
VERSION 5.7 ;
BUSBITCHARS "[]" ;
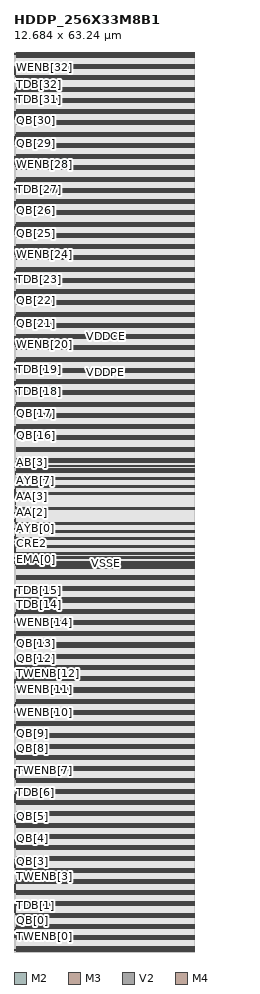
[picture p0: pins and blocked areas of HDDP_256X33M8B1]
MACRO HDDP_256X33M8B1
	FOREIGN HDDP_256X33M8B1 0 0 ;
	SYMMETRY X Y ;
	SIZE 12.684 BY 63.24 ;
	CLASS BLOCK ;
	PIN AA[0]
		USE SIGNAL ;
		DIRECTION INPUT ;
		SHAPE ABUTMENT ;
		PORT
			 LAYER M2 ;
			RECT 0.0098 30.3184 0.0481 30.3561 ;
		END

		ANTENNAGATEAREA 0.00027817 ;
		ANTENNADIFFAREA 0.00194719 ;
		ANTENNAPARTIALMETALAREA 0.00195671 ;
	END AA[0]

	PIN AA[1]
		USE SIGNAL ;
		DIRECTION INPUT ;
		SHAPE ABUTMENT ;
		PORT
			 LAYER M2 ;
			RECT 0.0098 30.3812 0.0481 30.4188 ;
		END

		ANTENNAGATEAREA 0.00027817 ;
		ANTENNADIFFAREA 0.00194719 ;
		ANTENNAPARTIALMETALAREA 0.00195671 ;
	END AA[1]

	PIN AA[2]
		USE SIGNAL ;
		DIRECTION INPUT ;
		SHAPE ABUTMENT ;
		PORT
			 LAYER M2 ;
			RECT 0.0098 30.8455 0.0481 30.8831 ;
		END

		ANTENNAGATEAREA 0.00027817 ;
		ANTENNADIFFAREA 0.00194719 ;
		ANTENNAPARTIALMETALAREA 0.00195671 ;
	END AA[2]

	PIN AA[3]
		USE SIGNAL ;
		DIRECTION INPUT ;
		SHAPE ABUTMENT ;
		PORT
			 LAYER M2 ;
			RECT 0.0098 31.4353 0.0481 31.4729 ;
		END

		ANTENNAGATEAREA 0.00027817 ;
		ANTENNADIFFAREA 0.00194719 ;
		ANTENNAPARTIALMETALAREA 0.00195671 ;
	END AA[3]

	PIN AA[4]
		USE SIGNAL ;
		DIRECTION INPUT ;
		SHAPE ABUTMENT ;
		PORT
			 LAYER M2 ;
			RECT 0.0098 31.8996 0.0481 31.9373 ;
		END

		ANTENNAGATEAREA 0.00027817 ;
		ANTENNADIFFAREA 0.00194719 ;
		ANTENNAPARTIALMETALAREA 0.00195671 ;
	END AA[4]

	PIN AA[5]
		USE SIGNAL ;
		DIRECTION INPUT ;
		SHAPE ABUTMENT ;
		PORT
			 LAYER M2 ;
			RECT 0.0098 31.9624 0.0481 32 ;
		END

		ANTENNAGATEAREA 0.00027817 ;
		ANTENNADIFFAREA 0.00194719 ;
		ANTENNAPARTIALMETALAREA 0.00195671 ;
	END AA[5]

	PIN AA[6]
		USE SIGNAL ;
		DIRECTION INPUT ;
		SHAPE ABUTMENT ;
		PORT
			 LAYER M2 ;
			RECT 0.0098 32.4267 0.0481 32.4643 ;
		END

		ANTENNAGATEAREA 0.00027817 ;
		ANTENNADIFFAREA 0.00194719 ;
		ANTENNAPARTIALMETALAREA 0.00195671 ;
	END AA[6]

	PIN AA[7]
		USE SIGNAL ;
		DIRECTION INPUT ;
		SHAPE ABUTMENT ;
		PORT
			 LAYER M2 ;
			RECT 0.0098 32.4894 0.0481 32.5271 ;
		END

		ANTENNAGATEAREA 0.00027817 ;
		ANTENNADIFFAREA 0.00194719 ;
		ANTENNAPARTIALMETALAREA 0.00195671 ;
	END AA[7]

	PIN AB[0]
		USE SIGNAL ;
		DIRECTION INPUT ;
		SHAPE ABUTMENT ;
		PORT
			 LAYER M3 ;
			RECT 0.0714 30.1051 0.1097 30.2055 ;
		END

		ANTENNAGATEAREA 0.00027817 ;
		ANTENNADIFFAREA 0.00194719 ;
		ANTENNAPARTIALMETALAREA 0.00195671 ;
	END AB[0]

	PIN AB[1]
		USE SIGNAL ;
		DIRECTION INPUT ;
		SHAPE ABUTMENT ;
		PORT
			 LAYER M3 ;
			RECT 0.0714 30.5067 0.1097 30.6071 ;
		END

		ANTENNAGATEAREA 0.00027817 ;
		ANTENNADIFFAREA 0.00194719 ;
		ANTENNAPARTIALMETALAREA 0.00195671 ;
	END AB[1]

	PIN AB[2]
		USE SIGNAL ;
		DIRECTION INPUT ;
		SHAPE ABUTMENT ;
		PORT
			 LAYER M3 ;
			RECT 0.0714 30.6573 0.1097 30.7576 ;
		END

		ANTENNAGATEAREA 0.00027817 ;
		ANTENNADIFFAREA 0.00194719 ;
		ANTENNAPARTIALMETALAREA 0.00195671 ;
	END AB[2]

	PIN AB[3]
		USE SIGNAL ;
		DIRECTION INPUT ;
		SHAPE ABUTMENT ;
		PORT
			 LAYER M2 ;
			RECT 0.0098 34.3718 0.0481 34.4094 ;
		END

		ANTENNAGATEAREA 0.00027817 ;
		ANTENNADIFFAREA 0.00194719 ;
		ANTENNAPARTIALMETALAREA 0.00195671 ;
	END AB[3]

	PIN AB[4]
		USE SIGNAL ;
		DIRECTION INPUT ;
		SHAPE ABUTMENT ;
		PORT
			 LAYER M3 ;
			RECT 0.0714 31.7114 0.1097 31.8118 ;
		END

		ANTENNAGATEAREA 0.00027817 ;
		ANTENNADIFFAREA 0.00194719 ;
		ANTENNAPARTIALMETALAREA 0.00195671 ;
	END AB[4]

	PIN AB[5]
		USE SIGNAL ;
		DIRECTION INPUT ;
		SHAPE ABUTMENT ;
		PORT
			 LAYER M3 ;
			RECT 0.0714 32.0878 0.1097 32.1882 ;
		END

		ANTENNAGATEAREA 0.00027817 ;
		ANTENNADIFFAREA 0.00194719 ;
		ANTENNAPARTIALMETALAREA 0.00195671 ;
	END AB[5]

	PIN AB[6]
		USE SIGNAL ;
		DIRECTION INPUT ;
		SHAPE ABUTMENT ;
		PORT
			 LAYER M3 ;
			RECT 0.0714 32.2384 0.1097 32.3388 ;
		END

		ANTENNAGATEAREA 0.00027817 ;
		ANTENNADIFFAREA 0.00194719 ;
		ANTENNAPARTIALMETALAREA 0.00195671 ;
	END AB[6]

	PIN AB[7]
		USE SIGNAL ;
		DIRECTION INPUT ;
		SHAPE ABUTMENT ;
		PORT
			 LAYER M3 ;
			RECT 0.0714 32.6149 0.1097 32.7153 ;
		END

		ANTENNAGATEAREA 0.00027817 ;
		ANTENNADIFFAREA 0.00194719 ;
		ANTENNAPARTIALMETALAREA 0.00195671 ;
	END AB[7]

	PIN AYA[0]
		USE SIGNAL ;
		DIRECTION OUTPUT ;
		SHAPE ABUTMENT ;
		PORT
			 LAYER M3 ;
			RECT 0.0714 30.2557 0.1097 30.3561 ;
		END

		ANTENNADIFFAREA 0.00194719 ;
		ANTENNAPARTIALMETALAREA 0.00195671 ;
	END AYA[0]

	PIN AYA[1]
		USE SIGNAL ;
		DIRECTION OUTPUT ;
		SHAPE ABUTMENT ;
		PORT
			 LAYER M3 ;
			RECT 0.0714 30.3812 0.1097 30.4816 ;
		END

		ANTENNADIFFAREA 0.00194719 ;
		ANTENNAPARTIALMETALAREA 0.00195671 ;
	END AYA[1]

	PIN AYA[2]
		USE SIGNAL ;
		DIRECTION OUTPUT ;
		SHAPE ABUTMENT ;
		PORT
			 LAYER M3 ;
			RECT 0.0714 30.7827 0.1097 30.8831 ;
		END

		ANTENNADIFFAREA 0.00194719 ;
		ANTENNAPARTIALMETALAREA 0.00195671 ;
	END AYA[2]

	PIN AYA[3]
		USE SIGNAL ;
		DIRECTION OUTPUT ;
		SHAPE ABUTMENT ;
		PORT
			 LAYER M3 ;
			RECT 0.0714 31.4353 0.1097 31.5357 ;
		END

		ANTENNADIFFAREA 0.00194719 ;
		ANTENNAPARTIALMETALAREA 0.00195671 ;
	END AYA[3]

	PIN AYA[4]
		USE SIGNAL ;
		DIRECTION OUTPUT ;
		SHAPE ABUTMENT ;
		PORT
			 LAYER M3 ;
			RECT 0.0714 31.8369 0.1097 31.9373 ;
		END

		ANTENNADIFFAREA 0.00194719 ;
		ANTENNAPARTIALMETALAREA 0.00195671 ;
	END AYA[4]

	PIN AYA[5]
		USE SIGNAL ;
		DIRECTION OUTPUT ;
		SHAPE ABUTMENT ;
		PORT
			 LAYER M3 ;
			RECT 0.0714 31.9624 0.1097 32.0627 ;
		END

		ANTENNADIFFAREA 0.00194719 ;
		ANTENNAPARTIALMETALAREA 0.00195671 ;
	END AYA[5]

	PIN AYA[6]
		USE SIGNAL ;
		DIRECTION OUTPUT ;
		SHAPE ABUTMENT ;
		PORT
			 LAYER M3 ;
			RECT 0.0714 32.3639 0.1097 32.4643 ;
		END

		ANTENNADIFFAREA 0.00194719 ;
		ANTENNAPARTIALMETALAREA 0.00195671 ;
	END AYA[6]

	PIN AYA[7]
		USE SIGNAL ;
		DIRECTION OUTPUT ;
		SHAPE ABUTMENT ;
		PORT
			 LAYER M3 ;
			RECT 0.0714 32.4894 0.1097 32.5898 ;
		END

		ANTENNADIFFAREA 0.00194719 ;
		ANTENNAPARTIALMETALAREA 0.00195671 ;
	END AYA[7]

	PIN AYB[0]
		USE SIGNAL ;
		DIRECTION OUTPUT ;
		SHAPE ABUTMENT ;
		PORT
			 LAYER M2 ;
			RECT 0.0098 30.2557 0.0481 30.2933 ;
		END

		ANTENNADIFFAREA 0.00194719 ;
		ANTENNAPARTIALMETALAREA 0.00195671 ;
	END AYB[0]

	PIN AYB[1]
		USE SIGNAL ;
		DIRECTION OUTPUT ;
		SHAPE ABUTMENT ;
		PORT
			 LAYER M2 ;
			RECT 0.0098 30.4439 0.0481 30.4816 ;
		END

		ANTENNADIFFAREA 0.00194719 ;
		ANTENNAPARTIALMETALAREA 0.00195671 ;
	END AYB[1]

	PIN AYB[2]
		USE SIGNAL ;
		DIRECTION OUTPUT ;
		SHAPE ABUTMENT ;
		PORT
			 LAYER M2 ;
			RECT 0.0098 30.7827 0.0481 30.8204 ;
		END

		ANTENNADIFFAREA 0.00194719 ;
		ANTENNAPARTIALMETALAREA 0.00195671 ;
	END AYB[2]

	PIN AYB[3]
		USE SIGNAL ;
		DIRECTION OUTPUT ;
		SHAPE ABUTMENT ;
		PORT
			 LAYER M2 ;
			RECT 0.0098 31.498 0.0481 31.5357 ;
		END

		ANTENNADIFFAREA 0.00194719 ;
		ANTENNAPARTIALMETALAREA 0.00195671 ;
	END AYB[3]

	PIN AYB[4]
		USE SIGNAL ;
		DIRECTION OUTPUT ;
		SHAPE ABUTMENT ;
		PORT
			 LAYER M2 ;
			RECT 0.0098 31.8369 0.0481 31.8745 ;
		END

		ANTENNADIFFAREA 0.00194719 ;
		ANTENNAPARTIALMETALAREA 0.00195671 ;
	END AYB[4]

	PIN AYB[5]
		USE SIGNAL ;
		DIRECTION OUTPUT ;
		SHAPE ABUTMENT ;
		PORT
			 LAYER M2 ;
			RECT 0.0098 32.0251 0.0481 32.0627 ;
		END

		ANTENNADIFFAREA 0.00194719 ;
		ANTENNAPARTIALMETALAREA 0.00195671 ;
	END AYB[5]

	PIN AYB[6]
		USE SIGNAL ;
		DIRECTION OUTPUT ;
		SHAPE ABUTMENT ;
		PORT
			 LAYER M2 ;
			RECT 0.0098 32.3639 0.0481 32.4016 ;
		END

		ANTENNADIFFAREA 0.00194719 ;
		ANTENNAPARTIALMETALAREA 0.00195671 ;
	END AYB[6]

	PIN AYB[7]
		USE SIGNAL ;
		DIRECTION OUTPUT ;
		SHAPE ABUTMENT ;
		PORT
			 LAYER M2 ;
			RECT 0.0098 32.5522 0.0481 32.5898 ;
		END

		ANTENNADIFFAREA 0.00194719 ;
		ANTENNAPARTIALMETALAREA 0.00195671 ;
	END AYB[7]

	PIN CENA
		USE SIGNAL ;
		DIRECTION INPUT ;
		SHAPE ABUTMENT ;
		PORT
			 LAYER M2 ;
			RECT 0.0098 33.5435 0.0481 33.5812 ;
		END

		ANTENNAGATEAREA 0.00027817 ;
		ANTENNADIFFAREA 0.00194719 ;
		ANTENNAPARTIALMETALAREA 0.00195671 ;
	END CENA

	PIN CENB
		USE SIGNAL ;
		DIRECTION INPUT ;
		SHAPE ABUTMENT ;
		PORT
			 LAYER M3 ;
			RECT 0.0714 33.669 0.1097 33.7694 ;
		END

		ANTENNAGATEAREA 0.00027817 ;
		ANTENNADIFFAREA 0.00194719 ;
		ANTENNAPARTIALMETALAREA 0.00195671 ;
	END CENB

	PIN CENYA
		USE SIGNAL ;
		DIRECTION OUTPUT ;
		SHAPE ABUTMENT ;
		PORT
			 LAYER M3 ;
			RECT 0.0714 33.5435 0.1097 33.6439 ;
		END

		ANTENNADIFFAREA 0.00194719 ;
		ANTENNAPARTIALMETALAREA 0.00195671 ;
	END CENYA

	PIN CENYB
		USE SIGNAL ;
		DIRECTION OUTPUT ;
		SHAPE ABUTMENT ;
		PORT
			 LAYER M2 ;
			RECT 0.0098 33.6063 0.0481 33.6439 ;
		END

		ANTENNADIFFAREA 0.00194719 ;
		ANTENNAPARTIALMETALAREA 0.00195671 ;
	END CENYB

	PIN CLK
		USE SIGNAL ;
		DIRECTION INPUT ;
		SHAPE ABUTMENT ;
		PORT
			 LAYER M3 ;
			RECT 0.0714 29.6533 0.1097 29.7537 ;
		END

		ANTENNAGATEAREA 0.00027817 ;
		ANTENNADIFFAREA 0.00194719 ;
		ANTENNAPARTIALMETALAREA 0.00195671 ;
	END CLK

	PIN CRE1
		USE SIGNAL ;
		DIRECTION INPUT ;
		SHAPE ABUTMENT ;
		PORT
			 LAYER M3 ;
			RECT 0.0714 28.0722 0.1097 28.1725 ;
		END

		ANTENNAGATEAREA 0.00027817 ;
		ANTENNADIFFAREA 0.00194719 ;
		ANTENNAPARTIALMETALAREA 0.00195671 ;
	END CRE1

	PIN CRE2
		USE SIGNAL ;
		DIRECTION INPUT ;
		SHAPE ABUTMENT ;
		PORT
			 LAYER M2 ;
			RECT 0.0098 28.6871 0.0481 28.7247 ;
		END

		ANTENNAGATEAREA 0.00027817 ;
		ANTENNADIFFAREA 0.00194719 ;
		ANTENNAPARTIALMETALAREA 0.00195671 ;
	END CRE2

	PIN DA[0]
		USE SIGNAL ;
		DIRECTION INPUT ;
		SHAPE ABUTMENT ;
		PORT
			 LAYER M2 ;
			RECT 0.0714 1.3929 0.1097 1.4306 ;
			 LAYER M3 ;
			RECT 0.0714 1.3302 0.1097 1.4306 ;
			 LAYER V2 ;
			RECT 0.0831 1.4059 0.098 1.4184 ;
		END

		ANTENNAGATEAREA 0.00027817 ;
		ANTENNADIFFAREA 0.00194719 ;
		ANTENNAPARTIALMETALAREA 0.00195671 ;
	END DA[0]

	PIN DA[10]
		USE SIGNAL ;
		DIRECTION INPUT ;
		SHAPE ABUTMENT ;
		PORT
			 LAYER M2 ;
			RECT 0.0714 17.2047 0.1097 17.2424 ;
			 LAYER M3 ;
			RECT 0.0714 17.142 0.1097 17.2424 ;
			 LAYER V2 ;
			RECT 0.0831 17.2176 0.098 17.2302 ;
		END

		ANTENNAGATEAREA 0.00027817 ;
		ANTENNADIFFAREA 0.00194719 ;
		ANTENNAPARTIALMETALAREA 0.00195671 ;
	END DA[10]

	PIN DA[11]
		USE SIGNAL ;
		DIRECTION INPUT ;
		SHAPE ABUTMENT ;
		PORT
			 LAYER M2 ;
			RECT 0.0714 18.7859 0.1097 18.8235 ;
			 LAYER M3 ;
			RECT 0.0714 18.7231 0.1097 18.8235 ;
			 LAYER V2 ;
			RECT 0.0831 18.7988 0.098 18.8114 ;
		END

		ANTENNAGATEAREA 0.00027817 ;
		ANTENNADIFFAREA 0.00194719 ;
		ANTENNAPARTIALMETALAREA 0.00195671 ;
	END DA[11]

	PIN DA[12]
		USE SIGNAL ;
		DIRECTION INPUT ;
		SHAPE ABUTMENT ;
		PORT
			 LAYER M2 ;
			RECT 0.0714 20.3671 0.1097 20.4047 ;
			 LAYER M3 ;
			RECT 0.0714 20.3043 0.1097 20.4047 ;
			 LAYER V2 ;
			RECT 0.0831 20.38 0.098 20.3925 ;
		END

		ANTENNAGATEAREA 0.00027817 ;
		ANTENNADIFFAREA 0.00194719 ;
		ANTENNAPARTIALMETALAREA 0.00195671 ;
	END DA[12]

	PIN DA[13]
		USE SIGNAL ;
		DIRECTION INPUT ;
		SHAPE ABUTMENT ;
		PORT
			 LAYER M2 ;
			RECT 0.0714 21.9482 0.1097 21.9859 ;
			 LAYER M3 ;
			RECT 0.0714 21.8855 0.1097 21.9859 ;
			 LAYER V2 ;
			RECT 0.0831 21.9612 0.098 21.9737 ;
		END

		ANTENNAGATEAREA 0.00027817 ;
		ANTENNADIFFAREA 0.00194719 ;
		ANTENNAPARTIALMETALAREA 0.00195671 ;
	END DA[13]

	PIN DA[14]
		USE SIGNAL ;
		DIRECTION INPUT ;
		SHAPE ABUTMENT ;
		PORT
			 LAYER M2 ;
			RECT 0.0714 23.5294 0.1097 23.5671 ;
			 LAYER M3 ;
			RECT 0.0714 23.4667 0.1097 23.5671 ;
			 LAYER V2 ;
			RECT 0.0831 23.5424 0.098 23.5549 ;
		END

		ANTENNAGATEAREA 0.00027817 ;
		ANTENNADIFFAREA 0.00194719 ;
		ANTENNAPARTIALMETALAREA 0.00195671 ;
	END DA[14]

	PIN DA[15]
		USE SIGNAL ;
		DIRECTION INPUT ;
		SHAPE ABUTMENT ;
		PORT
			 LAYER M2 ;
			RECT 0.0714 25.1106 0.1097 25.1482 ;
			 LAYER M3 ;
			RECT 0.0714 25.0478 0.1097 25.1482 ;
			 LAYER V2 ;
			RECT 0.0831 25.1235 0.098 25.1361 ;
		END

		ANTENNAGATEAREA 0.00027817 ;
		ANTENNADIFFAREA 0.00194719 ;
		ANTENNAPARTIALMETALAREA 0.00195671 ;
	END DA[15]

	PIN DA[16]
		USE SIGNAL ;
		DIRECTION INPUT ;
		SHAPE ABUTMENT ;
		PORT
			 LAYER M2 ;
			RECT 0.0714 36.4988 0.1097 36.5365 ;
			 LAYER M3 ;
			RECT 0.0714 36.4988 0.1097 36.5992 ;
			 LAYER V2 ;
			RECT 0.0831 36.511 0.098 36.5235 ;
		END

		ANTENNAGATEAREA 0.00027817 ;
		ANTENNADIFFAREA 0.00194719 ;
		ANTENNAPARTIALMETALAREA 0.00195671 ;
	END DA[16]

	PIN DA[17]
		USE SIGNAL ;
		DIRECTION INPUT ;
		SHAPE ABUTMENT ;
		PORT
			 LAYER M2 ;
			RECT 0.0714 38.08 0.1097 38.1176 ;
			 LAYER M3 ;
			RECT 0.0714 38.08 0.1097 38.1804 ;
			 LAYER V2 ;
			RECT 0.0831 38.0922 0.098 38.1047 ;
		END

		ANTENNAGATEAREA 0.00027817 ;
		ANTENNADIFFAREA 0.00194719 ;
		ANTENNAPARTIALMETALAREA 0.00195671 ;
	END DA[17]

	PIN DA[18]
		USE SIGNAL ;
		DIRECTION INPUT ;
		SHAPE ABUTMENT ;
		PORT
			 LAYER M2 ;
			RECT 0.0714 39.6612 0.1097 39.6988 ;
			 LAYER M3 ;
			RECT 0.0714 39.6612 0.1097 39.7616 ;
			 LAYER V2 ;
			RECT 0.0831 39.6733 0.098 39.6859 ;
		END

		ANTENNAGATEAREA 0.00027817 ;
		ANTENNADIFFAREA 0.00194719 ;
		ANTENNAPARTIALMETALAREA 0.00195671 ;
	END DA[18]

	PIN DA[19]
		USE SIGNAL ;
		DIRECTION INPUT ;
		SHAPE ABUTMENT ;
		PORT
			 LAYER M2 ;
			RECT 0.0714 41.2424 0.1097 41.28 ;
			 LAYER M3 ;
			RECT 0.0714 41.2424 0.1097 41.3427 ;
			 LAYER V2 ;
			RECT 0.0831 41.2545 0.098 41.2671 ;
		END

		ANTENNAGATEAREA 0.00027817 ;
		ANTENNADIFFAREA 0.00194719 ;
		ANTENNAPARTIALMETALAREA 0.00195671 ;
	END DA[19]

	PIN DA[1]
		USE SIGNAL ;
		DIRECTION INPUT ;
		SHAPE ABUTMENT ;
		PORT
			 LAYER M2 ;
			RECT 0.0714 2.9741 0.1097 3.0118 ;
			 LAYER M3 ;
			RECT 0.0714 2.9114 0.1097 3.0118 ;
			 LAYER V2 ;
			RECT 0.0831 2.9871 0.098 2.9996 ;
		END

		ANTENNAGATEAREA 0.00027817 ;
		ANTENNADIFFAREA 0.00194719 ;
		ANTENNAPARTIALMETALAREA 0.00195671 ;
	END DA[1]

	PIN DA[20]
		USE SIGNAL ;
		DIRECTION INPUT ;
		SHAPE ABUTMENT ;
		PORT
			 LAYER M2 ;
			RECT 0.0714 42.8235 0.1097 42.8612 ;
			 LAYER M3 ;
			RECT 0.0714 42.8235 0.1097 42.9239 ;
			 LAYER V2 ;
			RECT 0.0831 42.8357 0.098 42.8482 ;
		END

		ANTENNAGATEAREA 0.00027817 ;
		ANTENNADIFFAREA 0.00194719 ;
		ANTENNAPARTIALMETALAREA 0.00195671 ;
	END DA[20]

	PIN DA[21]
		USE SIGNAL ;
		DIRECTION INPUT ;
		SHAPE ABUTMENT ;
		PORT
			 LAYER M2 ;
			RECT 0.0714 44.4047 0.1097 44.4424 ;
			 LAYER M3 ;
			RECT 0.0714 44.4047 0.1097 44.5051 ;
			 LAYER V2 ;
			RECT 0.0831 44.4169 0.098 44.4294 ;
		END

		ANTENNAGATEAREA 0.00027817 ;
		ANTENNADIFFAREA 0.00194719 ;
		ANTENNAPARTIALMETALAREA 0.00195671 ;
	END DA[21]

	PIN DA[22]
		USE SIGNAL ;
		DIRECTION INPUT ;
		SHAPE ABUTMENT ;
		PORT
			 LAYER M2 ;
			RECT 0.0714 45.9859 0.1097 46.0235 ;
			 LAYER M3 ;
			RECT 0.0714 45.9859 0.1097 46.0863 ;
			 LAYER V2 ;
			RECT 0.0831 45.998 0.098 46.0106 ;
		END

		ANTENNAGATEAREA 0.00027817 ;
		ANTENNADIFFAREA 0.00194719 ;
		ANTENNAPARTIALMETALAREA 0.00195671 ;
	END DA[22]

	PIN DA[23]
		USE SIGNAL ;
		DIRECTION INPUT ;
		SHAPE ABUTMENT ;
		PORT
			 LAYER M2 ;
			RECT 0.0714 47.5671 0.1097 47.6047 ;
			 LAYER M3 ;
			RECT 0.0714 47.5671 0.1097 47.6675 ;
			 LAYER V2 ;
			RECT 0.0831 47.5792 0.098 47.5918 ;
		END

		ANTENNAGATEAREA 0.00027817 ;
		ANTENNADIFFAREA 0.00194719 ;
		ANTENNAPARTIALMETALAREA 0.00195671 ;
	END DA[23]

	PIN DA[24]
		USE SIGNAL ;
		DIRECTION INPUT ;
		SHAPE ABUTMENT ;
		PORT
			 LAYER M2 ;
			RECT 0.0714 49.1482 0.1097 49.1859 ;
			 LAYER M3 ;
			RECT 0.0714 49.1482 0.1097 49.2486 ;
			 LAYER V2 ;
			RECT 0.0831 49.1604 0.098 49.1729 ;
		END

		ANTENNAGATEAREA 0.00027817 ;
		ANTENNADIFFAREA 0.00194719 ;
		ANTENNAPARTIALMETALAREA 0.00195671 ;
	END DA[24]

	PIN DA[25]
		USE SIGNAL ;
		DIRECTION INPUT ;
		SHAPE ABUTMENT ;
		PORT
			 LAYER M2 ;
			RECT 0.0714 50.7294 0.1097 50.7671 ;
			 LAYER M3 ;
			RECT 0.0714 50.7294 0.1097 50.8298 ;
			 LAYER V2 ;
			RECT 0.0831 50.7416 0.098 50.7541 ;
		END

		ANTENNAGATEAREA 0.00027817 ;
		ANTENNADIFFAREA 0.00194719 ;
		ANTENNAPARTIALMETALAREA 0.00195671 ;
	END DA[25]

	PIN DA[26]
		USE SIGNAL ;
		DIRECTION INPUT ;
		SHAPE ABUTMENT ;
		PORT
			 LAYER M2 ;
			RECT 0.0714 52.3106 0.1097 52.3482 ;
			 LAYER M3 ;
			RECT 0.0714 52.3106 0.1097 52.411 ;
			 LAYER V2 ;
			RECT 0.0831 52.3227 0.098 52.3353 ;
		END

		ANTENNAGATEAREA 0.00027817 ;
		ANTENNADIFFAREA 0.00194719 ;
		ANTENNAPARTIALMETALAREA 0.00195671 ;
	END DA[26]

	PIN DA[27]
		USE SIGNAL ;
		DIRECTION INPUT ;
		SHAPE ABUTMENT ;
		PORT
			 LAYER M2 ;
			RECT 0.0714 53.8918 0.1097 53.9294 ;
			 LAYER M3 ;
			RECT 0.0714 53.8918 0.1097 53.9922 ;
			 LAYER V2 ;
			RECT 0.0831 53.9039 0.098 53.9165 ;
		END

		ANTENNAGATEAREA 0.00027817 ;
		ANTENNADIFFAREA 0.00194719 ;
		ANTENNAPARTIALMETALAREA 0.00195671 ;
	END DA[27]

	PIN DA[28]
		USE SIGNAL ;
		DIRECTION INPUT ;
		SHAPE ABUTMENT ;
		PORT
			 LAYER M2 ;
			RECT 0.0714 55.4729 0.1097 55.5106 ;
			 LAYER M3 ;
			RECT 0.0714 55.4729 0.1097 55.5733 ;
			 LAYER V2 ;
			RECT 0.0831 55.4851 0.098 55.4976 ;
		END

		ANTENNAGATEAREA 0.00027817 ;
		ANTENNADIFFAREA 0.00194719 ;
		ANTENNAPARTIALMETALAREA 0.00195671 ;
	END DA[28]

	PIN DA[29]
		USE SIGNAL ;
		DIRECTION INPUT ;
		SHAPE ABUTMENT ;
		PORT
			 LAYER M2 ;
			RECT 0.0714 57.0541 0.1097 57.0918 ;
			 LAYER M3 ;
			RECT 0.0714 57.0541 0.1097 57.1545 ;
			 LAYER V2 ;
			RECT 0.0831 57.0663 0.098 57.0788 ;
		END

		ANTENNAGATEAREA 0.00027817 ;
		ANTENNADIFFAREA 0.00194719 ;
		ANTENNAPARTIALMETALAREA 0.00195671 ;
	END DA[29]

	PIN DA[2]
		USE SIGNAL ;
		DIRECTION INPUT ;
		SHAPE ABUTMENT ;
		PORT
			 LAYER M2 ;
			RECT 0.0714 4.5553 0.1097 4.5929 ;
			 LAYER M3 ;
			RECT 0.0714 4.4925 0.1097 4.5929 ;
			 LAYER V2 ;
			RECT 0.0831 4.5682 0.098 4.5808 ;
		END

		ANTENNAGATEAREA 0.00027817 ;
		ANTENNADIFFAREA 0.00194719 ;
		ANTENNAPARTIALMETALAREA 0.00195671 ;
	END DA[2]

	PIN DA[30]
		USE SIGNAL ;
		DIRECTION INPUT ;
		SHAPE ABUTMENT ;
		PORT
			 LAYER M2 ;
			RECT 0.0714 58.6353 0.1097 58.6729 ;
			 LAYER M3 ;
			RECT 0.0714 58.6353 0.1097 58.7357 ;
			 LAYER V2 ;
			RECT 0.0831 58.6475 0.098 58.66 ;
		END

		ANTENNAGATEAREA 0.00027817 ;
		ANTENNADIFFAREA 0.00194719 ;
		ANTENNAPARTIALMETALAREA 0.00195671 ;
	END DA[30]

	PIN DA[31]
		USE SIGNAL ;
		DIRECTION INPUT ;
		SHAPE ABUTMENT ;
		PORT
			 LAYER M2 ;
			RECT 0.0714 60.2165 0.1097 60.2541 ;
			 LAYER M3 ;
			RECT 0.0714 60.2165 0.1097 60.3169 ;
			 LAYER V2 ;
			RECT 0.0831 60.2286 0.098 60.2412 ;
		END

		ANTENNAGATEAREA 0.00027817 ;
		ANTENNADIFFAREA 0.00194719 ;
		ANTENNAPARTIALMETALAREA 0.00195671 ;
	END DA[31]

	PIN DA[32]
		USE SIGNAL ;
		DIRECTION INPUT ;
		SHAPE ABUTMENT ;
		PORT
			 LAYER M2 ;
			RECT 0.0714 61.7976 0.1097 61.8353 ;
			 LAYER M3 ;
			RECT 0.0714 61.7976 0.1097 61.898 ;
			 LAYER V2 ;
			RECT 0.0831 61.8098 0.098 61.8224 ;
		END

		ANTENNAGATEAREA 0.00027817 ;
		ANTENNADIFFAREA 0.00194719 ;
		ANTENNAPARTIALMETALAREA 0.00195671 ;
	END DA[32]

	PIN DA[3]
		USE SIGNAL ;
		DIRECTION INPUT ;
		SHAPE ABUTMENT ;
		PORT
			 LAYER M2 ;
			RECT 0.0714 6.1365 0.1097 6.1741 ;
			 LAYER M3 ;
			RECT 0.0714 6.0737 0.1097 6.1741 ;
			 LAYER V2 ;
			RECT 0.0831 6.1494 0.098 6.162 ;
		END

		ANTENNAGATEAREA 0.00027817 ;
		ANTENNADIFFAREA 0.00194719 ;
		ANTENNAPARTIALMETALAREA 0.00195671 ;
	END DA[3]

	PIN DA[4]
		USE SIGNAL ;
		DIRECTION INPUT ;
		SHAPE ABUTMENT ;
		PORT
			 LAYER M2 ;
			RECT 0.0714 7.7176 0.1097 7.7553 ;
			 LAYER M3 ;
			RECT 0.0714 7.6549 0.1097 7.7553 ;
			 LAYER V2 ;
			RECT 0.0831 7.7306 0.098 7.7431 ;
		END

		ANTENNAGATEAREA 0.00027817 ;
		ANTENNADIFFAREA 0.00194719 ;
		ANTENNAPARTIALMETALAREA 0.00195671 ;
	END DA[4]

	PIN DA[5]
		USE SIGNAL ;
		DIRECTION INPUT ;
		SHAPE ABUTMENT ;
		PORT
			 LAYER M2 ;
			RECT 0.0714 9.2988 0.1097 9.3365 ;
			 LAYER M3 ;
			RECT 0.0714 9.2361 0.1097 9.3365 ;
			 LAYER V2 ;
			RECT 0.0831 9.3118 0.098 9.3243 ;
		END

		ANTENNAGATEAREA 0.00027817 ;
		ANTENNADIFFAREA 0.00194719 ;
		ANTENNAPARTIALMETALAREA 0.00195671 ;
	END DA[5]

	PIN DA[6]
		USE SIGNAL ;
		DIRECTION INPUT ;
		SHAPE ABUTMENT ;
		PORT
			 LAYER M2 ;
			RECT 0.0714 10.88 0.1097 10.9176 ;
			 LAYER M3 ;
			RECT 0.0714 10.8173 0.1097 10.9176 ;
			 LAYER V2 ;
			RECT 0.0831 10.8929 0.098 10.9055 ;
		END

		ANTENNAGATEAREA 0.00027817 ;
		ANTENNADIFFAREA 0.00194719 ;
		ANTENNAPARTIALMETALAREA 0.00195671 ;
	END DA[6]

	PIN DA[7]
		USE SIGNAL ;
		DIRECTION INPUT ;
		SHAPE ABUTMENT ;
		PORT
			 LAYER M2 ;
			RECT 0.0714 12.4612 0.1097 12.4988 ;
			 LAYER M3 ;
			RECT 0.0714 12.3984 0.1097 12.4988 ;
			 LAYER V2 ;
			RECT 0.0831 12.4741 0.098 12.4867 ;
		END

		ANTENNAGATEAREA 0.00027817 ;
		ANTENNADIFFAREA 0.00194719 ;
		ANTENNAPARTIALMETALAREA 0.00195671 ;
	END DA[7]

	PIN DA[8]
		USE SIGNAL ;
		DIRECTION INPUT ;
		SHAPE ABUTMENT ;
		PORT
			 LAYER M2 ;
			RECT 0.0714 14.0424 0.1097 14.08 ;
			 LAYER M3 ;
			RECT 0.0714 13.9796 0.1097 14.08 ;
			 LAYER V2 ;
			RECT 0.0831 14.0553 0.098 14.0678 ;
		END

		ANTENNAGATEAREA 0.00027817 ;
		ANTENNADIFFAREA 0.00194719 ;
		ANTENNAPARTIALMETALAREA 0.00195671 ;
	END DA[8]

	PIN DA[9]
		USE SIGNAL ;
		DIRECTION INPUT ;
		SHAPE ABUTMENT ;
		PORT
			 LAYER M2 ;
			RECT 0.0714 15.6235 0.1097 15.6612 ;
			 LAYER M3 ;
			RECT 0.0714 15.5608 0.1097 15.6612 ;
			 LAYER V2 ;
			RECT 0.0831 15.6365 0.098 15.649 ;
		END

		ANTENNAGATEAREA 0.00027817 ;
		ANTENNADIFFAREA 0.00194719 ;
		ANTENNAPARTIALMETALAREA 0.00195671 ;
	END DA[9]

	PIN DB[0]
		USE SIGNAL ;
		DIRECTION INPUT ;
		SHAPE ABUTMENT ;
		PORT
			 LAYER M3 ;
			RECT 0.0714 1.6314 0.1097 1.7318 ;
		END

		ANTENNAGATEAREA 0.00027817 ;
		ANTENNADIFFAREA 0.00194719 ;
		ANTENNAPARTIALMETALAREA 0.00195671 ;
	END DB[0]

	PIN DB[10]
		USE SIGNAL ;
		DIRECTION INPUT ;
		SHAPE ABUTMENT ;
		PORT
			 LAYER M3 ;
			RECT 0.0714 17.4431 0.1097 17.5435 ;
		END

		ANTENNAGATEAREA 0.00027817 ;
		ANTENNADIFFAREA 0.00194719 ;
		ANTENNAPARTIALMETALAREA 0.00195671 ;
	END DB[10]

	PIN DB[11]
		USE SIGNAL ;
		DIRECTION INPUT ;
		SHAPE ABUTMENT ;
		PORT
			 LAYER M3 ;
			RECT 0.0714 19.0243 0.1097 19.1247 ;
		END

		ANTENNAGATEAREA 0.00027817 ;
		ANTENNADIFFAREA 0.00194719 ;
		ANTENNAPARTIALMETALAREA 0.00195671 ;
	END DB[11]

	PIN DB[12]
		USE SIGNAL ;
		DIRECTION INPUT ;
		SHAPE ABUTMENT ;
		PORT
			 LAYER M3 ;
			RECT 0.0714 20.6055 0.1097 20.7059 ;
		END

		ANTENNAGATEAREA 0.00027817 ;
		ANTENNADIFFAREA 0.00194719 ;
		ANTENNAPARTIALMETALAREA 0.00195671 ;
	END DB[12]

	PIN DB[13]
		USE SIGNAL ;
		DIRECTION INPUT ;
		SHAPE ABUTMENT ;
		PORT
			 LAYER M3 ;
			RECT 0.0714 22.1867 0.1097 22.2871 ;
		END

		ANTENNAGATEAREA 0.00027817 ;
		ANTENNADIFFAREA 0.00194719 ;
		ANTENNAPARTIALMETALAREA 0.00195671 ;
	END DB[13]

	PIN DB[14]
		USE SIGNAL ;
		DIRECTION INPUT ;
		SHAPE ABUTMENT ;
		PORT
			 LAYER M3 ;
			RECT 0.0714 23.7678 0.1097 23.8682 ;
		END

		ANTENNAGATEAREA 0.00027817 ;
		ANTENNADIFFAREA 0.00194719 ;
		ANTENNAPARTIALMETALAREA 0.00195671 ;
	END DB[14]

	PIN DB[15]
		USE SIGNAL ;
		DIRECTION INPUT ;
		SHAPE ABUTMENT ;
		PORT
			 LAYER M3 ;
			RECT 0.0714 25.349 0.1097 25.4494 ;
		END

		ANTENNAGATEAREA 0.00027817 ;
		ANTENNADIFFAREA 0.00194719 ;
		ANTENNAPARTIALMETALAREA 0.00195671 ;
	END DB[15]

	PIN DB[16]
		USE SIGNAL ;
		DIRECTION INPUT ;
		SHAPE ABUTMENT ;
		PORT
			 LAYER M3 ;
			RECT 0.0714 36.1976 0.1097 36.298 ;
		END

		ANTENNAGATEAREA 0.00027817 ;
		ANTENNADIFFAREA 0.00194719 ;
		ANTENNAPARTIALMETALAREA 0.00195671 ;
	END DB[16]

	PIN DB[17]
		USE SIGNAL ;
		DIRECTION INPUT ;
		SHAPE ABUTMENT ;
		PORT
			 LAYER M3 ;
			RECT 0.0714 37.7788 0.1097 37.8792 ;
		END

		ANTENNAGATEAREA 0.00027817 ;
		ANTENNADIFFAREA 0.00194719 ;
		ANTENNAPARTIALMETALAREA 0.00195671 ;
	END DB[17]

	PIN DB[18]
		USE SIGNAL ;
		DIRECTION INPUT ;
		SHAPE ABUTMENT ;
		PORT
			 LAYER M3 ;
			RECT 0.0714 39.36 0.1097 39.4604 ;
		END

		ANTENNAGATEAREA 0.00027817 ;
		ANTENNADIFFAREA 0.00194719 ;
		ANTENNAPARTIALMETALAREA 0.00195671 ;
	END DB[18]

	PIN DB[19]
		USE SIGNAL ;
		DIRECTION INPUT ;
		SHAPE ABUTMENT ;
		PORT
			 LAYER M3 ;
			RECT 0.0714 40.9412 0.1097 41.0416 ;
		END

		ANTENNAGATEAREA 0.00027817 ;
		ANTENNADIFFAREA 0.00194719 ;
		ANTENNAPARTIALMETALAREA 0.00195671 ;
	END DB[19]

	PIN DB[1]
		USE SIGNAL ;
		DIRECTION INPUT ;
		SHAPE ABUTMENT ;
		PORT
			 LAYER M3 ;
			RECT 0.0714 3.2125 0.1097 3.3129 ;
		END

		ANTENNAGATEAREA 0.00027817 ;
		ANTENNADIFFAREA 0.00194719 ;
		ANTENNAPARTIALMETALAREA 0.00195671 ;
	END DB[1]

	PIN DB[20]
		USE SIGNAL ;
		DIRECTION INPUT ;
		SHAPE ABUTMENT ;
		PORT
			 LAYER M3 ;
			RECT 0.0714 42.5224 0.1097 42.6227 ;
		END

		ANTENNAGATEAREA 0.00027817 ;
		ANTENNADIFFAREA 0.00194719 ;
		ANTENNAPARTIALMETALAREA 0.00195671 ;
	END DB[20]

	PIN DB[21]
		USE SIGNAL ;
		DIRECTION INPUT ;
		SHAPE ABUTMENT ;
		PORT
			 LAYER M3 ;
			RECT 0.0714 44.1035 0.1097 44.2039 ;
		END

		ANTENNAGATEAREA 0.00027817 ;
		ANTENNADIFFAREA 0.00194719 ;
		ANTENNAPARTIALMETALAREA 0.00195671 ;
	END DB[21]

	PIN DB[22]
		USE SIGNAL ;
		DIRECTION INPUT ;
		SHAPE ABUTMENT ;
		PORT
			 LAYER M3 ;
			RECT 0.0714 45.6847 0.1097 45.7851 ;
		END

		ANTENNAGATEAREA 0.00027817 ;
		ANTENNADIFFAREA 0.00194719 ;
		ANTENNAPARTIALMETALAREA 0.00195671 ;
	END DB[22]

	PIN DB[23]
		USE SIGNAL ;
		DIRECTION INPUT ;
		SHAPE ABUTMENT ;
		PORT
			 LAYER M3 ;
			RECT 0.0714 47.2659 0.1097 47.3663 ;
		END

		ANTENNAGATEAREA 0.00027817 ;
		ANTENNADIFFAREA 0.00194719 ;
		ANTENNAPARTIALMETALAREA 0.00195671 ;
	END DB[23]

	PIN DB[24]
		USE SIGNAL ;
		DIRECTION INPUT ;
		SHAPE ABUTMENT ;
		PORT
			 LAYER M3 ;
			RECT 0.0714 48.8471 0.1097 48.9475 ;
		END

		ANTENNAGATEAREA 0.00027817 ;
		ANTENNADIFFAREA 0.00194719 ;
		ANTENNAPARTIALMETALAREA 0.00195671 ;
	END DB[24]

	PIN DB[25]
		USE SIGNAL ;
		DIRECTION INPUT ;
		SHAPE ABUTMENT ;
		PORT
			 LAYER M3 ;
			RECT 0.0714 50.4282 0.1097 50.5286 ;
		END

		ANTENNAGATEAREA 0.00027817 ;
		ANTENNADIFFAREA 0.00194719 ;
		ANTENNAPARTIALMETALAREA 0.00195671 ;
	END DB[25]

	PIN DB[26]
		USE SIGNAL ;
		DIRECTION INPUT ;
		SHAPE ABUTMENT ;
		PORT
			 LAYER M3 ;
			RECT 0.0714 52.0094 0.1097 52.1098 ;
		END

		ANTENNAGATEAREA 0.00027817 ;
		ANTENNADIFFAREA 0.00194719 ;
		ANTENNAPARTIALMETALAREA 0.00195671 ;
	END DB[26]

	PIN DB[27]
		USE SIGNAL ;
		DIRECTION INPUT ;
		SHAPE ABUTMENT ;
		PORT
			 LAYER M3 ;
			RECT 0.0714 53.5906 0.1097 53.691 ;
		END

		ANTENNAGATEAREA 0.00027817 ;
		ANTENNADIFFAREA 0.00194719 ;
		ANTENNAPARTIALMETALAREA 0.00195671 ;
	END DB[27]

	PIN DB[28]
		USE SIGNAL ;
		DIRECTION INPUT ;
		SHAPE ABUTMENT ;
		PORT
			 LAYER M3 ;
			RECT 0.0714 55.1718 0.1097 55.2722 ;
		END

		ANTENNAGATEAREA 0.00027817 ;
		ANTENNADIFFAREA 0.00194719 ;
		ANTENNAPARTIALMETALAREA 0.00195671 ;
	END DB[28]

	PIN DB[29]
		USE SIGNAL ;
		DIRECTION INPUT ;
		SHAPE ABUTMENT ;
		PORT
			 LAYER M3 ;
			RECT 0.0714 56.7529 0.1097 56.8533 ;
		END

		ANTENNAGATEAREA 0.00027817 ;
		ANTENNADIFFAREA 0.00194719 ;
		ANTENNAPARTIALMETALAREA 0.00195671 ;
	END DB[29]

	PIN DB[2]
		USE SIGNAL ;
		DIRECTION INPUT ;
		SHAPE ABUTMENT ;
		PORT
			 LAYER M3 ;
			RECT 0.0714 4.7937 0.1097 4.8941 ;
		END

		ANTENNAGATEAREA 0.00027817 ;
		ANTENNADIFFAREA 0.00194719 ;
		ANTENNAPARTIALMETALAREA 0.00195671 ;
	END DB[2]

	PIN DB[30]
		USE SIGNAL ;
		DIRECTION INPUT ;
		SHAPE ABUTMENT ;
		PORT
			 LAYER M3 ;
			RECT 0.0714 58.3341 0.1097 58.4345 ;
		END

		ANTENNAGATEAREA 0.00027817 ;
		ANTENNADIFFAREA 0.00194719 ;
		ANTENNAPARTIALMETALAREA 0.00195671 ;
	END DB[30]

	PIN DB[31]
		USE SIGNAL ;
		DIRECTION INPUT ;
		SHAPE ABUTMENT ;
		PORT
			 LAYER M3 ;
			RECT 0.0714 59.9153 0.1097 60.0157 ;
		END

		ANTENNAGATEAREA 0.00027817 ;
		ANTENNADIFFAREA 0.00194719 ;
		ANTENNAPARTIALMETALAREA 0.00195671 ;
	END DB[31]

	PIN DB[32]
		USE SIGNAL ;
		DIRECTION INPUT ;
		SHAPE ABUTMENT ;
		PORT
			 LAYER M3 ;
			RECT 0.0714 61.4965 0.1097 61.5969 ;
		END

		ANTENNAGATEAREA 0.00027817 ;
		ANTENNADIFFAREA 0.00194719 ;
		ANTENNAPARTIALMETALAREA 0.00195671 ;
	END DB[32]

	PIN DB[3]
		USE SIGNAL ;
		DIRECTION INPUT ;
		SHAPE ABUTMENT ;
		PORT
			 LAYER M3 ;
			RECT 0.0714 6.3749 0.1097 6.4753 ;
		END

		ANTENNAGATEAREA 0.00027817 ;
		ANTENNADIFFAREA 0.00194719 ;
		ANTENNAPARTIALMETALAREA 0.00195671 ;
	END DB[3]

	PIN DB[4]
		USE SIGNAL ;
		DIRECTION INPUT ;
		SHAPE ABUTMENT ;
		PORT
			 LAYER M3 ;
			RECT 0.0714 7.9561 0.1097 8.0565 ;
		END

		ANTENNAGATEAREA 0.00027817 ;
		ANTENNADIFFAREA 0.00194719 ;
		ANTENNAPARTIALMETALAREA 0.00195671 ;
	END DB[4]

	PIN DB[5]
		USE SIGNAL ;
		DIRECTION INPUT ;
		SHAPE ABUTMENT ;
		PORT
			 LAYER M3 ;
			RECT 0.0714 9.5373 0.1097 9.6376 ;
		END

		ANTENNAGATEAREA 0.00027817 ;
		ANTENNADIFFAREA 0.00194719 ;
		ANTENNAPARTIALMETALAREA 0.00195671 ;
	END DB[5]

	PIN DB[6]
		USE SIGNAL ;
		DIRECTION INPUT ;
		SHAPE ABUTMENT ;
		PORT
			 LAYER M3 ;
			RECT 0.0714 11.1184 0.1097 11.2188 ;
		END

		ANTENNAGATEAREA 0.00027817 ;
		ANTENNADIFFAREA 0.00194719 ;
		ANTENNAPARTIALMETALAREA 0.00195671 ;
	END DB[6]

	PIN DB[7]
		USE SIGNAL ;
		DIRECTION INPUT ;
		SHAPE ABUTMENT ;
		PORT
			 LAYER M3 ;
			RECT 0.0714 12.6996 0.1097 12.8 ;
		END

		ANTENNAGATEAREA 0.00027817 ;
		ANTENNADIFFAREA 0.00194719 ;
		ANTENNAPARTIALMETALAREA 0.00195671 ;
	END DB[7]

	PIN DB[8]
		USE SIGNAL ;
		DIRECTION INPUT ;
		SHAPE ABUTMENT ;
		PORT
			 LAYER M3 ;
			RECT 0.0714 14.2808 0.1097 14.3812 ;
		END

		ANTENNAGATEAREA 0.00027817 ;
		ANTENNADIFFAREA 0.00194719 ;
		ANTENNAPARTIALMETALAREA 0.00195671 ;
	END DB[8]

	PIN DB[9]
		USE SIGNAL ;
		DIRECTION INPUT ;
		SHAPE ABUTMENT ;
		PORT
			 LAYER M3 ;
			RECT 0.0714 15.862 0.1097 15.9624 ;
		END

		ANTENNAGATEAREA 0.00027817 ;
		ANTENNADIFFAREA 0.00194719 ;
		ANTENNAPARTIALMETALAREA 0.00195671 ;
	END DB[9]

	PIN DFTRAMBYP
		USE SIGNAL ;
		DIRECTION INPUT ;
		SHAPE ABUTMENT ;
		PORT
			 LAYER M2 ;
			RECT 0.0098 28.6243 0.0481 28.662 ;
		END

		ANTENNAGATEAREA 0.00027817 ;
		ANTENNADIFFAREA 0.00194719 ;
		ANTENNAPARTIALMETALAREA 0.00195671 ;
	END DFTRAMBYP

	PIN EMAP
		USE SIGNAL ;
		DIRECTION INPUT ;
		SHAPE ABUTMENT ;
		PORT
			 LAYER M2 ;
			RECT 0.0098 29.5027 0.0481 29.5404 ;
		END

		ANTENNAGATEAREA 0.00027817 ;
		ANTENNADIFFAREA 0.00194719 ;
		ANTENNAPARTIALMETALAREA 0.00195671 ;
	END EMAP

	PIN EMAS
		USE SIGNAL ;
		DIRECTION INPUT ;
		SHAPE ABUTMENT ;
		PORT
			 LAYER M3 ;
			RECT 0.0714 28.2227 0.1097 28.3231 ;
		END

		ANTENNAGATEAREA 0.00027817 ;
		ANTENNADIFFAREA 0.00194719 ;
		ANTENNAPARTIALMETALAREA 0.00195671 ;
	END EMAS

	PIN EMAW[0]
		USE SIGNAL ;
		DIRECTION INPUT ;
		SHAPE ABUTMENT ;
		PORT
			 LAYER M2 ;
			RECT 0.0098 28.2855 0.0481 28.3231 ;
		END

		ANTENNAGATEAREA 0.00027817 ;
		ANTENNADIFFAREA 0.00194719 ;
		ANTENNAPARTIALMETALAREA 0.00195671 ;
	END EMAW[0]

	PIN EMAW[1]
		USE SIGNAL ;
		DIRECTION INPUT ;
		SHAPE ABUTMENT ;
		PORT
			 LAYER M2 ;
			RECT 0.0098 28.2227 0.0481 28.2604 ;
		END

		ANTENNAGATEAREA 0.00027817 ;
		ANTENNADIFFAREA 0.00194719 ;
		ANTENNAPARTIALMETALAREA 0.00195671 ;
	END EMAW[1]

	PIN EMA[0]
		USE SIGNAL ;
		DIRECTION INPUT ;
		SHAPE ABUTMENT ;
		PORT
			 LAYER M2 ;
			RECT 0.0098 28.0722 0.0481 28.1098 ;
		END

		ANTENNAGATEAREA 0.00027817 ;
		ANTENNADIFFAREA 0.00194719 ;
		ANTENNAPARTIALMETALAREA 0.00195671 ;
	END EMA[0]

	PIN EMA[1]
		USE SIGNAL ;
		DIRECTION INPUT ;
		SHAPE ABUTMENT ;
		PORT
			 LAYER M2 ;
			RECT 0.0098 28.1349 0.0481 28.1725 ;
		END

		ANTENNAGATEAREA 0.00027817 ;
		ANTENNADIFFAREA 0.00194719 ;
		ANTENNAPARTIALMETALAREA 0.00195671 ;
	END EMA[1]

	PIN EMA[2]
		USE SIGNAL ;
		DIRECTION INPUT ;
		SHAPE ABUTMENT ;
		PORT
			 LAYER M3 ;
			RECT 0.0714 29.0761 0.1097 29.1765 ;
		END

		ANTENNAGATEAREA 0.00027817 ;
		ANTENNADIFFAREA 0.00194719 ;
		ANTENNAPARTIALMETALAREA 0.00195671 ;
	END EMA[2]

	PIN FCA1[0]
		USE SIGNAL ;
		DIRECTION INPUT ;
		SHAPE ABUTMENT ;
		PORT
			 LAYER M2 ;
			RECT 0.0098 31.6235 0.0481 31.6612 ;
		END

		ANTENNAGATEAREA 0.00027817 ;
		ANTENNADIFFAREA 0.00194719 ;
		ANTENNAPARTIALMETALAREA 0.00195671 ;
	END FCA1[0]

	PIN FCA1[1]
		USE SIGNAL ;
		DIRECTION INPUT ;
		SHAPE ABUTMENT ;
		PORT
			 LAYER M2 ;
			RECT 0.0098 27.3192 0.0481 27.4196 ;
			 LAYER M3 ;
			RECT 0.0098 27.3192 0.0481 27.4196 ;
			 LAYER V2 ;
			RECT 0.021 27.3941 0.0359 27.4067 ;
		END

		ANTENNAGATEAREA 0.00027817 ;
		ANTENNADIFFAREA 0.00194719 ;
		ANTENNAPARTIALMETALAREA 0.00195671 ;
	END FCA1[1]

	PIN FCA1[2]
		USE SIGNAL ;
		DIRECTION INPUT ;
		SHAPE ABUTMENT ;
		PORT
			 LAYER M2 ;
			RECT 0.0098 27.6831 0.0481 27.7208 ;
		END

		ANTENNAGATEAREA 0.00027817 ;
		ANTENNADIFFAREA 0.00194719 ;
		ANTENNAPARTIALMETALAREA 0.00195671 ;
	END FCA1[2]

	PIN FCA1[3]
		USE SIGNAL ;
		DIRECTION INPUT ;
		SHAPE ABUTMENT ;
		PORT
			 LAYER M3 ;
			RECT 0.0714 29.2267 0.1097 29.3271 ;
		END

		ANTENNAGATEAREA 0.00027817 ;
		ANTENNADIFFAREA 0.00194719 ;
		ANTENNAPARTIALMETALAREA 0.00195671 ;
	END FCA1[3]

	PIN FCA2[0]
		USE SIGNAL ;
		DIRECTION INPUT ;
		SHAPE ABUTMENT ;
		PORT
			 LAYER M3 ;
			RECT 0.0714 29.5027 0.1097 29.6031 ;
		END

		ANTENNAGATEAREA 0.00027817 ;
		ANTENNADIFFAREA 0.00194719 ;
		ANTENNAPARTIALMETALAREA 0.00195671 ;
	END FCA2[0]

	PIN FCA2[1]
		USE SIGNAL ;
		DIRECTION INPUT ;
		SHAPE ABUTMENT ;
		PORT
			 LAYER M2 ;
			RECT 0.0098 34.4345 0.0481 34.4722 ;
		END

		ANTENNAGATEAREA 0.00027817 ;
		ANTENNADIFFAREA 0.00194719 ;
		ANTENNAPARTIALMETALAREA 0.00195671 ;
	END FCA2[1]

	PIN FCA2[2]
		USE SIGNAL ;
		DIRECTION INPUT ;
		SHAPE ABUTMENT ;
		PORT
			 LAYER M2 ;
			RECT 0.0098 27.6204 0.0481 27.658 ;
		END

		ANTENNAGATEAREA 0.00027817 ;
		ANTENNADIFFAREA 0.00194719 ;
		ANTENNAPARTIALMETALAREA 0.00195671 ;
	END FCA2[2]

	PIN FCA2[3]
		USE SIGNAL ;
		DIRECTION INPUT ;
		SHAPE ABUTMENT ;
		PORT
			 LAYER M3 ;
			RECT 0.0714 34.0706 0.1097 34.171 ;
		END

		ANTENNAGATEAREA 0.00027817 ;
		ANTENNADIFFAREA 0.00194719 ;
		ANTENNAPARTIALMETALAREA 0.00195671 ;
	END FCA2[3]

	PIN FCA2[4]
		USE SIGNAL ;
		DIRECTION INPUT ;
		SHAPE ABUTMENT ;
		PORT
			 LAYER M2 ;
			RECT 0.0098 34.0706 0.0481 34.1082 ;
		END

		ANTENNAGATEAREA 0.00027817 ;
		ANTENNADIFFAREA 0.00194719 ;
		ANTENNAPARTIALMETALAREA 0.00195671 ;
	END FCA2[4]

	PIN GWENA
		USE SIGNAL ;
		DIRECTION INPUT ;
		SHAPE ABUTMENT ;
		PORT
			 LAYER M2 ;
			RECT 0.0098 28.4361 0.0481 28.4737 ;
			 LAYER M3 ;
			RECT 0.0098 28.3733 0.0481 28.4737 ;
			 LAYER V2 ;
			RECT 0.0215 28.4482 0.0364 28.4608 ;
		END

		ANTENNAGATEAREA 0.00027817 ;
		ANTENNADIFFAREA 0.00194719 ;
		ANTENNAPARTIALMETALAREA 0.00195671 ;
	END GWENA

	PIN GWENB
		USE SIGNAL ;
		DIRECTION INPUT ;
		SHAPE ABUTMENT ;
		PORT
			 LAYER M2 ;
			RECT 0.0098 28.7498 0.0481 28.7875 ;
			 LAYER M3 ;
			RECT 0.0098 28.7498 0.0481 28.8502 ;
			 LAYER V2 ;
			RECT 0.0215 28.7627 0.0364 28.7753 ;
		END

		ANTENNAGATEAREA 0.00027817 ;
		ANTENNADIFFAREA 0.00194719 ;
		ANTENNAPARTIALMETALAREA 0.00195671 ;
	END GWENB

	PIN GWENYA
		USE SIGNAL ;
		DIRECTION OUTPUT ;
		SHAPE ABUTMENT ;
		PORT
			 LAYER M2 ;
			RECT 0.0098 28.5616 0.0481 28.5992 ;
			 LAYER M3 ;
			RECT 0.0098 28.4988 0.0481 28.5992 ;
			 LAYER V2 ;
			RECT 0.0215 28.5737 0.0364 28.5863 ;
		END

		ANTENNADIFFAREA 0.00194719 ;
		ANTENNAPARTIALMETALAREA 0.00195671 ;
	END GWENYA

	PIN GWENYB
		USE SIGNAL ;
		DIRECTION OUTPUT ;
		SHAPE ABUTMENT ;
		PORT
			 LAYER M2 ;
			RECT 0.0714 28.8125 0.1097 28.8502 ;
			 LAYER M3 ;
			RECT 0.0714 28.7498 0.1097 28.8502 ;
			 LAYER V2 ;
			RECT 0.0831 28.8255 0.098 28.838 ;
		END

		ANTENNADIFFAREA 0.00194719 ;
		ANTENNAPARTIALMETALAREA 0.00195671 ;
	END GWENYB

	PIN QA[0]
		USE SIGNAL ;
		DIRECTION OUTPUT ;
		SHAPE ABUTMENT ;
		PORT
			 LAYER M2 ;
			RECT 0.0098 1.5435 0.0481 1.5812 ;
			 LAYER M3 ;
			RECT 0.0098 1.4808 0.0481 1.5812 ;
			 LAYER V2 ;
			RECT 0.0215 1.5557 0.0364 1.5682 ;
		END

		ANTENNADIFFAREA 0.00194719 ;
		ANTENNAPARTIALMETALAREA 0.00195671 ;
	END QA[0]

	PIN QA[10]
		USE SIGNAL ;
		DIRECTION OUTPUT ;
		SHAPE ABUTMENT ;
		PORT
			 LAYER M2 ;
			RECT 0.0098 17.3553 0.0481 17.3929 ;
			 LAYER M3 ;
			RECT 0.0098 17.2925 0.0481 17.3929 ;
			 LAYER V2 ;
			RECT 0.0215 17.3675 0.0364 17.38 ;
		END

		ANTENNADIFFAREA 0.00194719 ;
		ANTENNAPARTIALMETALAREA 0.00195671 ;
	END QA[10]

	PIN QA[11]
		USE SIGNAL ;
		DIRECTION OUTPUT ;
		SHAPE ABUTMENT ;
		PORT
			 LAYER M2 ;
			RECT 0.0098 18.9365 0.0481 18.9741 ;
			 LAYER M3 ;
			RECT 0.0098 18.8737 0.0481 18.9741 ;
			 LAYER V2 ;
			RECT 0.0215 18.9486 0.0364 18.9612 ;
		END

		ANTENNADIFFAREA 0.00194719 ;
		ANTENNAPARTIALMETALAREA 0.00195671 ;
	END QA[11]

	PIN QA[12]
		USE SIGNAL ;
		DIRECTION OUTPUT ;
		SHAPE ABUTMENT ;
		PORT
			 LAYER M2 ;
			RECT 0.0098 20.5176 0.0481 20.5553 ;
			 LAYER M3 ;
			RECT 0.0098 20.4549 0.0481 20.5553 ;
			 LAYER V2 ;
			RECT 0.0215 20.5298 0.0364 20.5424 ;
		END

		ANTENNADIFFAREA 0.00194719 ;
		ANTENNAPARTIALMETALAREA 0.00195671 ;
	END QA[12]

	PIN QA[13]
		USE SIGNAL ;
		DIRECTION OUTPUT ;
		SHAPE ABUTMENT ;
		PORT
			 LAYER M2 ;
			RECT 0.0098 22.0988 0.0481 22.1365 ;
			 LAYER M3 ;
			RECT 0.0098 22.0361 0.0481 22.1365 ;
			 LAYER V2 ;
			RECT 0.0215 22.111 0.0364 22.1235 ;
		END

		ANTENNADIFFAREA 0.00194719 ;
		ANTENNAPARTIALMETALAREA 0.00195671 ;
	END QA[13]

	PIN QA[14]
		USE SIGNAL ;
		DIRECTION OUTPUT ;
		SHAPE ABUTMENT ;
		PORT
			 LAYER M2 ;
			RECT 0.0098 23.68 0.0481 23.7176 ;
			 LAYER M3 ;
			RECT 0.0098 23.6173 0.0481 23.7176 ;
			 LAYER V2 ;
			RECT 0.0215 23.6922 0.0364 23.7047 ;
		END

		ANTENNADIFFAREA 0.00194719 ;
		ANTENNAPARTIALMETALAREA 0.00195671 ;
	END QA[14]

	PIN QA[15]
		USE SIGNAL ;
		DIRECTION OUTPUT ;
		SHAPE ABUTMENT ;
		PORT
			 LAYER M2 ;
			RECT 0.0098 25.2612 0.0481 25.2988 ;
			 LAYER M3 ;
			RECT 0.0098 25.1984 0.0481 25.2988 ;
			 LAYER V2 ;
			RECT 0.0215 25.2733 0.0364 25.2859 ;
		END

		ANTENNADIFFAREA 0.00194719 ;
		ANTENNAPARTIALMETALAREA 0.00195671 ;
	END QA[15]

	PIN QA[16]
		USE SIGNAL ;
		DIRECTION OUTPUT ;
		SHAPE ABUTMENT ;
		PORT
			 LAYER M2 ;
			RECT 0.0098 36.3482 0.0481 36.3859 ;
			 LAYER M3 ;
			RECT 0.0098 36.3482 0.0481 36.4486 ;
			 LAYER V2 ;
			RECT 0.0215 36.3612 0.0364 36.3737 ;
		END

		ANTENNADIFFAREA 0.00194719 ;
		ANTENNAPARTIALMETALAREA 0.00195671 ;
	END QA[16]

	PIN QA[17]
		USE SIGNAL ;
		DIRECTION OUTPUT ;
		SHAPE ABUTMENT ;
		PORT
			 LAYER M2 ;
			RECT 0.0098 37.9294 0.0481 37.9671 ;
			 LAYER M3 ;
			RECT 0.0098 37.9294 0.0481 38.0298 ;
			 LAYER V2 ;
			RECT 0.0215 37.9424 0.0364 37.9549 ;
		END

		ANTENNADIFFAREA 0.00194719 ;
		ANTENNAPARTIALMETALAREA 0.00195671 ;
	END QA[17]

	PIN QA[18]
		USE SIGNAL ;
		DIRECTION OUTPUT ;
		SHAPE ABUTMENT ;
		PORT
			 LAYER M2 ;
			RECT 0.0098 39.5106 0.0481 39.5482 ;
			 LAYER M3 ;
			RECT 0.0098 39.5106 0.0481 39.611 ;
			 LAYER V2 ;
			RECT 0.0215 39.5235 0.0364 39.5361 ;
		END

		ANTENNADIFFAREA 0.00194719 ;
		ANTENNAPARTIALMETALAREA 0.00195671 ;
	END QA[18]

	PIN QA[19]
		USE SIGNAL ;
		DIRECTION OUTPUT ;
		SHAPE ABUTMENT ;
		PORT
			 LAYER M2 ;
			RECT 0.0098 41.0918 0.0481 41.1294 ;
			 LAYER M3 ;
			RECT 0.0098 41.0918 0.0481 41.1922 ;
			 LAYER V2 ;
			RECT 0.0215 41.1047 0.0364 41.1173 ;
		END

		ANTENNADIFFAREA 0.00194719 ;
		ANTENNAPARTIALMETALAREA 0.00195671 ;
	END QA[19]

	PIN QA[1]
		USE SIGNAL ;
		DIRECTION OUTPUT ;
		SHAPE ABUTMENT ;
		PORT
			 LAYER M2 ;
			RECT 0.0098 3.1247 0.0481 3.1624 ;
			 LAYER M3 ;
			RECT 0.0098 3.062 0.0481 3.1624 ;
			 LAYER V2 ;
			RECT 0.0215 3.1369 0.0364 3.1494 ;
		END

		ANTENNADIFFAREA 0.00194719 ;
		ANTENNAPARTIALMETALAREA 0.00195671 ;
	END QA[1]

	PIN QA[20]
		USE SIGNAL ;
		DIRECTION OUTPUT ;
		SHAPE ABUTMENT ;
		PORT
			 LAYER M2 ;
			RECT 0.0098 42.6729 0.0481 42.7106 ;
			 LAYER M3 ;
			RECT 0.0098 42.6729 0.0481 42.7733 ;
			 LAYER V2 ;
			RECT 0.0215 42.6859 0.0364 42.6984 ;
		END

		ANTENNADIFFAREA 0.00194719 ;
		ANTENNAPARTIALMETALAREA 0.00195671 ;
	END QA[20]

	PIN QA[21]
		USE SIGNAL ;
		DIRECTION OUTPUT ;
		SHAPE ABUTMENT ;
		PORT
			 LAYER M2 ;
			RECT 0.0098 44.2541 0.0481 44.2918 ;
			 LAYER M3 ;
			RECT 0.0098 44.2541 0.0481 44.3545 ;
			 LAYER V2 ;
			RECT 0.0215 44.2671 0.0364 44.2796 ;
		END

		ANTENNADIFFAREA 0.00194719 ;
		ANTENNAPARTIALMETALAREA 0.00195671 ;
	END QA[21]

	PIN QA[22]
		USE SIGNAL ;
		DIRECTION OUTPUT ;
		SHAPE ABUTMENT ;
		PORT
			 LAYER M2 ;
			RECT 0.0098 45.8353 0.0481 45.8729 ;
			 LAYER M3 ;
			RECT 0.0098 45.8353 0.0481 45.9357 ;
			 LAYER V2 ;
			RECT 0.0215 45.8482 0.0364 45.8608 ;
		END

		ANTENNADIFFAREA 0.00194719 ;
		ANTENNAPARTIALMETALAREA 0.00195671 ;
	END QA[22]

	PIN QA[23]
		USE SIGNAL ;
		DIRECTION OUTPUT ;
		SHAPE ABUTMENT ;
		PORT
			 LAYER M2 ;
			RECT 0.0098 47.4165 0.0481 47.4541 ;
			 LAYER M3 ;
			RECT 0.0098 47.4165 0.0481 47.5169 ;
			 LAYER V2 ;
			RECT 0.0215 47.4294 0.0364 47.442 ;
		END

		ANTENNADIFFAREA 0.00194719 ;
		ANTENNAPARTIALMETALAREA 0.00195671 ;
	END QA[23]

	PIN QA[24]
		USE SIGNAL ;
		DIRECTION OUTPUT ;
		SHAPE ABUTMENT ;
		PORT
			 LAYER M2 ;
			RECT 0.0098 48.9976 0.0481 49.0353 ;
			 LAYER M3 ;
			RECT 0.0098 48.9976 0.0481 49.098 ;
			 LAYER V2 ;
			RECT 0.0215 49.0106 0.0364 49.0231 ;
		END

		ANTENNADIFFAREA 0.00194719 ;
		ANTENNAPARTIALMETALAREA 0.00195671 ;
	END QA[24]

	PIN QA[25]
		USE SIGNAL ;
		DIRECTION OUTPUT ;
		SHAPE ABUTMENT ;
		PORT
			 LAYER M2 ;
			RECT 0.0098 50.5788 0.0481 50.6165 ;
			 LAYER M3 ;
			RECT 0.0098 50.5788 0.0481 50.6792 ;
			 LAYER V2 ;
			RECT 0.0215 50.5918 0.0364 50.6043 ;
		END

		ANTENNADIFFAREA 0.00194719 ;
		ANTENNAPARTIALMETALAREA 0.00195671 ;
	END QA[25]

	PIN QA[26]
		USE SIGNAL ;
		DIRECTION OUTPUT ;
		SHAPE ABUTMENT ;
		PORT
			 LAYER M2 ;
			RECT 0.0098 52.16 0.0481 52.1976 ;
			 LAYER M3 ;
			RECT 0.0098 52.16 0.0481 52.2604 ;
			 LAYER V2 ;
			RECT 0.0215 52.1729 0.0364 52.1855 ;
		END

		ANTENNADIFFAREA 0.00194719 ;
		ANTENNAPARTIALMETALAREA 0.00195671 ;
	END QA[26]

	PIN QA[27]
		USE SIGNAL ;
		DIRECTION OUTPUT ;
		SHAPE ABUTMENT ;
		PORT
			 LAYER M2 ;
			RECT 0.0098 53.7412 0.0481 53.7788 ;
			 LAYER M3 ;
			RECT 0.0098 53.7412 0.0481 53.8416 ;
			 LAYER V2 ;
			RECT 0.0215 53.7541 0.0364 53.7667 ;
		END

		ANTENNADIFFAREA 0.00194719 ;
		ANTENNAPARTIALMETALAREA 0.00195671 ;
	END QA[27]

	PIN QA[28]
		USE SIGNAL ;
		DIRECTION OUTPUT ;
		SHAPE ABUTMENT ;
		PORT
			 LAYER M2 ;
			RECT 0.0098 55.3224 0.0481 55.36 ;
			 LAYER M3 ;
			RECT 0.0098 55.3224 0.0481 55.4227 ;
			 LAYER V2 ;
			RECT 0.0215 55.3353 0.0364 55.3478 ;
		END

		ANTENNADIFFAREA 0.00194719 ;
		ANTENNAPARTIALMETALAREA 0.00195671 ;
	END QA[28]

	PIN QA[29]
		USE SIGNAL ;
		DIRECTION OUTPUT ;
		SHAPE ABUTMENT ;
		PORT
			 LAYER M2 ;
			RECT 0.0098 56.9035 0.0481 56.9412 ;
			 LAYER M3 ;
			RECT 0.0098 56.9035 0.0481 57.0039 ;
			 LAYER V2 ;
			RECT 0.0215 56.9165 0.0364 56.929 ;
		END

		ANTENNADIFFAREA 0.00194719 ;
		ANTENNAPARTIALMETALAREA 0.00195671 ;
	END QA[29]

	PIN QA[2]
		USE SIGNAL ;
		DIRECTION OUTPUT ;
		SHAPE ABUTMENT ;
		PORT
			 LAYER M2 ;
			RECT 0.0098 4.7059 0.0481 4.7435 ;
			 LAYER M3 ;
			RECT 0.0098 4.6431 0.0481 4.7435 ;
			 LAYER V2 ;
			RECT 0.0215 4.718 0.0364 4.7306 ;
		END

		ANTENNADIFFAREA 0.00194719 ;
		ANTENNAPARTIALMETALAREA 0.00195671 ;
	END QA[2]

	PIN QA[30]
		USE SIGNAL ;
		DIRECTION OUTPUT ;
		SHAPE ABUTMENT ;
		PORT
			 LAYER M2 ;
			RECT 0.0098 58.4847 0.0481 58.5224 ;
			 LAYER M3 ;
			RECT 0.0098 58.4847 0.0481 58.5851 ;
			 LAYER V2 ;
			RECT 0.0215 58.4976 0.0364 58.5102 ;
		END

		ANTENNADIFFAREA 0.00194719 ;
		ANTENNAPARTIALMETALAREA 0.00195671 ;
	END QA[30]

	PIN QA[31]
		USE SIGNAL ;
		DIRECTION OUTPUT ;
		SHAPE ABUTMENT ;
		PORT
			 LAYER M2 ;
			RECT 0.0098 60.0659 0.0481 60.1035 ;
			 LAYER M3 ;
			RECT 0.0098 60.0659 0.0481 60.1663 ;
			 LAYER V2 ;
			RECT 0.0215 60.0788 0.0364 60.0914 ;
		END

		ANTENNADIFFAREA 0.00194719 ;
		ANTENNAPARTIALMETALAREA 0.00195671 ;
	END QA[31]

	PIN QA[32]
		USE SIGNAL ;
		DIRECTION OUTPUT ;
		SHAPE ABUTMENT ;
		PORT
			 LAYER M2 ;
			RECT 0.0098 61.6471 0.0481 61.6847 ;
			 LAYER M3 ;
			RECT 0.0098 61.6471 0.0481 61.7475 ;
			 LAYER V2 ;
			RECT 0.0215 61.66 0.0364 61.6725 ;
		END

		ANTENNADIFFAREA 0.00194719 ;
		ANTENNAPARTIALMETALAREA 0.00195671 ;
	END QA[32]

	PIN QA[3]
		USE SIGNAL ;
		DIRECTION OUTPUT ;
		SHAPE ABUTMENT ;
		PORT
			 LAYER M2 ;
			RECT 0.0098 6.2871 0.0481 6.3247 ;
			 LAYER M3 ;
			RECT 0.0098 6.2243 0.0481 6.3247 ;
			 LAYER V2 ;
			RECT 0.0215 6.2992 0.0364 6.3118 ;
		END

		ANTENNADIFFAREA 0.00194719 ;
		ANTENNAPARTIALMETALAREA 0.00195671 ;
	END QA[3]

	PIN QA[4]
		USE SIGNAL ;
		DIRECTION OUTPUT ;
		SHAPE ABUTMENT ;
		PORT
			 LAYER M2 ;
			RECT 0.0098 7.8682 0.0481 7.9059 ;
			 LAYER M3 ;
			RECT 0.0098 7.8055 0.0481 7.9059 ;
			 LAYER V2 ;
			RECT 0.0215 7.8804 0.0364 7.8929 ;
		END

		ANTENNADIFFAREA 0.00194719 ;
		ANTENNAPARTIALMETALAREA 0.00195671 ;
	END QA[4]

	PIN QA[5]
		USE SIGNAL ;
		DIRECTION OUTPUT ;
		SHAPE ABUTMENT ;
		PORT
			 LAYER M2 ;
			RECT 0.0098 9.4494 0.0481 9.4871 ;
			 LAYER M3 ;
			RECT 0.0098 9.3867 0.0481 9.4871 ;
			 LAYER V2 ;
			RECT 0.0215 9.4616 0.0364 9.4741 ;
		END

		ANTENNADIFFAREA 0.00194719 ;
		ANTENNAPARTIALMETALAREA 0.00195671 ;
	END QA[5]

	PIN QA[6]
		USE SIGNAL ;
		DIRECTION OUTPUT ;
		SHAPE ABUTMENT ;
		PORT
			 LAYER M2 ;
			RECT 0.0098 11.0306 0.0481 11.0682 ;
			 LAYER M3 ;
			RECT 0.0098 10.9678 0.0481 11.0682 ;
			 LAYER V2 ;
			RECT 0.0215 11.0427 0.0364 11.0553 ;
		END

		ANTENNADIFFAREA 0.00194719 ;
		ANTENNAPARTIALMETALAREA 0.00195671 ;
	END QA[6]

	PIN QA[7]
		USE SIGNAL ;
		DIRECTION OUTPUT ;
		SHAPE ABUTMENT ;
		PORT
			 LAYER M2 ;
			RECT 0.0098 12.6118 0.0481 12.6494 ;
			 LAYER M3 ;
			RECT 0.0098 12.549 0.0481 12.6494 ;
			 LAYER V2 ;
			RECT 0.0215 12.6239 0.0364 12.6365 ;
		END

		ANTENNADIFFAREA 0.00194719 ;
		ANTENNAPARTIALMETALAREA 0.00195671 ;
	END QA[7]

	PIN QA[8]
		USE SIGNAL ;
		DIRECTION OUTPUT ;
		SHAPE ABUTMENT ;
		PORT
			 LAYER M2 ;
			RECT 0.0098 14.1929 0.0481 14.2306 ;
			 LAYER M3 ;
			RECT 0.0098 14.1302 0.0481 14.2306 ;
			 LAYER V2 ;
			RECT 0.0215 14.2051 0.0364 14.2176 ;
		END

		ANTENNADIFFAREA 0.00194719 ;
		ANTENNAPARTIALMETALAREA 0.00195671 ;
	END QA[8]

	PIN QA[9]
		USE SIGNAL ;
		DIRECTION OUTPUT ;
		SHAPE ABUTMENT ;
		PORT
			 LAYER M2 ;
			RECT 0.0098 15.7741 0.0481 15.8118 ;
			 LAYER M3 ;
			RECT 0.0098 15.7114 0.0481 15.8118 ;
			 LAYER V2 ;
			RECT 0.0215 15.7863 0.0364 15.7988 ;
		END

		ANTENNADIFFAREA 0.00194719 ;
		ANTENNAPARTIALMETALAREA 0.00195671 ;
	END QA[9]

	PIN QB[0]
		USE SIGNAL ;
		DIRECTION OUTPUT ;
		SHAPE ABUTMENT ;
		PORT
			 LAYER M2 ;
			RECT 0.0098 1.6314 0.0481 1.669 ;
		END

		ANTENNADIFFAREA 0.00194719 ;
		ANTENNAPARTIALMETALAREA 0.00195671 ;
	END QB[0]

	PIN QB[10]
		USE SIGNAL ;
		DIRECTION OUTPUT ;
		SHAPE ABUTMENT ;
		PORT
			 LAYER M2 ;
			RECT 0.0098 17.4431 0.0481 17.4808 ;
		END

		ANTENNADIFFAREA 0.00194719 ;
		ANTENNAPARTIALMETALAREA 0.00195671 ;
	END QB[10]

	PIN QB[11]
		USE SIGNAL ;
		DIRECTION OUTPUT ;
		SHAPE ABUTMENT ;
		PORT
			 LAYER M2 ;
			RECT 0.0098 19.0243 0.0481 19.062 ;
		END

		ANTENNADIFFAREA 0.00194719 ;
		ANTENNAPARTIALMETALAREA 0.00195671 ;
	END QB[11]

	PIN QB[12]
		USE SIGNAL ;
		DIRECTION OUTPUT ;
		SHAPE ABUTMENT ;
		PORT
			 LAYER M2 ;
			RECT 0.0098 20.6055 0.0481 20.6431 ;
		END

		ANTENNADIFFAREA 0.00194719 ;
		ANTENNAPARTIALMETALAREA 0.00195671 ;
	END QB[12]

	PIN QB[13]
		USE SIGNAL ;
		DIRECTION OUTPUT ;
		SHAPE ABUTMENT ;
		PORT
			 LAYER M2 ;
			RECT 0.0098 22.1867 0.0481 22.2243 ;
		END

		ANTENNADIFFAREA 0.00194719 ;
		ANTENNAPARTIALMETALAREA 0.00195671 ;
	END QB[13]

	PIN QB[14]
		USE SIGNAL ;
		DIRECTION OUTPUT ;
		SHAPE ABUTMENT ;
		PORT
			 LAYER M2 ;
			RECT 0.0098 23.7678 0.0481 23.8055 ;
		END

		ANTENNADIFFAREA 0.00194719 ;
		ANTENNAPARTIALMETALAREA 0.00195671 ;
	END QB[14]

	PIN QB[15]
		USE SIGNAL ;
		DIRECTION OUTPUT ;
		SHAPE ABUTMENT ;
		PORT
			 LAYER M2 ;
			RECT 0.0098 25.349 0.0481 25.3867 ;
		END

		ANTENNADIFFAREA 0.00194719 ;
		ANTENNAPARTIALMETALAREA 0.00195671 ;
	END QB[15]

	PIN QB[16]
		USE SIGNAL ;
		DIRECTION OUTPUT ;
		SHAPE ABUTMENT ;
		PORT
			 LAYER M2 ;
			RECT 0.0098 36.2604 0.0481 36.298 ;
		END

		ANTENNADIFFAREA 0.00194719 ;
		ANTENNAPARTIALMETALAREA 0.00195671 ;
	END QB[16]

	PIN QB[17]
		USE SIGNAL ;
		DIRECTION OUTPUT ;
		SHAPE ABUTMENT ;
		PORT
			 LAYER M2 ;
			RECT 0.0098 37.8416 0.0481 37.8792 ;
		END

		ANTENNADIFFAREA 0.00194719 ;
		ANTENNAPARTIALMETALAREA 0.00195671 ;
	END QB[17]

	PIN QB[18]
		USE SIGNAL ;
		DIRECTION OUTPUT ;
		SHAPE ABUTMENT ;
		PORT
			 LAYER M2 ;
			RECT 0.0098 39.4227 0.0481 39.4604 ;
		END

		ANTENNADIFFAREA 0.00194719 ;
		ANTENNAPARTIALMETALAREA 0.00195671 ;
	END QB[18]

	PIN QB[19]
		USE SIGNAL ;
		DIRECTION OUTPUT ;
		SHAPE ABUTMENT ;
		PORT
			 LAYER M2 ;
			RECT 0.0098 41.0039 0.0481 41.0416 ;
		END

		ANTENNADIFFAREA 0.00194719 ;
		ANTENNAPARTIALMETALAREA 0.00195671 ;
	END QB[19]

	PIN QB[1]
		USE SIGNAL ;
		DIRECTION OUTPUT ;
		SHAPE ABUTMENT ;
		PORT
			 LAYER M2 ;
			RECT 0.0098 3.2125 0.0481 3.2502 ;
		END

		ANTENNADIFFAREA 0.00194719 ;
		ANTENNAPARTIALMETALAREA 0.00195671 ;
	END QB[1]

	PIN QB[20]
		USE SIGNAL ;
		DIRECTION OUTPUT ;
		SHAPE ABUTMENT ;
		PORT
			 LAYER M2 ;
			RECT 0.0098 42.5851 0.0481 42.6227 ;
		END

		ANTENNADIFFAREA 0.00194719 ;
		ANTENNAPARTIALMETALAREA 0.00195671 ;
	END QB[20]

	PIN QB[21]
		USE SIGNAL ;
		DIRECTION OUTPUT ;
		SHAPE ABUTMENT ;
		PORT
			 LAYER M2 ;
			RECT 0.0098 44.1663 0.0481 44.2039 ;
		END

		ANTENNADIFFAREA 0.00194719 ;
		ANTENNAPARTIALMETALAREA 0.00195671 ;
	END QB[21]

	PIN QB[22]
		USE SIGNAL ;
		DIRECTION OUTPUT ;
		SHAPE ABUTMENT ;
		PORT
			 LAYER M2 ;
			RECT 0.0098 45.7475 0.0481 45.7851 ;
		END

		ANTENNADIFFAREA 0.00194719 ;
		ANTENNAPARTIALMETALAREA 0.00195671 ;
	END QB[22]

	PIN QB[23]
		USE SIGNAL ;
		DIRECTION OUTPUT ;
		SHAPE ABUTMENT ;
		PORT
			 LAYER M2 ;
			RECT 0.0098 47.3286 0.0481 47.3663 ;
		END

		ANTENNADIFFAREA 0.00194719 ;
		ANTENNAPARTIALMETALAREA 0.00195671 ;
	END QB[23]

	PIN QB[24]
		USE SIGNAL ;
		DIRECTION OUTPUT ;
		SHAPE ABUTMENT ;
		PORT
			 LAYER M2 ;
			RECT 0.0098 48.9098 0.0481 48.9475 ;
		END

		ANTENNADIFFAREA 0.00194719 ;
		ANTENNAPARTIALMETALAREA 0.00195671 ;
	END QB[24]

	PIN QB[25]
		USE SIGNAL ;
		DIRECTION OUTPUT ;
		SHAPE ABUTMENT ;
		PORT
			 LAYER M2 ;
			RECT 0.0098 50.491 0.0481 50.5286 ;
		END

		ANTENNADIFFAREA 0.00194719 ;
		ANTENNAPARTIALMETALAREA 0.00195671 ;
	END QB[25]

	PIN QB[26]
		USE SIGNAL ;
		DIRECTION OUTPUT ;
		SHAPE ABUTMENT ;
		PORT
			 LAYER M2 ;
			RECT 0.0098 52.0722 0.0481 52.1098 ;
		END

		ANTENNADIFFAREA 0.00194719 ;
		ANTENNAPARTIALMETALAREA 0.00195671 ;
	END QB[26]

	PIN QB[27]
		USE SIGNAL ;
		DIRECTION OUTPUT ;
		SHAPE ABUTMENT ;
		PORT
			 LAYER M2 ;
			RECT 0.0098 53.6533 0.0481 53.691 ;
		END

		ANTENNADIFFAREA 0.00194719 ;
		ANTENNAPARTIALMETALAREA 0.00195671 ;
	END QB[27]

	PIN QB[28]
		USE SIGNAL ;
		DIRECTION OUTPUT ;
		SHAPE ABUTMENT ;
		PORT
			 LAYER M2 ;
			RECT 0.0098 55.2345 0.0481 55.2722 ;
		END

		ANTENNADIFFAREA 0.00194719 ;
		ANTENNAPARTIALMETALAREA 0.00195671 ;
	END QB[28]

	PIN QB[29]
		USE SIGNAL ;
		DIRECTION OUTPUT ;
		SHAPE ABUTMENT ;
		PORT
			 LAYER M2 ;
			RECT 0.0098 56.8157 0.0481 56.8533 ;
		END

		ANTENNADIFFAREA 0.00194719 ;
		ANTENNAPARTIALMETALAREA 0.00195671 ;
	END QB[29]

	PIN QB[2]
		USE SIGNAL ;
		DIRECTION OUTPUT ;
		SHAPE ABUTMENT ;
		PORT
			 LAYER M2 ;
			RECT 0.0098 4.7937 0.0481 4.8314 ;
		END

		ANTENNADIFFAREA 0.00194719 ;
		ANTENNAPARTIALMETALAREA 0.00195671 ;
	END QB[2]

	PIN QB[30]
		USE SIGNAL ;
		DIRECTION OUTPUT ;
		SHAPE ABUTMENT ;
		PORT
			 LAYER M2 ;
			RECT 0.0098 58.3969 0.0481 58.4345 ;
		END

		ANTENNADIFFAREA 0.00194719 ;
		ANTENNAPARTIALMETALAREA 0.00195671 ;
	END QB[30]

	PIN QB[31]
		USE SIGNAL ;
		DIRECTION OUTPUT ;
		SHAPE ABUTMENT ;
		PORT
			 LAYER M2 ;
			RECT 0.0098 59.978 0.0481 60.0157 ;
		END

		ANTENNADIFFAREA 0.00194719 ;
		ANTENNAPARTIALMETALAREA 0.00195671 ;
	END QB[31]

	PIN QB[32]
		USE SIGNAL ;
		DIRECTION OUTPUT ;
		SHAPE ABUTMENT ;
		PORT
			 LAYER M2 ;
			RECT 0.0098 61.5592 0.0481 61.5969 ;
		END

		ANTENNADIFFAREA 0.00194719 ;
		ANTENNAPARTIALMETALAREA 0.00195671 ;
	END QB[32]

	PIN QB[3]
		USE SIGNAL ;
		DIRECTION OUTPUT ;
		SHAPE ABUTMENT ;
		PORT
			 LAYER M2 ;
			RECT 0.0098 6.3749 0.0481 6.4125 ;
		END

		ANTENNADIFFAREA 0.00194719 ;
		ANTENNAPARTIALMETALAREA 0.00195671 ;
	END QB[3]

	PIN QB[4]
		USE SIGNAL ;
		DIRECTION OUTPUT ;
		SHAPE ABUTMENT ;
		PORT
			 LAYER M2 ;
			RECT 0.0098 7.9561 0.0481 7.9937 ;
		END

		ANTENNADIFFAREA 0.00194719 ;
		ANTENNAPARTIALMETALAREA 0.00195671 ;
	END QB[4]

	PIN QB[5]
		USE SIGNAL ;
		DIRECTION OUTPUT ;
		SHAPE ABUTMENT ;
		PORT
			 LAYER M2 ;
			RECT 0.0098 9.5373 0.0481 9.5749 ;
		END

		ANTENNADIFFAREA 0.00194719 ;
		ANTENNAPARTIALMETALAREA 0.00195671 ;
	END QB[5]

	PIN QB[6]
		USE SIGNAL ;
		DIRECTION OUTPUT ;
		SHAPE ABUTMENT ;
		PORT
			 LAYER M2 ;
			RECT 0.0098 11.1184 0.0481 11.1561 ;
		END

		ANTENNADIFFAREA 0.00194719 ;
		ANTENNAPARTIALMETALAREA 0.00195671 ;
	END QB[6]

	PIN QB[7]
		USE SIGNAL ;
		DIRECTION OUTPUT ;
		SHAPE ABUTMENT ;
		PORT
			 LAYER M2 ;
			RECT 0.0098 12.6996 0.0481 12.7373 ;
		END

		ANTENNADIFFAREA 0.00194719 ;
		ANTENNAPARTIALMETALAREA 0.00195671 ;
	END QB[7]

	PIN QB[8]
		USE SIGNAL ;
		DIRECTION OUTPUT ;
		SHAPE ABUTMENT ;
		PORT
			 LAYER M2 ;
			RECT 0.0098 14.2808 0.0481 14.3184 ;
		END

		ANTENNADIFFAREA 0.00194719 ;
		ANTENNAPARTIALMETALAREA 0.00195671 ;
	END QB[8]

	PIN QB[9]
		USE SIGNAL ;
		DIRECTION OUTPUT ;
		SHAPE ABUTMENT ;
		PORT
			 LAYER M2 ;
			RECT 0.0098 15.862 0.0481 15.8996 ;
		END

		ANTENNADIFFAREA 0.00194719 ;
		ANTENNAPARTIALMETALAREA 0.00195671 ;
	END QB[9]

	PIN RET1N
		USE SIGNAL ;
		DIRECTION INPUT ;
		SHAPE ABUTMENT ;
		PORT
			 LAYER M2 ;
			RECT 0.0098 29.0761 0.0481 29.1137 ;
		END

		ANTENNAGATEAREA 0.00027817 ;
		ANTENNADIFFAREA 0.00194719 ;
		ANTENNAPARTIALMETALAREA 0.00195671 ;
	END RET1N

	PIN SE
		USE SIGNAL ;
		DIRECTION INPUT ;
		SHAPE ABUTMENT ;
		PORT
			 LAYER M2 ;
			RECT 0.0098 34.1333 0.0481 34.171 ;
		END

		ANTENNAGATEAREA 0.00027817 ;
		ANTENNADIFFAREA 0.00194719 ;
		ANTENNAPARTIALMETALAREA 0.00195671 ;
	END SE

	PIN SIA[0]
		USE SIGNAL ;
		DIRECTION INPUT ;
		SHAPE ABUTMENT ;
		PORT
			 LAYER M2 ;
			RECT 0.0714 0.1506 0.1097 0.1882 ;
			 LAYER M3 ;
			RECT 0.0714 0.0878 0.1097 0.1882 ;
			 LAYER V2 ;
			RECT 0.0831 0.1635 0.098 0.1761 ;
		END

		ANTENNAGATEAREA 0.00027817 ;
		ANTENNADIFFAREA 0.00194719 ;
		ANTENNAPARTIALMETALAREA 0.00195671 ;
	END SIA[0]

	PIN SIA[1]
		USE SIGNAL ;
		DIRECTION INPUT ;
		SHAPE ABUTMENT ;
		PORT
			 LAYER M2 ;
			RECT 0.0714 63.04 0.1097 63.0776 ;
			 LAYER M3 ;
			RECT 0.0714 63.04 0.1097 63.1404 ;
			 LAYER V2 ;
			RECT 0.0831 63.0522 0.098 63.0647 ;
		END

		ANTENNAGATEAREA 0.00027817 ;
		ANTENNADIFFAREA 0.00194719 ;
		ANTENNAPARTIALMETALAREA 0.00195671 ;
	END SIA[1]

	PIN SIB[0]
		USE SIGNAL ;
		DIRECTION INPUT ;
		SHAPE ABUTMENT ;
		PORT
			 LAYER M2 ;
			RECT 0.0098 0.0878 0.0481 0.1255 ;
			 LAYER M3 ;
			RECT 0.0098 0.0878 0.0481 0.1882 ;
			 LAYER V2 ;
			RECT 0.0215 0.1008 0.0364 0.1133 ;
		END

		ANTENNAGATEAREA 0.00027817 ;
		ANTENNADIFFAREA 0.00194719 ;
		ANTENNAPARTIALMETALAREA 0.00195671 ;
	END SIB[0]

	PIN SIB[1]
		USE SIGNAL ;
		DIRECTION INPUT ;
		SHAPE ABUTMENT ;
		PORT
			 LAYER M2 ;
			RECT 0.0098 63.1027 0.0481 63.1404 ;
			 LAYER M3 ;
			RECT 0.0098 63.04 0.0481 63.1404 ;
			 LAYER V2 ;
			RECT 0.0215 63.1149 0.0364 63.1275 ;
		END

		ANTENNAGATEAREA 0.00027817 ;
		ANTENNADIFFAREA 0.00194719 ;
		ANTENNAPARTIALMETALAREA 0.00195671 ;
	END SIB[1]

	PIN SOA[0]
		USE SIGNAL ;
		DIRECTION OUTPUT ;
		SHAPE ABUTMENT ;
		PORT
			 LAYER M3 ;
			RECT 0.0714 27.6204 0.1097 27.7208 ;
		END

		ANTENNADIFFAREA 0.00194719 ;
		ANTENNAPARTIALMETALAREA 0.00195671 ;
	END SOA[0]

	PIN SOA[1]
		USE SIGNAL ;
		DIRECTION OUTPUT ;
		SHAPE ABUTMENT ;
		PORT
			 LAYER M3 ;
			RECT 0.0714 34.2212 0.1097 34.3216 ;
		END

		ANTENNADIFFAREA 0.00194719 ;
		ANTENNAPARTIALMETALAREA 0.00195671 ;
	END SOA[1]

	PIN SOB[0]
		USE SIGNAL ;
		DIRECTION OUTPUT ;
		SHAPE ABUTMENT ;
		PORT
			 LAYER M2 ;
			RECT 0.0714 28.4988 0.1097 28.5365 ;
			 LAYER M3 ;
			RECT 0.0714 28.4988 0.1097 28.5992 ;
			 LAYER V2 ;
			RECT 0.0831 28.511 0.098 28.5235 ;
		END

		ANTENNADIFFAREA 0.00194719 ;
		ANTENNAPARTIALMETALAREA 0.00195671 ;
	END SOB[0]

	PIN SOB[1]
		USE SIGNAL ;
		DIRECTION OUTPUT ;
		SHAPE ABUTMENT ;
		PORT
			 LAYER M2 ;
			RECT 0.0714 29.44 0.1097 29.4776 ;
			 LAYER M3 ;
			RECT 0.0714 29.3773 0.1097 29.4776 ;
			 LAYER V2 ;
			RECT 0.0831 29.4529 0.098 29.4655 ;
		END

		ANTENNADIFFAREA 0.00194719 ;
		ANTENNAPARTIALMETALAREA 0.00195671 ;
	END SOB[1]

	PIN STOV
		USE SIGNAL ;
		DIRECTION INPUT ;
		SHAPE ABUTMENT ;
		PORT
			 LAYER M2 ;
			RECT 0.0098 29.7161 0.0481 29.7537 ;
		END

		ANTENNAGATEAREA 0.00027817 ;
		ANTENNADIFFAREA 0.00194719 ;
		ANTENNAPARTIALMETALAREA 0.00195671 ;
	END STOV

	PIN STOVAB
		USE SIGNAL ;
		DIRECTION INPUT ;
		SHAPE ABUTMENT ;
		PORT
			 LAYER M3 ;
			RECT 0.0714 31.1843 0.1097 31.2847 ;
		END

		ANTENNAGATEAREA 0.00027817 ;
		ANTENNADIFFAREA 0.00194719 ;
		ANTENNAPARTIALMETALAREA 0.00195671 ;
	END STOVAB

	PIN TAA[0]
		USE SIGNAL ;
		DIRECTION INPUT ;
		SHAPE ABUTMENT ;
		PORT
			 LAYER M2 ;
			RECT 0.0098 30.1678 0.0481 30.2055 ;
		END

		ANTENNAGATEAREA 0.00027817 ;
		ANTENNADIFFAREA 0.00194719 ;
		ANTENNAPARTIALMETALAREA 0.00195671 ;
	END TAA[0]

	PIN TAA[1]
		USE SIGNAL ;
		DIRECTION INPUT ;
		SHAPE ABUTMENT ;
		PORT
			 LAYER M2 ;
			RECT 0.0098 30.5067 0.0481 30.5443 ;
		END

		ANTENNAGATEAREA 0.00027817 ;
		ANTENNADIFFAREA 0.00194719 ;
		ANTENNAPARTIALMETALAREA 0.00195671 ;
	END TAA[1]

	PIN TAA[2]
		USE SIGNAL ;
		DIRECTION INPUT ;
		SHAPE ABUTMENT ;
		PORT
			 LAYER M2 ;
			RECT 0.0098 30.72 0.0481 30.7576 ;
		END

		ANTENNAGATEAREA 0.00027817 ;
		ANTENNADIFFAREA 0.00194719 ;
		ANTENNAPARTIALMETALAREA 0.00195671 ;
	END TAA[2]

	PIN TAA[3]
		USE SIGNAL ;
		DIRECTION INPUT ;
		SHAPE ABUTMENT ;
		PORT
			 LAYER M3 ;
			RECT 0.0714 34.3718 0.1097 34.4722 ;
		END

		ANTENNAGATEAREA 0.00027817 ;
		ANTENNADIFFAREA 0.00194719 ;
		ANTENNAPARTIALMETALAREA 0.00195671 ;
	END TAA[3]

	PIN TAA[4]
		USE SIGNAL ;
		DIRECTION INPUT ;
		SHAPE ABUTMENT ;
		PORT
			 LAYER M2 ;
			RECT 0.0098 31.7741 0.0481 31.8118 ;
		END

		ANTENNAGATEAREA 0.00027817 ;
		ANTENNADIFFAREA 0.00194719 ;
		ANTENNAPARTIALMETALAREA 0.00195671 ;
	END TAA[4]

	PIN TAA[5]
		USE SIGNAL ;
		DIRECTION INPUT ;
		SHAPE ABUTMENT ;
		PORT
			 LAYER M2 ;
			RECT 0.0098 32.0878 0.0481 32.1255 ;
		END

		ANTENNAGATEAREA 0.00027817 ;
		ANTENNADIFFAREA 0.00194719 ;
		ANTENNAPARTIALMETALAREA 0.00195671 ;
	END TAA[5]

	PIN TAA[6]
		USE SIGNAL ;
		DIRECTION INPUT ;
		SHAPE ABUTMENT ;
		PORT
			 LAYER M2 ;
			RECT 0.0098 32.3012 0.0481 32.3388 ;
		END

		ANTENNAGATEAREA 0.00027817 ;
		ANTENNADIFFAREA 0.00194719 ;
		ANTENNAPARTIALMETALAREA 0.00195671 ;
	END TAA[6]

	PIN TAA[7]
		USE SIGNAL ;
		DIRECTION INPUT ;
		SHAPE ABUTMENT ;
		PORT
			 LAYER M2 ;
			RECT 0.0098 32.6149 0.0481 32.6525 ;
		END

		ANTENNAGATEAREA 0.00027817 ;
		ANTENNADIFFAREA 0.00194719 ;
		ANTENNAPARTIALMETALAREA 0.00195671 ;
	END TAA[7]

	PIN TAB[0]
		USE SIGNAL ;
		DIRECTION INPUT ;
		SHAPE ABUTMENT ;
		PORT
			 LAYER M2 ;
			RECT 0.0098 30.1051 0.0481 30.1427 ;
		END

		ANTENNAGATEAREA 0.00027817 ;
		ANTENNADIFFAREA 0.00194719 ;
		ANTENNAPARTIALMETALAREA 0.00195671 ;
	END TAB[0]

	PIN TAB[1]
		USE SIGNAL ;
		DIRECTION INPUT ;
		SHAPE ABUTMENT ;
		PORT
			 LAYER M2 ;
			RECT 0.0098 30.5694 0.0481 30.6071 ;
		END

		ANTENNAGATEAREA 0.00027817 ;
		ANTENNADIFFAREA 0.00194719 ;
		ANTENNAPARTIALMETALAREA 0.00195671 ;
	END TAB[1]

	PIN TAB[2]
		USE SIGNAL ;
		DIRECTION INPUT ;
		SHAPE ABUTMENT ;
		PORT
			 LAYER M2 ;
			RECT 0.0098 30.6573 0.0481 30.6949 ;
		END

		ANTENNAGATEAREA 0.00027817 ;
		ANTENNADIFFAREA 0.00194719 ;
		ANTENNAPARTIALMETALAREA 0.00195671 ;
	END TAB[2]

	PIN TAB[3]
		USE SIGNAL ;
		DIRECTION INPUT ;
		SHAPE ABUTMENT ;
		PORT
			 LAYER M3 ;
			RECT 0.0714 31.5608 0.1097 31.6612 ;
		END

		ANTENNAGATEAREA 0.00027817 ;
		ANTENNADIFFAREA 0.00194719 ;
		ANTENNAPARTIALMETALAREA 0.00195671 ;
	END TAB[3]

	PIN TAB[4]
		USE SIGNAL ;
		DIRECTION INPUT ;
		SHAPE ABUTMENT ;
		PORT
			 LAYER M2 ;
			RECT 0.0098 31.7114 0.0481 31.749 ;
		END

		ANTENNAGATEAREA 0.00027817 ;
		ANTENNADIFFAREA 0.00194719 ;
		ANTENNAPARTIALMETALAREA 0.00195671 ;
	END TAB[4]

	PIN TAB[5]
		USE SIGNAL ;
		DIRECTION INPUT ;
		SHAPE ABUTMENT ;
		PORT
			 LAYER M2 ;
			RECT 0.0098 32.1506 0.0481 32.1882 ;
		END

		ANTENNAGATEAREA 0.00027817 ;
		ANTENNADIFFAREA 0.00194719 ;
		ANTENNAPARTIALMETALAREA 0.00195671 ;
	END TAB[5]

	PIN TAB[6]
		USE SIGNAL ;
		DIRECTION INPUT ;
		SHAPE ABUTMENT ;
		PORT
			 LAYER M2 ;
			RECT 0.0098 32.2384 0.0481 32.2761 ;
		END

		ANTENNAGATEAREA 0.00027817 ;
		ANTENNADIFFAREA 0.00194719 ;
		ANTENNAPARTIALMETALAREA 0.00195671 ;
	END TAB[6]

	PIN TAB[7]
		USE SIGNAL ;
		DIRECTION INPUT ;
		SHAPE ABUTMENT ;
		PORT
			 LAYER M2 ;
			RECT 0.0098 32.6776 0.0481 32.7153 ;
		END

		ANTENNAGATEAREA 0.00027817 ;
		ANTENNADIFFAREA 0.00194719 ;
		ANTENNAPARTIALMETALAREA 0.00195671 ;
	END TAB[7]

	PIN TCENA
		USE SIGNAL ;
		DIRECTION INPUT ;
		SHAPE ABUTMENT ;
		PORT
			 LAYER M2 ;
			RECT 0.0098 33.669 0.0481 33.7067 ;
		END

		ANTENNAGATEAREA 0.00027817 ;
		ANTENNADIFFAREA 0.00194719 ;
		ANTENNAPARTIALMETALAREA 0.00195671 ;
	END TCENA

	PIN TCENB
		USE SIGNAL ;
		DIRECTION INPUT ;
		SHAPE ABUTMENT ;
		PORT
			 LAYER M2 ;
			RECT 0.0098 33.7318 0.0481 33.7694 ;
		END

		ANTENNAGATEAREA 0.00027817 ;
		ANTENNADIFFAREA 0.00194719 ;
		ANTENNAPARTIALMETALAREA 0.00195671 ;
	END TCENB

	PIN TDA[0]
		USE SIGNAL ;
		DIRECTION INPUT ;
		SHAPE ABUTMENT ;
		PORT
			 LAYER M2 ;
			RECT 0.0714 1.4808 0.1097 1.5184 ;
			 LAYER M3 ;
			RECT 0.0714 1.4808 0.1097 1.5812 ;
			 LAYER V2 ;
			RECT 0.0831 1.4929 0.098 1.5055 ;
		END

		ANTENNAGATEAREA 0.00027817 ;
		ANTENNADIFFAREA 0.00194719 ;
		ANTENNAPARTIALMETALAREA 0.00195671 ;
	END TDA[0]

	PIN TDA[10]
		USE SIGNAL ;
		DIRECTION INPUT ;
		SHAPE ABUTMENT ;
		PORT
			 LAYER M2 ;
			RECT 0.0714 17.2925 0.1097 17.3302 ;
			 LAYER M3 ;
			RECT 0.0714 17.2925 0.1097 17.3929 ;
			 LAYER V2 ;
			RECT 0.0831 17.3047 0.098 17.3173 ;
		END

		ANTENNAGATEAREA 0.00027817 ;
		ANTENNADIFFAREA 0.00194719 ;
		ANTENNAPARTIALMETALAREA 0.00195671 ;
	END TDA[10]

	PIN TDA[11]
		USE SIGNAL ;
		DIRECTION INPUT ;
		SHAPE ABUTMENT ;
		PORT
			 LAYER M2 ;
			RECT 0.0714 18.8737 0.1097 18.9114 ;
			 LAYER M3 ;
			RECT 0.0714 18.8737 0.1097 18.9741 ;
			 LAYER V2 ;
			RECT 0.0831 18.8859 0.098 18.8984 ;
		END

		ANTENNAGATEAREA 0.00027817 ;
		ANTENNADIFFAREA 0.00194719 ;
		ANTENNAPARTIALMETALAREA 0.00195671 ;
	END TDA[11]

	PIN TDA[12]
		USE SIGNAL ;
		DIRECTION INPUT ;
		SHAPE ABUTMENT ;
		PORT
			 LAYER M2 ;
			RECT 0.0714 20.4549 0.1097 20.4925 ;
			 LAYER M3 ;
			RECT 0.0714 20.4549 0.1097 20.5553 ;
			 LAYER V2 ;
			RECT 0.0831 20.4671 0.098 20.4796 ;
		END

		ANTENNAGATEAREA 0.00027817 ;
		ANTENNADIFFAREA 0.00194719 ;
		ANTENNAPARTIALMETALAREA 0.00195671 ;
	END TDA[12]

	PIN TDA[13]
		USE SIGNAL ;
		DIRECTION INPUT ;
		SHAPE ABUTMENT ;
		PORT
			 LAYER M2 ;
			RECT 0.0714 22.0361 0.1097 22.0737 ;
			 LAYER M3 ;
			RECT 0.0714 22.0361 0.1097 22.1365 ;
			 LAYER V2 ;
			RECT 0.0831 22.0482 0.098 22.0608 ;
		END

		ANTENNAGATEAREA 0.00027817 ;
		ANTENNADIFFAREA 0.00194719 ;
		ANTENNAPARTIALMETALAREA 0.00195671 ;
	END TDA[13]

	PIN TDA[14]
		USE SIGNAL ;
		DIRECTION INPUT ;
		SHAPE ABUTMENT ;
		PORT
			 LAYER M2 ;
			RECT 0.0714 23.6173 0.1097 23.6549 ;
			 LAYER M3 ;
			RECT 0.0714 23.6173 0.1097 23.7176 ;
			 LAYER V2 ;
			RECT 0.0831 23.6294 0.098 23.642 ;
		END

		ANTENNAGATEAREA 0.00027817 ;
		ANTENNADIFFAREA 0.00194719 ;
		ANTENNAPARTIALMETALAREA 0.00195671 ;
	END TDA[14]

	PIN TDA[15]
		USE SIGNAL ;
		DIRECTION INPUT ;
		SHAPE ABUTMENT ;
		PORT
			 LAYER M2 ;
			RECT 0.0714 25.1984 0.1097 25.2361 ;
			 LAYER M3 ;
			RECT 0.0714 25.1984 0.1097 25.2988 ;
			 LAYER V2 ;
			RECT 0.0831 25.2106 0.098 25.2231 ;
		END

		ANTENNAGATEAREA 0.00027817 ;
		ANTENNADIFFAREA 0.00194719 ;
		ANTENNAPARTIALMETALAREA 0.00195671 ;
	END TDA[15]

	PIN TDA[16]
		USE SIGNAL ;
		DIRECTION INPUT ;
		SHAPE ABUTMENT ;
		PORT
			 LAYER M2 ;
			RECT 0.0714 36.411 0.1097 36.4486 ;
			 LAYER M3 ;
			RECT 0.0714 36.3482 0.1097 36.4486 ;
			 LAYER V2 ;
			RECT 0.0831 36.4239 0.098 36.4365 ;
		END

		ANTENNAGATEAREA 0.00027817 ;
		ANTENNADIFFAREA 0.00194719 ;
		ANTENNAPARTIALMETALAREA 0.00195671 ;
	END TDA[16]

	PIN TDA[17]
		USE SIGNAL ;
		DIRECTION INPUT ;
		SHAPE ABUTMENT ;
		PORT
			 LAYER M2 ;
			RECT 0.0714 37.9922 0.1097 38.0298 ;
			 LAYER M3 ;
			RECT 0.0714 37.9294 0.1097 38.0298 ;
			 LAYER V2 ;
			RECT 0.0831 38.0051 0.098 38.0176 ;
		END

		ANTENNAGATEAREA 0.00027817 ;
		ANTENNADIFFAREA 0.00194719 ;
		ANTENNAPARTIALMETALAREA 0.00195671 ;
	END TDA[17]

	PIN TDA[18]
		USE SIGNAL ;
		DIRECTION INPUT ;
		SHAPE ABUTMENT ;
		PORT
			 LAYER M2 ;
			RECT 0.0714 39.5733 0.1097 39.611 ;
			 LAYER M3 ;
			RECT 0.0714 39.5106 0.1097 39.611 ;
			 LAYER V2 ;
			RECT 0.0831 39.5863 0.098 39.5988 ;
		END

		ANTENNAGATEAREA 0.00027817 ;
		ANTENNADIFFAREA 0.00194719 ;
		ANTENNAPARTIALMETALAREA 0.00195671 ;
	END TDA[18]

	PIN TDA[19]
		USE SIGNAL ;
		DIRECTION INPUT ;
		SHAPE ABUTMENT ;
		PORT
			 LAYER M2 ;
			RECT 0.0714 41.1545 0.1097 41.1922 ;
			 LAYER M3 ;
			RECT 0.0714 41.0918 0.1097 41.1922 ;
			 LAYER V2 ;
			RECT 0.0831 41.1675 0.098 41.18 ;
		END

		ANTENNAGATEAREA 0.00027817 ;
		ANTENNADIFFAREA 0.00194719 ;
		ANTENNAPARTIALMETALAREA 0.00195671 ;
	END TDA[19]

	PIN TDA[1]
		USE SIGNAL ;
		DIRECTION INPUT ;
		SHAPE ABUTMENT ;
		PORT
			 LAYER M2 ;
			RECT 0.0714 3.062 0.1097 3.0996 ;
			 LAYER M3 ;
			RECT 0.0714 3.062 0.1097 3.1624 ;
			 LAYER V2 ;
			RECT 0.0831 3.0741 0.098 3.0867 ;
		END

		ANTENNAGATEAREA 0.00027817 ;
		ANTENNADIFFAREA 0.00194719 ;
		ANTENNAPARTIALMETALAREA 0.00195671 ;
	END TDA[1]

	PIN TDA[20]
		USE SIGNAL ;
		DIRECTION INPUT ;
		SHAPE ABUTMENT ;
		PORT
			 LAYER M2 ;
			RECT 0.0714 42.7357 0.1097 42.7733 ;
			 LAYER M3 ;
			RECT 0.0714 42.6729 0.1097 42.7733 ;
			 LAYER V2 ;
			RECT 0.0831 42.7486 0.098 42.7612 ;
		END

		ANTENNAGATEAREA 0.00027817 ;
		ANTENNADIFFAREA 0.00194719 ;
		ANTENNAPARTIALMETALAREA 0.00195671 ;
	END TDA[20]

	PIN TDA[21]
		USE SIGNAL ;
		DIRECTION INPUT ;
		SHAPE ABUTMENT ;
		PORT
			 LAYER M2 ;
			RECT 0.0714 44.3169 0.1097 44.3545 ;
			 LAYER M3 ;
			RECT 0.0714 44.2541 0.1097 44.3545 ;
			 LAYER V2 ;
			RECT 0.0831 44.3298 0.098 44.3424 ;
		END

		ANTENNAGATEAREA 0.00027817 ;
		ANTENNADIFFAREA 0.00194719 ;
		ANTENNAPARTIALMETALAREA 0.00195671 ;
	END TDA[21]

	PIN TDA[22]
		USE SIGNAL ;
		DIRECTION INPUT ;
		SHAPE ABUTMENT ;
		PORT
			 LAYER M2 ;
			RECT 0.0714 45.898 0.1097 45.9357 ;
			 LAYER M3 ;
			RECT 0.0714 45.8353 0.1097 45.9357 ;
			 LAYER V2 ;
			RECT 0.0831 45.911 0.098 45.9235 ;
		END

		ANTENNAGATEAREA 0.00027817 ;
		ANTENNADIFFAREA 0.00194719 ;
		ANTENNAPARTIALMETALAREA 0.00195671 ;
	END TDA[22]

	PIN TDA[23]
		USE SIGNAL ;
		DIRECTION INPUT ;
		SHAPE ABUTMENT ;
		PORT
			 LAYER M2 ;
			RECT 0.0714 47.4792 0.1097 47.5169 ;
			 LAYER M3 ;
			RECT 0.0714 47.4165 0.1097 47.5169 ;
			 LAYER V2 ;
			RECT 0.0831 47.4922 0.098 47.5047 ;
		END

		ANTENNAGATEAREA 0.00027817 ;
		ANTENNADIFFAREA 0.00194719 ;
		ANTENNAPARTIALMETALAREA 0.00195671 ;
	END TDA[23]

	PIN TDA[24]
		USE SIGNAL ;
		DIRECTION INPUT ;
		SHAPE ABUTMENT ;
		PORT
			 LAYER M2 ;
			RECT 0.0714 49.0604 0.1097 49.098 ;
			 LAYER M3 ;
			RECT 0.0714 48.9976 0.1097 49.098 ;
			 LAYER V2 ;
			RECT 0.0831 49.0733 0.098 49.0859 ;
		END

		ANTENNAGATEAREA 0.00027817 ;
		ANTENNADIFFAREA 0.00194719 ;
		ANTENNAPARTIALMETALAREA 0.00195671 ;
	END TDA[24]

	PIN TDA[25]
		USE SIGNAL ;
		DIRECTION INPUT ;
		SHAPE ABUTMENT ;
		PORT
			 LAYER M2 ;
			RECT 0.0714 50.6416 0.1097 50.6792 ;
			 LAYER M3 ;
			RECT 0.0714 50.5788 0.1097 50.6792 ;
			 LAYER V2 ;
			RECT 0.0831 50.6545 0.098 50.6671 ;
		END

		ANTENNAGATEAREA 0.00027817 ;
		ANTENNADIFFAREA 0.00194719 ;
		ANTENNAPARTIALMETALAREA 0.00195671 ;
	END TDA[25]

	PIN TDA[26]
		USE SIGNAL ;
		DIRECTION INPUT ;
		SHAPE ABUTMENT ;
		PORT
			 LAYER M2 ;
			RECT 0.0714 52.2227 0.1097 52.2604 ;
			 LAYER M3 ;
			RECT 0.0714 52.16 0.1097 52.2604 ;
			 LAYER V2 ;
			RECT 0.0831 52.2357 0.098 52.2482 ;
		END

		ANTENNAGATEAREA 0.00027817 ;
		ANTENNADIFFAREA 0.00194719 ;
		ANTENNAPARTIALMETALAREA 0.00195671 ;
	END TDA[26]

	PIN TDA[27]
		USE SIGNAL ;
		DIRECTION INPUT ;
		SHAPE ABUTMENT ;
		PORT
			 LAYER M2 ;
			RECT 0.0714 53.8039 0.1097 53.8416 ;
			 LAYER M3 ;
			RECT 0.0714 53.7412 0.1097 53.8416 ;
			 LAYER V2 ;
			RECT 0.0831 53.8169 0.098 53.8294 ;
		END

		ANTENNAGATEAREA 0.00027817 ;
		ANTENNADIFFAREA 0.00194719 ;
		ANTENNAPARTIALMETALAREA 0.00195671 ;
	END TDA[27]

	PIN TDA[28]
		USE SIGNAL ;
		DIRECTION INPUT ;
		SHAPE ABUTMENT ;
		PORT
			 LAYER M2 ;
			RECT 0.0714 55.3851 0.1097 55.4227 ;
			 LAYER M3 ;
			RECT 0.0714 55.3224 0.1097 55.4227 ;
			 LAYER V2 ;
			RECT 0.0831 55.398 0.098 55.4106 ;
		END

		ANTENNAGATEAREA 0.00027817 ;
		ANTENNADIFFAREA 0.00194719 ;
		ANTENNAPARTIALMETALAREA 0.00195671 ;
	END TDA[28]

	PIN TDA[29]
		USE SIGNAL ;
		DIRECTION INPUT ;
		SHAPE ABUTMENT ;
		PORT
			 LAYER M2 ;
			RECT 0.0714 56.9663 0.1097 57.0039 ;
			 LAYER M3 ;
			RECT 0.0714 56.9035 0.1097 57.0039 ;
			 LAYER V2 ;
			RECT 0.0831 56.9792 0.098 56.9918 ;
		END

		ANTENNAGATEAREA 0.00027817 ;
		ANTENNADIFFAREA 0.00194719 ;
		ANTENNAPARTIALMETALAREA 0.00195671 ;
	END TDA[29]

	PIN TDA[2]
		USE SIGNAL ;
		DIRECTION INPUT ;
		SHAPE ABUTMENT ;
		PORT
			 LAYER M2 ;
			RECT 0.0714 4.6431 0.1097 4.6808 ;
			 LAYER M3 ;
			RECT 0.0714 4.6431 0.1097 4.7435 ;
			 LAYER V2 ;
			RECT 0.0831 4.6553 0.098 4.6678 ;
		END

		ANTENNAGATEAREA 0.00027817 ;
		ANTENNADIFFAREA 0.00194719 ;
		ANTENNAPARTIALMETALAREA 0.00195671 ;
	END TDA[2]

	PIN TDA[30]
		USE SIGNAL ;
		DIRECTION INPUT ;
		SHAPE ABUTMENT ;
		PORT
			 LAYER M2 ;
			RECT 0.0714 58.5475 0.1097 58.5851 ;
			 LAYER M3 ;
			RECT 0.0714 58.4847 0.1097 58.5851 ;
			 LAYER V2 ;
			RECT 0.0831 58.5604 0.098 58.5729 ;
		END

		ANTENNAGATEAREA 0.00027817 ;
		ANTENNADIFFAREA 0.00194719 ;
		ANTENNAPARTIALMETALAREA 0.00195671 ;
	END TDA[30]

	PIN TDA[31]
		USE SIGNAL ;
		DIRECTION INPUT ;
		SHAPE ABUTMENT ;
		PORT
			 LAYER M2 ;
			RECT 0.0714 60.1286 0.1097 60.1663 ;
			 LAYER M3 ;
			RECT 0.0714 60.0659 0.1097 60.1663 ;
			 LAYER V2 ;
			RECT 0.0831 60.1416 0.098 60.1541 ;
		END

		ANTENNAGATEAREA 0.00027817 ;
		ANTENNADIFFAREA 0.00194719 ;
		ANTENNAPARTIALMETALAREA 0.00195671 ;
	END TDA[31]

	PIN TDA[32]
		USE SIGNAL ;
		DIRECTION INPUT ;
		SHAPE ABUTMENT ;
		PORT
			 LAYER M2 ;
			RECT 0.0714 61.7098 0.1097 61.7475 ;
			 LAYER M3 ;
			RECT 0.0714 61.6471 0.1097 61.7475 ;
			 LAYER V2 ;
			RECT 0.0831 61.7227 0.098 61.7353 ;
		END

		ANTENNAGATEAREA 0.00027817 ;
		ANTENNADIFFAREA 0.00194719 ;
		ANTENNAPARTIALMETALAREA 0.00195671 ;
	END TDA[32]

	PIN TDA[3]
		USE SIGNAL ;
		DIRECTION INPUT ;
		SHAPE ABUTMENT ;
		PORT
			 LAYER M2 ;
			RECT 0.0714 6.2243 0.1097 6.262 ;
			 LAYER M3 ;
			RECT 0.0714 6.2243 0.1097 6.3247 ;
			 LAYER V2 ;
			RECT 0.0831 6.2365 0.098 6.249 ;
		END

		ANTENNAGATEAREA 0.00027817 ;
		ANTENNADIFFAREA 0.00194719 ;
		ANTENNAPARTIALMETALAREA 0.00195671 ;
	END TDA[3]

	PIN TDA[4]
		USE SIGNAL ;
		DIRECTION INPUT ;
		SHAPE ABUTMENT ;
		PORT
			 LAYER M2 ;
			RECT 0.0714 7.8055 0.1097 7.8431 ;
			 LAYER M3 ;
			RECT 0.0714 7.8055 0.1097 7.9059 ;
			 LAYER V2 ;
			RECT 0.0831 7.8176 0.098 7.8302 ;
		END

		ANTENNAGATEAREA 0.00027817 ;
		ANTENNADIFFAREA 0.00194719 ;
		ANTENNAPARTIALMETALAREA 0.00195671 ;
	END TDA[4]

	PIN TDA[5]
		USE SIGNAL ;
		DIRECTION INPUT ;
		SHAPE ABUTMENT ;
		PORT
			 LAYER M2 ;
			RECT 0.0714 9.3867 0.1097 9.4243 ;
			 LAYER M3 ;
			RECT 0.0714 9.3867 0.1097 9.4871 ;
			 LAYER V2 ;
			RECT 0.0831 9.3988 0.098 9.4114 ;
		END

		ANTENNAGATEAREA 0.00027817 ;
		ANTENNADIFFAREA 0.00194719 ;
		ANTENNAPARTIALMETALAREA 0.00195671 ;
	END TDA[5]

	PIN TDA[6]
		USE SIGNAL ;
		DIRECTION INPUT ;
		SHAPE ABUTMENT ;
		PORT
			 LAYER M2 ;
			RECT 0.0714 10.9678 0.1097 11.0055 ;
			 LAYER M3 ;
			RECT 0.0714 10.9678 0.1097 11.0682 ;
			 LAYER V2 ;
			RECT 0.0831 10.98 0.098 10.9925 ;
		END

		ANTENNAGATEAREA 0.00027817 ;
		ANTENNADIFFAREA 0.00194719 ;
		ANTENNAPARTIALMETALAREA 0.00195671 ;
	END TDA[6]

	PIN TDA[7]
		USE SIGNAL ;
		DIRECTION INPUT ;
		SHAPE ABUTMENT ;
		PORT
			 LAYER M2 ;
			RECT 0.0714 12.549 0.1097 12.5867 ;
			 LAYER M3 ;
			RECT 0.0714 12.549 0.1097 12.6494 ;
			 LAYER V2 ;
			RECT 0.0831 12.5612 0.098 12.5737 ;
		END

		ANTENNAGATEAREA 0.00027817 ;
		ANTENNADIFFAREA 0.00194719 ;
		ANTENNAPARTIALMETALAREA 0.00195671 ;
	END TDA[7]

	PIN TDA[8]
		USE SIGNAL ;
		DIRECTION INPUT ;
		SHAPE ABUTMENT ;
		PORT
			 LAYER M2 ;
			RECT 0.0714 14.1302 0.1097 14.1678 ;
			 LAYER M3 ;
			RECT 0.0714 14.1302 0.1097 14.2306 ;
			 LAYER V2 ;
			RECT 0.0831 14.1424 0.098 14.1549 ;
		END

		ANTENNAGATEAREA 0.00027817 ;
		ANTENNADIFFAREA 0.00194719 ;
		ANTENNAPARTIALMETALAREA 0.00195671 ;
	END TDA[8]

	PIN TDA[9]
		USE SIGNAL ;
		DIRECTION INPUT ;
		SHAPE ABUTMENT ;
		PORT
			 LAYER M2 ;
			RECT 0.0714 15.7114 0.1097 15.749 ;
			 LAYER M3 ;
			RECT 0.0714 15.7114 0.1097 15.8118 ;
			 LAYER V2 ;
			RECT 0.0831 15.7235 0.098 15.7361 ;
		END

		ANTENNAGATEAREA 0.00027817 ;
		ANTENNADIFFAREA 0.00194719 ;
		ANTENNAPARTIALMETALAREA 0.00195671 ;
	END TDA[9]

	PIN TDB[0]
		USE SIGNAL ;
		DIRECTION INPUT ;
		SHAPE ABUTMENT ;
		PORT
			 LAYER M2 ;
			RECT 0.0098 1.6941 0.0481 1.7318 ;
		END

		ANTENNAGATEAREA 0.00027817 ;
		ANTENNADIFFAREA 0.00194719 ;
		ANTENNAPARTIALMETALAREA 0.00195671 ;
	END TDB[0]

	PIN TDB[10]
		USE SIGNAL ;
		DIRECTION INPUT ;
		SHAPE ABUTMENT ;
		PORT
			 LAYER M2 ;
			RECT 0.0098 17.5059 0.0481 17.5435 ;
		END

		ANTENNAGATEAREA 0.00027817 ;
		ANTENNADIFFAREA 0.00194719 ;
		ANTENNAPARTIALMETALAREA 0.00195671 ;
	END TDB[10]

	PIN TDB[11]
		USE SIGNAL ;
		DIRECTION INPUT ;
		SHAPE ABUTMENT ;
		PORT
			 LAYER M2 ;
			RECT 0.0098 19.0871 0.0481 19.1247 ;
		END

		ANTENNAGATEAREA 0.00027817 ;
		ANTENNADIFFAREA 0.00194719 ;
		ANTENNAPARTIALMETALAREA 0.00195671 ;
	END TDB[11]

	PIN TDB[12]
		USE SIGNAL ;
		DIRECTION INPUT ;
		SHAPE ABUTMENT ;
		PORT
			 LAYER M2 ;
			RECT 0.0098 20.6682 0.0481 20.7059 ;
		END

		ANTENNAGATEAREA 0.00027817 ;
		ANTENNADIFFAREA 0.00194719 ;
		ANTENNAPARTIALMETALAREA 0.00195671 ;
	END TDB[12]

	PIN TDB[13]
		USE SIGNAL ;
		DIRECTION INPUT ;
		SHAPE ABUTMENT ;
		PORT
			 LAYER M2 ;
			RECT 0.0098 22.2494 0.0481 22.2871 ;
		END

		ANTENNAGATEAREA 0.00027817 ;
		ANTENNADIFFAREA 0.00194719 ;
		ANTENNAPARTIALMETALAREA 0.00195671 ;
	END TDB[13]

	PIN TDB[14]
		USE SIGNAL ;
		DIRECTION INPUT ;
		SHAPE ABUTMENT ;
		PORT
			 LAYER M2 ;
			RECT 0.0098 23.8306 0.0481 23.8682 ;
		END

		ANTENNAGATEAREA 0.00027817 ;
		ANTENNADIFFAREA 0.00194719 ;
		ANTENNAPARTIALMETALAREA 0.00195671 ;
	END TDB[14]

	PIN TDB[15]
		USE SIGNAL ;
		DIRECTION INPUT ;
		SHAPE ABUTMENT ;
		PORT
			 LAYER M2 ;
			RECT 0.0098 25.4118 0.0481 25.4494 ;
		END

		ANTENNAGATEAREA 0.00027817 ;
		ANTENNADIFFAREA 0.00194719 ;
		ANTENNAPARTIALMETALAREA 0.00195671 ;
	END TDB[15]

	PIN TDB[16]
		USE SIGNAL ;
		DIRECTION INPUT ;
		SHAPE ABUTMENT ;
		PORT
			 LAYER M2 ;
			RECT 0.0098 36.1976 0.0481 36.2353 ;
		END

		ANTENNAGATEAREA 0.00027817 ;
		ANTENNADIFFAREA 0.00194719 ;
		ANTENNAPARTIALMETALAREA 0.00195671 ;
	END TDB[16]

	PIN TDB[17]
		USE SIGNAL ;
		DIRECTION INPUT ;
		SHAPE ABUTMENT ;
		PORT
			 LAYER M2 ;
			RECT 0.0098 37.7788 0.0481 37.8165 ;
		END

		ANTENNAGATEAREA 0.00027817 ;
		ANTENNADIFFAREA 0.00194719 ;
		ANTENNAPARTIALMETALAREA 0.00195671 ;
	END TDB[17]

	PIN TDB[18]
		USE SIGNAL ;
		DIRECTION INPUT ;
		SHAPE ABUTMENT ;
		PORT
			 LAYER M2 ;
			RECT 0.0098 39.36 0.0481 39.3976 ;
		END

		ANTENNAGATEAREA 0.00027817 ;
		ANTENNADIFFAREA 0.00194719 ;
		ANTENNAPARTIALMETALAREA 0.00195671 ;
	END TDB[18]

	PIN TDB[19]
		USE SIGNAL ;
		DIRECTION INPUT ;
		SHAPE ABUTMENT ;
		PORT
			 LAYER M2 ;
			RECT 0.0098 40.9412 0.0481 40.9788 ;
		END

		ANTENNAGATEAREA 0.00027817 ;
		ANTENNADIFFAREA 0.00194719 ;
		ANTENNAPARTIALMETALAREA 0.00195671 ;
	END TDB[19]

	PIN TDB[1]
		USE SIGNAL ;
		DIRECTION INPUT ;
		SHAPE ABUTMENT ;
		PORT
			 LAYER M2 ;
			RECT 0.0098 3.2753 0.0481 3.3129 ;
		END

		ANTENNAGATEAREA 0.00027817 ;
		ANTENNADIFFAREA 0.00194719 ;
		ANTENNAPARTIALMETALAREA 0.00195671 ;
	END TDB[1]

	PIN TDB[20]
		USE SIGNAL ;
		DIRECTION INPUT ;
		SHAPE ABUTMENT ;
		PORT
			 LAYER M2 ;
			RECT 0.0098 42.5224 0.0481 42.56 ;
		END

		ANTENNAGATEAREA 0.00027817 ;
		ANTENNADIFFAREA 0.00194719 ;
		ANTENNAPARTIALMETALAREA 0.00195671 ;
	END TDB[20]

	PIN TDB[21]
		USE SIGNAL ;
		DIRECTION INPUT ;
		SHAPE ABUTMENT ;
		PORT
			 LAYER M2 ;
			RECT 0.0098 44.1035 0.0481 44.1412 ;
		END

		ANTENNAGATEAREA 0.00027817 ;
		ANTENNADIFFAREA 0.00194719 ;
		ANTENNAPARTIALMETALAREA 0.00195671 ;
	END TDB[21]

	PIN TDB[22]
		USE SIGNAL ;
		DIRECTION INPUT ;
		SHAPE ABUTMENT ;
		PORT
			 LAYER M2 ;
			RECT 0.0098 45.6847 0.0481 45.7224 ;
		END

		ANTENNAGATEAREA 0.00027817 ;
		ANTENNADIFFAREA 0.00194719 ;
		ANTENNAPARTIALMETALAREA 0.00195671 ;
	END TDB[22]

	PIN TDB[23]
		USE SIGNAL ;
		DIRECTION INPUT ;
		SHAPE ABUTMENT ;
		PORT
			 LAYER M2 ;
			RECT 0.0098 47.2659 0.0481 47.3035 ;
		END

		ANTENNAGATEAREA 0.00027817 ;
		ANTENNADIFFAREA 0.00194719 ;
		ANTENNAPARTIALMETALAREA 0.00195671 ;
	END TDB[23]

	PIN TDB[24]
		USE SIGNAL ;
		DIRECTION INPUT ;
		SHAPE ABUTMENT ;
		PORT
			 LAYER M2 ;
			RECT 0.0098 48.8471 0.0481 48.8847 ;
		END

		ANTENNAGATEAREA 0.00027817 ;
		ANTENNADIFFAREA 0.00194719 ;
		ANTENNAPARTIALMETALAREA 0.00195671 ;
	END TDB[24]

	PIN TDB[25]
		USE SIGNAL ;
		DIRECTION INPUT ;
		SHAPE ABUTMENT ;
		PORT
			 LAYER M2 ;
			RECT 0.0098 50.4282 0.0481 50.4659 ;
		END

		ANTENNAGATEAREA 0.00027817 ;
		ANTENNADIFFAREA 0.00194719 ;
		ANTENNAPARTIALMETALAREA 0.00195671 ;
	END TDB[25]

	PIN TDB[26]
		USE SIGNAL ;
		DIRECTION INPUT ;
		SHAPE ABUTMENT ;
		PORT
			 LAYER M2 ;
			RECT 0.0098 52.0094 0.0481 52.0471 ;
		END

		ANTENNAGATEAREA 0.00027817 ;
		ANTENNADIFFAREA 0.00194719 ;
		ANTENNAPARTIALMETALAREA 0.00195671 ;
	END TDB[26]

	PIN TDB[27]
		USE SIGNAL ;
		DIRECTION INPUT ;
		SHAPE ABUTMENT ;
		PORT
			 LAYER M2 ;
			RECT 0.0098 53.5906 0.0481 53.6282 ;
		END

		ANTENNAGATEAREA 0.00027817 ;
		ANTENNADIFFAREA 0.00194719 ;
		ANTENNAPARTIALMETALAREA 0.00195671 ;
	END TDB[27]

	PIN TDB[28]
		USE SIGNAL ;
		DIRECTION INPUT ;
		SHAPE ABUTMENT ;
		PORT
			 LAYER M2 ;
			RECT 0.0098 55.1718 0.0481 55.2094 ;
		END

		ANTENNAGATEAREA 0.00027817 ;
		ANTENNADIFFAREA 0.00194719 ;
		ANTENNAPARTIALMETALAREA 0.00195671 ;
	END TDB[28]

	PIN TDB[29]
		USE SIGNAL ;
		DIRECTION INPUT ;
		SHAPE ABUTMENT ;
		PORT
			 LAYER M2 ;
			RECT 0.0098 56.7529 0.0481 56.7906 ;
		END

		ANTENNAGATEAREA 0.00027817 ;
		ANTENNADIFFAREA 0.00194719 ;
		ANTENNAPARTIALMETALAREA 0.00195671 ;
	END TDB[29]

	PIN TDB[2]
		USE SIGNAL ;
		DIRECTION INPUT ;
		SHAPE ABUTMENT ;
		PORT
			 LAYER M2 ;
			RECT 0.0098 4.8565 0.0481 4.8941 ;
		END

		ANTENNAGATEAREA 0.00027817 ;
		ANTENNADIFFAREA 0.00194719 ;
		ANTENNAPARTIALMETALAREA 0.00195671 ;
	END TDB[2]

	PIN TDB[30]
		USE SIGNAL ;
		DIRECTION INPUT ;
		SHAPE ABUTMENT ;
		PORT
			 LAYER M2 ;
			RECT 0.0098 58.3341 0.0481 58.3718 ;
		END

		ANTENNAGATEAREA 0.00027817 ;
		ANTENNADIFFAREA 0.00194719 ;
		ANTENNAPARTIALMETALAREA 0.00195671 ;
	END TDB[30]

	PIN TDB[31]
		USE SIGNAL ;
		DIRECTION INPUT ;
		SHAPE ABUTMENT ;
		PORT
			 LAYER M2 ;
			RECT 0.0098 59.9153 0.0481 59.9529 ;
		END

		ANTENNAGATEAREA 0.00027817 ;
		ANTENNADIFFAREA 0.00194719 ;
		ANTENNAPARTIALMETALAREA 0.00195671 ;
	END TDB[31]

	PIN TDB[32]
		USE SIGNAL ;
		DIRECTION INPUT ;
		SHAPE ABUTMENT ;
		PORT
			 LAYER M2 ;
			RECT 0.0098 61.4965 0.0481 61.5341 ;
		END

		ANTENNAGATEAREA 0.00027817 ;
		ANTENNADIFFAREA 0.00194719 ;
		ANTENNAPARTIALMETALAREA 0.00195671 ;
	END TDB[32]

	PIN TDB[3]
		USE SIGNAL ;
		DIRECTION INPUT ;
		SHAPE ABUTMENT ;
		PORT
			 LAYER M2 ;
			RECT 0.0098 6.4376 0.0481 6.4753 ;
		END

		ANTENNAGATEAREA 0.00027817 ;
		ANTENNADIFFAREA 0.00194719 ;
		ANTENNAPARTIALMETALAREA 0.00195671 ;
	END TDB[3]

	PIN TDB[4]
		USE SIGNAL ;
		DIRECTION INPUT ;
		SHAPE ABUTMENT ;
		PORT
			 LAYER M2 ;
			RECT 0.0098 8.0188 0.0481 8.0565 ;
		END

		ANTENNAGATEAREA 0.00027817 ;
		ANTENNADIFFAREA 0.00194719 ;
		ANTENNAPARTIALMETALAREA 0.00195671 ;
	END TDB[4]

	PIN TDB[5]
		USE SIGNAL ;
		DIRECTION INPUT ;
		SHAPE ABUTMENT ;
		PORT
			 LAYER M2 ;
			RECT 0.0098 9.6 0.0481 9.6376 ;
		END

		ANTENNAGATEAREA 0.00027817 ;
		ANTENNADIFFAREA 0.00194719 ;
		ANTENNAPARTIALMETALAREA 0.00195671 ;
	END TDB[5]

	PIN TDB[6]
		USE SIGNAL ;
		DIRECTION INPUT ;
		SHAPE ABUTMENT ;
		PORT
			 LAYER M2 ;
			RECT 0.0098 11.1812 0.0481 11.2188 ;
		END

		ANTENNAGATEAREA 0.00027817 ;
		ANTENNADIFFAREA 0.00194719 ;
		ANTENNAPARTIALMETALAREA 0.00195671 ;
	END TDB[6]

	PIN TDB[7]
		USE SIGNAL ;
		DIRECTION INPUT ;
		SHAPE ABUTMENT ;
		PORT
			 LAYER M2 ;
			RECT 0.0098 12.7624 0.0481 12.8 ;
		END

		ANTENNAGATEAREA 0.00027817 ;
		ANTENNADIFFAREA 0.00194719 ;
		ANTENNAPARTIALMETALAREA 0.00195671 ;
	END TDB[7]

	PIN TDB[8]
		USE SIGNAL ;
		DIRECTION INPUT ;
		SHAPE ABUTMENT ;
		PORT
			 LAYER M2 ;
			RECT 0.0098 14.3435 0.0481 14.3812 ;
		END

		ANTENNAGATEAREA 0.00027817 ;
		ANTENNADIFFAREA 0.00194719 ;
		ANTENNAPARTIALMETALAREA 0.00195671 ;
	END TDB[8]

	PIN TDB[9]
		USE SIGNAL ;
		DIRECTION INPUT ;
		SHAPE ABUTMENT ;
		PORT
			 LAYER M2 ;
			RECT 0.0098 15.9247 0.0481 15.9624 ;
		END

		ANTENNAGATEAREA 0.00027817 ;
		ANTENNADIFFAREA 0.00194719 ;
		ANTENNAPARTIALMETALAREA 0.00195671 ;
	END TDB[9]

	PIN TEN
		USE SIGNAL ;
		DIRECTION INPUT ;
		SHAPE ABUTMENT ;
		PORT
			 LAYER M2 ;
			RECT 0.0098 29.1388 0.0481 29.1765 ;
		END

		ANTENNAGATEAREA 0.00027817 ;
		ANTENNADIFFAREA 0.00194719 ;
		ANTENNAPARTIALMETALAREA 0.00195671 ;
	END TEN

	PIN TGWENA
		USE SIGNAL ;
		DIRECTION INPUT ;
		SHAPE ABUTMENT ;
		PORT
			 LAYER M2 ;
			RECT 0.0714 28.3733 0.1097 28.411 ;
			 LAYER M3 ;
			RECT 0.0714 28.3733 0.1097 28.4737 ;
			 LAYER V2 ;
			RECT 0.0831 28.3855 0.098 28.398 ;
		END

		ANTENNAGATEAREA 0.00027817 ;
		ANTENNADIFFAREA 0.00194719 ;
		ANTENNAPARTIALMETALAREA 0.00195671 ;
	END TGWENA

	PIN TGWENB
		USE SIGNAL ;
		DIRECTION INPUT ;
		SHAPE ABUTMENT ;
		PORT
			 LAYER M2 ;
			RECT 0.0714 27.1686 0.1097 27.2063 ;
			 LAYER M3 ;
			RECT 0.0714 27.1686 0.1097 27.269 ;
			 LAYER V2 ;
			RECT 0.0831 27.1808 0.098 27.1933 ;
		END

		ANTENNAGATEAREA 0.00027817 ;
		ANTENNADIFFAREA 0.00194719 ;
		ANTENNAPARTIALMETALAREA 0.00195671 ;
	END TGWENB

	PIN TWENA[0]
		USE SIGNAL ;
		DIRECTION INPUT ;
		SHAPE ABUTMENT ;
		PORT
			 LAYER M2 ;
			RECT 0.0714 1.2424 0.1097 1.28 ;
			 LAYER M3 ;
			RECT 0.0714 1.1796 0.1097 1.28 ;
			 LAYER V2 ;
			RECT 0.0831 1.2553 0.098 1.2678 ;
		END

		ANTENNAGATEAREA 0.00027817 ;
		ANTENNADIFFAREA 0.00194719 ;
		ANTENNAPARTIALMETALAREA 0.00195671 ;
	END TWENA[0]

	PIN TWENA[10]
		USE SIGNAL ;
		DIRECTION INPUT ;
		SHAPE ABUTMENT ;
		PORT
			 LAYER M2 ;
			RECT 0.0714 17.0541 0.1097 17.0918 ;
			 LAYER M3 ;
			RECT 0.0714 16.9914 0.1097 17.0918 ;
			 LAYER V2 ;
			RECT 0.0831 17.0671 0.098 17.0796 ;
		END

		ANTENNAGATEAREA 0.00027817 ;
		ANTENNADIFFAREA 0.00194719 ;
		ANTENNAPARTIALMETALAREA 0.00195671 ;
	END TWENA[10]

	PIN TWENA[11]
		USE SIGNAL ;
		DIRECTION INPUT ;
		SHAPE ABUTMENT ;
		PORT
			 LAYER M2 ;
			RECT 0.0714 18.6353 0.1097 18.6729 ;
			 LAYER M3 ;
			RECT 0.0714 18.5725 0.1097 18.6729 ;
			 LAYER V2 ;
			RECT 0.0831 18.6482 0.098 18.6608 ;
		END

		ANTENNAGATEAREA 0.00027817 ;
		ANTENNADIFFAREA 0.00194719 ;
		ANTENNAPARTIALMETALAREA 0.00195671 ;
	END TWENA[11]

	PIN TWENA[12]
		USE SIGNAL ;
		DIRECTION INPUT ;
		SHAPE ABUTMENT ;
		PORT
			 LAYER M2 ;
			RECT 0.0714 20.2165 0.1097 20.2541 ;
			 LAYER M3 ;
			RECT 0.0714 20.1537 0.1097 20.2541 ;
			 LAYER V2 ;
			RECT 0.0831 20.2294 0.098 20.242 ;
		END

		ANTENNAGATEAREA 0.00027817 ;
		ANTENNADIFFAREA 0.00194719 ;
		ANTENNAPARTIALMETALAREA 0.00195671 ;
	END TWENA[12]

	PIN TWENA[13]
		USE SIGNAL ;
		DIRECTION INPUT ;
		SHAPE ABUTMENT ;
		PORT
			 LAYER M2 ;
			RECT 0.0714 21.7976 0.1097 21.8353 ;
			 LAYER M3 ;
			RECT 0.0714 21.7349 0.1097 21.8353 ;
			 LAYER V2 ;
			RECT 0.0831 21.8106 0.098 21.8231 ;
		END

		ANTENNAGATEAREA 0.00027817 ;
		ANTENNADIFFAREA 0.00194719 ;
		ANTENNAPARTIALMETALAREA 0.00195671 ;
	END TWENA[13]

	PIN TWENA[14]
		USE SIGNAL ;
		DIRECTION INPUT ;
		SHAPE ABUTMENT ;
		PORT
			 LAYER M2 ;
			RECT 0.0714 23.3788 0.1097 23.4165 ;
			 LAYER M3 ;
			RECT 0.0714 23.3161 0.1097 23.4165 ;
			 LAYER V2 ;
			RECT 0.0831 23.3918 0.098 23.4043 ;
		END

		ANTENNAGATEAREA 0.00027817 ;
		ANTENNADIFFAREA 0.00194719 ;
		ANTENNAPARTIALMETALAREA 0.00195671 ;
	END TWENA[14]

	PIN TWENA[15]
		USE SIGNAL ;
		DIRECTION INPUT ;
		SHAPE ABUTMENT ;
		PORT
			 LAYER M2 ;
			RECT 0.0714 24.96 0.1097 24.9976 ;
			 LAYER M3 ;
			RECT 0.0714 24.8973 0.1097 24.9976 ;
			 LAYER V2 ;
			RECT 0.0831 24.9729 0.098 24.9855 ;
		END

		ANTENNAGATEAREA 0.00027817 ;
		ANTENNADIFFAREA 0.00194719 ;
		ANTENNAPARTIALMETALAREA 0.00195671 ;
	END TWENA[15]

	PIN TWENA[16]
		USE SIGNAL ;
		DIRECTION INPUT ;
		SHAPE ABUTMENT ;
		PORT
			 LAYER M2 ;
			RECT 0.0714 36.6494 0.1097 36.6871 ;
			 LAYER M3 ;
			RECT 0.0714 36.6494 0.1097 36.7498 ;
			 LAYER V2 ;
			RECT 0.0831 36.6616 0.098 36.6741 ;
		END

		ANTENNAGATEAREA 0.00027817 ;
		ANTENNADIFFAREA 0.00194719 ;
		ANTENNAPARTIALMETALAREA 0.00195671 ;
	END TWENA[16]

	PIN TWENA[17]
		USE SIGNAL ;
		DIRECTION INPUT ;
		SHAPE ABUTMENT ;
		PORT
			 LAYER M2 ;
			RECT 0.0714 38.2306 0.1097 38.2682 ;
			 LAYER M3 ;
			RECT 0.0714 38.2306 0.1097 38.331 ;
			 LAYER V2 ;
			RECT 0.0831 38.2427 0.098 38.2553 ;
		END

		ANTENNAGATEAREA 0.00027817 ;
		ANTENNADIFFAREA 0.00194719 ;
		ANTENNAPARTIALMETALAREA 0.00195671 ;
	END TWENA[17]

	PIN TWENA[18]
		USE SIGNAL ;
		DIRECTION INPUT ;
		SHAPE ABUTMENT ;
		PORT
			 LAYER M2 ;
			RECT 0.0714 39.8118 0.1097 39.8494 ;
			 LAYER M3 ;
			RECT 0.0714 39.8118 0.1097 39.9122 ;
			 LAYER V2 ;
			RECT 0.0831 39.8239 0.098 39.8365 ;
		END

		ANTENNAGATEAREA 0.00027817 ;
		ANTENNADIFFAREA 0.00194719 ;
		ANTENNAPARTIALMETALAREA 0.00195671 ;
	END TWENA[18]

	PIN TWENA[19]
		USE SIGNAL ;
		DIRECTION INPUT ;
		SHAPE ABUTMENT ;
		PORT
			 LAYER M2 ;
			RECT 0.0714 41.3929 0.1097 41.4306 ;
			 LAYER M3 ;
			RECT 0.0714 41.3929 0.1097 41.4933 ;
			 LAYER V2 ;
			RECT 0.0831 41.4051 0.098 41.4176 ;
		END

		ANTENNAGATEAREA 0.00027817 ;
		ANTENNADIFFAREA 0.00194719 ;
		ANTENNAPARTIALMETALAREA 0.00195671 ;
	END TWENA[19]

	PIN TWENA[1]
		USE SIGNAL ;
		DIRECTION INPUT ;
		SHAPE ABUTMENT ;
		PORT
			 LAYER M2 ;
			RECT 0.0714 2.8235 0.1097 2.8612 ;
			 LAYER M3 ;
			RECT 0.0714 2.7608 0.1097 2.8612 ;
			 LAYER V2 ;
			RECT 0.0831 2.8365 0.098 2.849 ;
		END

		ANTENNAGATEAREA 0.00027817 ;
		ANTENNADIFFAREA 0.00194719 ;
		ANTENNAPARTIALMETALAREA 0.00195671 ;
	END TWENA[1]

	PIN TWENA[20]
		USE SIGNAL ;
		DIRECTION INPUT ;
		SHAPE ABUTMENT ;
		PORT
			 LAYER M2 ;
			RECT 0.0714 42.9741 0.1097 43.0118 ;
			 LAYER M3 ;
			RECT 0.0714 42.9741 0.1097 43.0745 ;
			 LAYER V2 ;
			RECT 0.0831 42.9863 0.098 42.9988 ;
		END

		ANTENNAGATEAREA 0.00027817 ;
		ANTENNADIFFAREA 0.00194719 ;
		ANTENNAPARTIALMETALAREA 0.00195671 ;
	END TWENA[20]

	PIN TWENA[21]
		USE SIGNAL ;
		DIRECTION INPUT ;
		SHAPE ABUTMENT ;
		PORT
			 LAYER M2 ;
			RECT 0.0714 44.5553 0.1097 44.5929 ;
			 LAYER M3 ;
			RECT 0.0714 44.5553 0.1097 44.6557 ;
			 LAYER V2 ;
			RECT 0.0831 44.5675 0.098 44.58 ;
		END

		ANTENNAGATEAREA 0.00027817 ;
		ANTENNADIFFAREA 0.00194719 ;
		ANTENNAPARTIALMETALAREA 0.00195671 ;
	END TWENA[21]

	PIN TWENA[22]
		USE SIGNAL ;
		DIRECTION INPUT ;
		SHAPE ABUTMENT ;
		PORT
			 LAYER M2 ;
			RECT 0.0714 46.1365 0.1097 46.1741 ;
			 LAYER M3 ;
			RECT 0.0714 46.1365 0.1097 46.2369 ;
			 LAYER V2 ;
			RECT 0.0831 46.1486 0.098 46.1612 ;
		END

		ANTENNAGATEAREA 0.00027817 ;
		ANTENNADIFFAREA 0.00194719 ;
		ANTENNAPARTIALMETALAREA 0.00195671 ;
	END TWENA[22]

	PIN TWENA[23]
		USE SIGNAL ;
		DIRECTION INPUT ;
		SHAPE ABUTMENT ;
		PORT
			 LAYER M2 ;
			RECT 0.0714 47.7176 0.1097 47.7553 ;
			 LAYER M3 ;
			RECT 0.0714 47.7176 0.1097 47.818 ;
			 LAYER V2 ;
			RECT 0.0831 47.7298 0.098 47.7424 ;
		END

		ANTENNAGATEAREA 0.00027817 ;
		ANTENNADIFFAREA 0.00194719 ;
		ANTENNAPARTIALMETALAREA 0.00195671 ;
	END TWENA[23]

	PIN TWENA[24]
		USE SIGNAL ;
		DIRECTION INPUT ;
		SHAPE ABUTMENT ;
		PORT
			 LAYER M2 ;
			RECT 0.0714 49.2988 0.1097 49.3365 ;
			 LAYER M3 ;
			RECT 0.0714 49.2988 0.1097 49.3992 ;
			 LAYER V2 ;
			RECT 0.0831 49.311 0.098 49.3235 ;
		END

		ANTENNAGATEAREA 0.00027817 ;
		ANTENNADIFFAREA 0.00194719 ;
		ANTENNAPARTIALMETALAREA 0.00195671 ;
	END TWENA[24]

	PIN TWENA[25]
		USE SIGNAL ;
		DIRECTION INPUT ;
		SHAPE ABUTMENT ;
		PORT
			 LAYER M2 ;
			RECT 0.0714 50.88 0.1097 50.9176 ;
			 LAYER M3 ;
			RECT 0.0714 50.88 0.1097 50.9804 ;
			 LAYER V2 ;
			RECT 0.0831 50.8922 0.098 50.9047 ;
		END

		ANTENNAGATEAREA 0.00027817 ;
		ANTENNADIFFAREA 0.00194719 ;
		ANTENNAPARTIALMETALAREA 0.00195671 ;
	END TWENA[25]

	PIN TWENA[26]
		USE SIGNAL ;
		DIRECTION INPUT ;
		SHAPE ABUTMENT ;
		PORT
			 LAYER M2 ;
			RECT 0.0714 52.4612 0.1097 52.4988 ;
			 LAYER M3 ;
			RECT 0.0714 52.4612 0.1097 52.5616 ;
			 LAYER V2 ;
			RECT 0.0831 52.4733 0.098 52.4859 ;
		END

		ANTENNAGATEAREA 0.00027817 ;
		ANTENNADIFFAREA 0.00194719 ;
		ANTENNAPARTIALMETALAREA 0.00195671 ;
	END TWENA[26]

	PIN TWENA[27]
		USE SIGNAL ;
		DIRECTION INPUT ;
		SHAPE ABUTMENT ;
		PORT
			 LAYER M2 ;
			RECT 0.0714 54.0424 0.1097 54.08 ;
			 LAYER M3 ;
			RECT 0.0714 54.0424 0.1097 54.1427 ;
			 LAYER V2 ;
			RECT 0.0831 54.0545 0.098 54.0671 ;
		END

		ANTENNAGATEAREA 0.00027817 ;
		ANTENNADIFFAREA 0.00194719 ;
		ANTENNAPARTIALMETALAREA 0.00195671 ;
	END TWENA[27]

	PIN TWENA[28]
		USE SIGNAL ;
		DIRECTION INPUT ;
		SHAPE ABUTMENT ;
		PORT
			 LAYER M2 ;
			RECT 0.0714 55.6235 0.1097 55.6612 ;
			 LAYER M3 ;
			RECT 0.0714 55.6235 0.1097 55.7239 ;
			 LAYER V2 ;
			RECT 0.0831 55.6357 0.098 55.6482 ;
		END

		ANTENNAGATEAREA 0.00027817 ;
		ANTENNADIFFAREA 0.00194719 ;
		ANTENNAPARTIALMETALAREA 0.00195671 ;
	END TWENA[28]

	PIN TWENA[29]
		USE SIGNAL ;
		DIRECTION INPUT ;
		SHAPE ABUTMENT ;
		PORT
			 LAYER M2 ;
			RECT 0.0714 57.2047 0.1097 57.2424 ;
			 LAYER M3 ;
			RECT 0.0714 57.2047 0.1097 57.3051 ;
			 LAYER V2 ;
			RECT 0.0831 57.2169 0.098 57.2294 ;
		END

		ANTENNAGATEAREA 0.00027817 ;
		ANTENNADIFFAREA 0.00194719 ;
		ANTENNAPARTIALMETALAREA 0.00195671 ;
	END TWENA[29]

	PIN TWENA[2]
		USE SIGNAL ;
		DIRECTION INPUT ;
		SHAPE ABUTMENT ;
		PORT
			 LAYER M2 ;
			RECT 0.0714 4.4047 0.1097 4.4424 ;
			 LAYER M3 ;
			RECT 0.0714 4.342 0.1097 4.4424 ;
			 LAYER V2 ;
			RECT 0.0831 4.4176 0.098 4.4302 ;
		END

		ANTENNAGATEAREA 0.00027817 ;
		ANTENNADIFFAREA 0.00194719 ;
		ANTENNAPARTIALMETALAREA 0.00195671 ;
	END TWENA[2]

	PIN TWENA[30]
		USE SIGNAL ;
		DIRECTION INPUT ;
		SHAPE ABUTMENT ;
		PORT
			 LAYER M2 ;
			RECT 0.0714 58.7859 0.1097 58.8235 ;
			 LAYER M3 ;
			RECT 0.0714 58.7859 0.1097 58.8863 ;
			 LAYER V2 ;
			RECT 0.0831 58.798 0.098 58.8106 ;
		END

		ANTENNAGATEAREA 0.00027817 ;
		ANTENNADIFFAREA 0.00194719 ;
		ANTENNAPARTIALMETALAREA 0.00195671 ;
	END TWENA[30]

	PIN TWENA[31]
		USE SIGNAL ;
		DIRECTION INPUT ;
		SHAPE ABUTMENT ;
		PORT
			 LAYER M2 ;
			RECT 0.0714 60.3671 0.1097 60.4047 ;
			 LAYER M3 ;
			RECT 0.0714 60.3671 0.1097 60.4675 ;
			 LAYER V2 ;
			RECT 0.0831 60.3792 0.098 60.3918 ;
		END

		ANTENNAGATEAREA 0.00027817 ;
		ANTENNADIFFAREA 0.00194719 ;
		ANTENNAPARTIALMETALAREA 0.00195671 ;
	END TWENA[31]

	PIN TWENA[32]
		USE SIGNAL ;
		DIRECTION INPUT ;
		SHAPE ABUTMENT ;
		PORT
			 LAYER M2 ;
			RECT 0.0714 61.9482 0.1097 61.9859 ;
			 LAYER M3 ;
			RECT 0.0714 61.9482 0.1097 62.0486 ;
			 LAYER V2 ;
			RECT 0.0831 61.9604 0.098 61.9729 ;
		END

		ANTENNAGATEAREA 0.00027817 ;
		ANTENNADIFFAREA 0.00194719 ;
		ANTENNAPARTIALMETALAREA 0.00195671 ;
	END TWENA[32]

	PIN TWENA[3]
		USE SIGNAL ;
		DIRECTION INPUT ;
		SHAPE ABUTMENT ;
		PORT
			 LAYER M2 ;
			RECT 0.0714 5.9859 0.1097 6.0235 ;
			 LAYER M3 ;
			RECT 0.0714 5.9231 0.1097 6.0235 ;
			 LAYER V2 ;
			RECT 0.0831 5.9988 0.098 6.0114 ;
		END

		ANTENNAGATEAREA 0.00027817 ;
		ANTENNADIFFAREA 0.00194719 ;
		ANTENNAPARTIALMETALAREA 0.00195671 ;
	END TWENA[3]

	PIN TWENA[4]
		USE SIGNAL ;
		DIRECTION INPUT ;
		SHAPE ABUTMENT ;
		PORT
			 LAYER M2 ;
			RECT 0.0714 7.5671 0.1097 7.6047 ;
			 LAYER M3 ;
			RECT 0.0714 7.5043 0.1097 7.6047 ;
			 LAYER V2 ;
			RECT 0.0831 7.58 0.098 7.5925 ;
		END

		ANTENNAGATEAREA 0.00027817 ;
		ANTENNADIFFAREA 0.00194719 ;
		ANTENNAPARTIALMETALAREA 0.00195671 ;
	END TWENA[4]

	PIN TWENA[5]
		USE SIGNAL ;
		DIRECTION INPUT ;
		SHAPE ABUTMENT ;
		PORT
			 LAYER M2 ;
			RECT 0.0714 9.1482 0.1097 9.1859 ;
			 LAYER M3 ;
			RECT 0.0714 9.0855 0.1097 9.1859 ;
			 LAYER V2 ;
			RECT 0.0831 9.1612 0.098 9.1737 ;
		END

		ANTENNAGATEAREA 0.00027817 ;
		ANTENNADIFFAREA 0.00194719 ;
		ANTENNAPARTIALMETALAREA 0.00195671 ;
	END TWENA[5]

	PIN TWENA[6]
		USE SIGNAL ;
		DIRECTION INPUT ;
		SHAPE ABUTMENT ;
		PORT
			 LAYER M2 ;
			RECT 0.0714 10.7294 0.1097 10.7671 ;
			 LAYER M3 ;
			RECT 0.0714 10.6667 0.1097 10.7671 ;
			 LAYER V2 ;
			RECT 0.0831 10.7424 0.098 10.7549 ;
		END

		ANTENNAGATEAREA 0.00027817 ;
		ANTENNADIFFAREA 0.00194719 ;
		ANTENNAPARTIALMETALAREA 0.00195671 ;
	END TWENA[6]

	PIN TWENA[7]
		USE SIGNAL ;
		DIRECTION INPUT ;
		SHAPE ABUTMENT ;
		PORT
			 LAYER M2 ;
			RECT 0.0714 12.3106 0.1097 12.3482 ;
			 LAYER M3 ;
			RECT 0.0714 12.2478 0.1097 12.3482 ;
			 LAYER V2 ;
			RECT 0.0831 12.3235 0.098 12.3361 ;
		END

		ANTENNAGATEAREA 0.00027817 ;
		ANTENNADIFFAREA 0.00194719 ;
		ANTENNAPARTIALMETALAREA 0.00195671 ;
	END TWENA[7]

	PIN TWENA[8]
		USE SIGNAL ;
		DIRECTION INPUT ;
		SHAPE ABUTMENT ;
		PORT
			 LAYER M2 ;
			RECT 0.0714 13.8918 0.1097 13.9294 ;
			 LAYER M3 ;
			RECT 0.0714 13.829 0.1097 13.9294 ;
			 LAYER V2 ;
			RECT 0.0831 13.9047 0.098 13.9173 ;
		END

		ANTENNAGATEAREA 0.00027817 ;
		ANTENNADIFFAREA 0.00194719 ;
		ANTENNAPARTIALMETALAREA 0.00195671 ;
	END TWENA[8]

	PIN TWENA[9]
		USE SIGNAL ;
		DIRECTION INPUT ;
		SHAPE ABUTMENT ;
		PORT
			 LAYER M2 ;
			RECT 0.0714 15.4729 0.1097 15.5106 ;
			 LAYER M3 ;
			RECT 0.0714 15.4102 0.1097 15.5106 ;
			 LAYER V2 ;
			RECT 0.0831 15.4859 0.098 15.4984 ;
		END

		ANTENNAGATEAREA 0.00027817 ;
		ANTENNADIFFAREA 0.00194719 ;
		ANTENNAPARTIALMETALAREA 0.00195671 ;
	END TWENA[9]

	PIN TWENB[0]
		USE SIGNAL ;
		DIRECTION INPUT ;
		SHAPE ABUTMENT ;
		PORT
			 LAYER M2 ;
			RECT 0.0098 1.0918 0.0481 1.1294 ;
		END

		ANTENNAGATEAREA 0.00027817 ;
		ANTENNADIFFAREA 0.00194719 ;
		ANTENNAPARTIALMETALAREA 0.00195671 ;
	END TWENB[0]

	PIN TWENB[10]
		USE SIGNAL ;
		DIRECTION INPUT ;
		SHAPE ABUTMENT ;
		PORT
			 LAYER M2 ;
			RECT 0.0098 16.9035 0.0481 16.9412 ;
		END

		ANTENNAGATEAREA 0.00027817 ;
		ANTENNADIFFAREA 0.00194719 ;
		ANTENNAPARTIALMETALAREA 0.00195671 ;
	END TWENB[10]

	PIN TWENB[11]
		USE SIGNAL ;
		DIRECTION INPUT ;
		SHAPE ABUTMENT ;
		PORT
			 LAYER M2 ;
			RECT 0.0098 18.4847 0.0481 18.5224 ;
		END

		ANTENNAGATEAREA 0.00027817 ;
		ANTENNADIFFAREA 0.00194719 ;
		ANTENNAPARTIALMETALAREA 0.00195671 ;
	END TWENB[11]

	PIN TWENB[12]
		USE SIGNAL ;
		DIRECTION INPUT ;
		SHAPE ABUTMENT ;
		PORT
			 LAYER M2 ;
			RECT 0.0098 20.0659 0.0481 20.1035 ;
		END

		ANTENNAGATEAREA 0.00027817 ;
		ANTENNADIFFAREA 0.00194719 ;
		ANTENNAPARTIALMETALAREA 0.00195671 ;
	END TWENB[12]

	PIN TWENB[13]
		USE SIGNAL ;
		DIRECTION INPUT ;
		SHAPE ABUTMENT ;
		PORT
			 LAYER M2 ;
			RECT 0.0098 21.6471 0.0481 21.6847 ;
		END

		ANTENNAGATEAREA 0.00027817 ;
		ANTENNADIFFAREA 0.00194719 ;
		ANTENNAPARTIALMETALAREA 0.00195671 ;
	END TWENB[13]

	PIN TWENB[14]
		USE SIGNAL ;
		DIRECTION INPUT ;
		SHAPE ABUTMENT ;
		PORT
			 LAYER M2 ;
			RECT 0.0098 23.2282 0.0481 23.2659 ;
		END

		ANTENNAGATEAREA 0.00027817 ;
		ANTENNADIFFAREA 0.00194719 ;
		ANTENNAPARTIALMETALAREA 0.00195671 ;
	END TWENB[14]

	PIN TWENB[15]
		USE SIGNAL ;
		DIRECTION INPUT ;
		SHAPE ABUTMENT ;
		PORT
			 LAYER M2 ;
			RECT 0.0098 24.8094 0.0481 24.8471 ;
		END

		ANTENNAGATEAREA 0.00027817 ;
		ANTENNADIFFAREA 0.00194719 ;
		ANTENNAPARTIALMETALAREA 0.00195671 ;
	END TWENB[15]

	PIN TWENB[16]
		USE SIGNAL ;
		DIRECTION INPUT ;
		SHAPE ABUTMENT ;
		PORT
			 LAYER M2 ;
			RECT 0.0098 36.8 0.0481 36.8376 ;
		END

		ANTENNAGATEAREA 0.00027817 ;
		ANTENNADIFFAREA 0.00194719 ;
		ANTENNAPARTIALMETALAREA 0.00195671 ;
	END TWENB[16]

	PIN TWENB[17]
		USE SIGNAL ;
		DIRECTION INPUT ;
		SHAPE ABUTMENT ;
		PORT
			 LAYER M2 ;
			RECT 0.0098 38.3812 0.0481 38.4188 ;
		END

		ANTENNAGATEAREA 0.00027817 ;
		ANTENNADIFFAREA 0.00194719 ;
		ANTENNAPARTIALMETALAREA 0.00195671 ;
	END TWENB[17]

	PIN TWENB[18]
		USE SIGNAL ;
		DIRECTION INPUT ;
		SHAPE ABUTMENT ;
		PORT
			 LAYER M2 ;
			RECT 0.0098 39.9624 0.0481 40 ;
		END

		ANTENNAGATEAREA 0.00027817 ;
		ANTENNADIFFAREA 0.00194719 ;
		ANTENNAPARTIALMETALAREA 0.00195671 ;
	END TWENB[18]

	PIN TWENB[19]
		USE SIGNAL ;
		DIRECTION INPUT ;
		SHAPE ABUTMENT ;
		PORT
			 LAYER M2 ;
			RECT 0.0098 41.5435 0.0481 41.5812 ;
		END

		ANTENNAGATEAREA 0.00027817 ;
		ANTENNADIFFAREA 0.00194719 ;
		ANTENNAPARTIALMETALAREA 0.00195671 ;
	END TWENB[19]

	PIN TWENB[1]
		USE SIGNAL ;
		DIRECTION INPUT ;
		SHAPE ABUTMENT ;
		PORT
			 LAYER M2 ;
			RECT 0.0098 2.6729 0.0481 2.7106 ;
		END

		ANTENNAGATEAREA 0.00027817 ;
		ANTENNADIFFAREA 0.00194719 ;
		ANTENNAPARTIALMETALAREA 0.00195671 ;
	END TWENB[1]

	PIN TWENB[20]
		USE SIGNAL ;
		DIRECTION INPUT ;
		SHAPE ABUTMENT ;
		PORT
			 LAYER M2 ;
			RECT 0.0098 43.1247 0.0481 43.1624 ;
		END

		ANTENNAGATEAREA 0.00027817 ;
		ANTENNADIFFAREA 0.00194719 ;
		ANTENNAPARTIALMETALAREA 0.00195671 ;
	END TWENB[20]

	PIN TWENB[21]
		USE SIGNAL ;
		DIRECTION INPUT ;
		SHAPE ABUTMENT ;
		PORT
			 LAYER M2 ;
			RECT 0.0098 44.7059 0.0481 44.7435 ;
		END

		ANTENNAGATEAREA 0.00027817 ;
		ANTENNADIFFAREA 0.00194719 ;
		ANTENNAPARTIALMETALAREA 0.00195671 ;
	END TWENB[21]

	PIN TWENB[22]
		USE SIGNAL ;
		DIRECTION INPUT ;
		SHAPE ABUTMENT ;
		PORT
			 LAYER M2 ;
			RECT 0.0098 46.2871 0.0481 46.3247 ;
		END

		ANTENNAGATEAREA 0.00027817 ;
		ANTENNADIFFAREA 0.00194719 ;
		ANTENNAPARTIALMETALAREA 0.00195671 ;
	END TWENB[22]

	PIN TWENB[23]
		USE SIGNAL ;
		DIRECTION INPUT ;
		SHAPE ABUTMENT ;
		PORT
			 LAYER M2 ;
			RECT 0.0098 47.8682 0.0481 47.9059 ;
		END

		ANTENNAGATEAREA 0.00027817 ;
		ANTENNADIFFAREA 0.00194719 ;
		ANTENNAPARTIALMETALAREA 0.00195671 ;
	END TWENB[23]

	PIN TWENB[24]
		USE SIGNAL ;
		DIRECTION INPUT ;
		SHAPE ABUTMENT ;
		PORT
			 LAYER M2 ;
			RECT 0.0098 49.4494 0.0481 49.4871 ;
		END

		ANTENNAGATEAREA 0.00027817 ;
		ANTENNADIFFAREA 0.00194719 ;
		ANTENNAPARTIALMETALAREA 0.00195671 ;
	END TWENB[24]

	PIN TWENB[25]
		USE SIGNAL ;
		DIRECTION INPUT ;
		SHAPE ABUTMENT ;
		PORT
			 LAYER M2 ;
			RECT 0.0098 51.0306 0.0481 51.0682 ;
		END

		ANTENNAGATEAREA 0.00027817 ;
		ANTENNADIFFAREA 0.00194719 ;
		ANTENNAPARTIALMETALAREA 0.00195671 ;
	END TWENB[25]

	PIN TWENB[26]
		USE SIGNAL ;
		DIRECTION INPUT ;
		SHAPE ABUTMENT ;
		PORT
			 LAYER M2 ;
			RECT 0.0098 52.6118 0.0481 52.6494 ;
		END

		ANTENNAGATEAREA 0.00027817 ;
		ANTENNADIFFAREA 0.00194719 ;
		ANTENNAPARTIALMETALAREA 0.00195671 ;
	END TWENB[26]

	PIN TWENB[27]
		USE SIGNAL ;
		DIRECTION INPUT ;
		SHAPE ABUTMENT ;
		PORT
			 LAYER M2 ;
			RECT 0.0098 54.1929 0.0481 54.2306 ;
		END

		ANTENNAGATEAREA 0.00027817 ;
		ANTENNADIFFAREA 0.00194719 ;
		ANTENNAPARTIALMETALAREA 0.00195671 ;
	END TWENB[27]

	PIN TWENB[28]
		USE SIGNAL ;
		DIRECTION INPUT ;
		SHAPE ABUTMENT ;
		PORT
			 LAYER M2 ;
			RECT 0.0098 55.7741 0.0481 55.8118 ;
		END

		ANTENNAGATEAREA 0.00027817 ;
		ANTENNADIFFAREA 0.00194719 ;
		ANTENNAPARTIALMETALAREA 0.00195671 ;
	END TWENB[28]

	PIN TWENB[29]
		USE SIGNAL ;
		DIRECTION INPUT ;
		SHAPE ABUTMENT ;
		PORT
			 LAYER M2 ;
			RECT 0.0098 57.3553 0.0481 57.3929 ;
		END

		ANTENNAGATEAREA 0.00027817 ;
		ANTENNADIFFAREA 0.00194719 ;
		ANTENNAPARTIALMETALAREA 0.00195671 ;
	END TWENB[29]

	PIN TWENB[2]
		USE SIGNAL ;
		DIRECTION INPUT ;
		SHAPE ABUTMENT ;
		PORT
			 LAYER M2 ;
			RECT 0.0098 4.2541 0.0481 4.2918 ;
		END

		ANTENNAGATEAREA 0.00027817 ;
		ANTENNADIFFAREA 0.00194719 ;
		ANTENNAPARTIALMETALAREA 0.00195671 ;
	END TWENB[2]

	PIN TWENB[30]
		USE SIGNAL ;
		DIRECTION INPUT ;
		SHAPE ABUTMENT ;
		PORT
			 LAYER M2 ;
			RECT 0.0098 58.9365 0.0481 58.9741 ;
		END

		ANTENNAGATEAREA 0.00027817 ;
		ANTENNADIFFAREA 0.00194719 ;
		ANTENNAPARTIALMETALAREA 0.00195671 ;
	END TWENB[30]

	PIN TWENB[31]
		USE SIGNAL ;
		DIRECTION INPUT ;
		SHAPE ABUTMENT ;
		PORT
			 LAYER M2 ;
			RECT 0.0098 60.5176 0.0481 60.5553 ;
		END

		ANTENNAGATEAREA 0.00027817 ;
		ANTENNADIFFAREA 0.00194719 ;
		ANTENNAPARTIALMETALAREA 0.00195671 ;
	END TWENB[31]

	PIN TWENB[32]
		USE SIGNAL ;
		DIRECTION INPUT ;
		SHAPE ABUTMENT ;
		PORT
			 LAYER M2 ;
			RECT 0.0098 62.0988 0.0481 62.1365 ;
		END

		ANTENNAGATEAREA 0.00027817 ;
		ANTENNADIFFAREA 0.00194719 ;
		ANTENNAPARTIALMETALAREA 0.00195671 ;
	END TWENB[32]

	PIN TWENB[3]
		USE SIGNAL ;
		DIRECTION INPUT ;
		SHAPE ABUTMENT ;
		PORT
			 LAYER M2 ;
			RECT 0.0098 5.8353 0.0481 5.8729 ;
		END

		ANTENNAGATEAREA 0.00027817 ;
		ANTENNADIFFAREA 0.00194719 ;
		ANTENNAPARTIALMETALAREA 0.00195671 ;
	END TWENB[3]

	PIN TWENB[4]
		USE SIGNAL ;
		DIRECTION INPUT ;
		SHAPE ABUTMENT ;
		PORT
			 LAYER M2 ;
			RECT 0.0098 7.4165 0.0481 7.4541 ;
		END

		ANTENNAGATEAREA 0.00027817 ;
		ANTENNADIFFAREA 0.00194719 ;
		ANTENNAPARTIALMETALAREA 0.00195671 ;
	END TWENB[4]

	PIN TWENB[5]
		USE SIGNAL ;
		DIRECTION INPUT ;
		SHAPE ABUTMENT ;
		PORT
			 LAYER M2 ;
			RECT 0.0098 8.9976 0.0481 9.0353 ;
		END

		ANTENNAGATEAREA 0.00027817 ;
		ANTENNADIFFAREA 0.00194719 ;
		ANTENNAPARTIALMETALAREA 0.00195671 ;
	END TWENB[5]

	PIN TWENB[6]
		USE SIGNAL ;
		DIRECTION INPUT ;
		SHAPE ABUTMENT ;
		PORT
			 LAYER M2 ;
			RECT 0.0098 10.5788 0.0481 10.6165 ;
		END

		ANTENNAGATEAREA 0.00027817 ;
		ANTENNADIFFAREA 0.00194719 ;
		ANTENNAPARTIALMETALAREA 0.00195671 ;
	END TWENB[6]

	PIN TWENB[7]
		USE SIGNAL ;
		DIRECTION INPUT ;
		SHAPE ABUTMENT ;
		PORT
			 LAYER M2 ;
			RECT 0.0098 12.16 0.0481 12.1976 ;
		END

		ANTENNAGATEAREA 0.00027817 ;
		ANTENNADIFFAREA 0.00194719 ;
		ANTENNAPARTIALMETALAREA 0.00195671 ;
	END TWENB[7]

	PIN TWENB[8]
		USE SIGNAL ;
		DIRECTION INPUT ;
		SHAPE ABUTMENT ;
		PORT
			 LAYER M2 ;
			RECT 0.0098 13.7412 0.0481 13.7788 ;
		END

		ANTENNAGATEAREA 0.00027817 ;
		ANTENNADIFFAREA 0.00194719 ;
		ANTENNAPARTIALMETALAREA 0.00195671 ;
	END TWENB[8]

	PIN TWENB[9]
		USE SIGNAL ;
		DIRECTION INPUT ;
		SHAPE ABUTMENT ;
		PORT
			 LAYER M2 ;
			RECT 0.0098 15.3224 0.0481 15.36 ;
		END

		ANTENNAGATEAREA 0.00027817 ;
		ANTENNADIFFAREA 0.00194719 ;
		ANTENNAPARTIALMETALAREA 0.00195671 ;
	END TWENB[9]

	PIN VDDCE
		USE POWER ;
		DIRECTION INOUT ;
		PORT
			 LAYER M4 ;
			RECT 0.2105 62.2275 12.705 62.2745 ;
		END

		PORT
			 LAYER M4 ;
			RECT 0.2105 61.4369 12.705 61.4839 ;
		END

		PORT
			 LAYER M4 ;
			RECT 0.2105 43.2533 12.705 43.3004 ;
		END

		PORT
			 LAYER M4 ;
			RECT 0.2105 42.4627 12.705 42.5098 ;
		END

		PORT
			 LAYER M4 ;
			RECT 0.2105 41.6722 12.705 41.7192 ;
		END

		PORT
			 LAYER M4 ;
			RECT 0.2105 40.8816 12.705 40.9286 ;
		END

		PORT
			 LAYER M4 ;
			RECT 0.2105 40.091 12.705 40.138 ;
		END

		PORT
			 LAYER M4 ;
			RECT 0.2105 39.3004 12.705 39.3475 ;
		END

		PORT
			 LAYER M4 ;
			RECT 0.2105 38.5098 12.705 38.5569 ;
		END

		PORT
			 LAYER M4 ;
			RECT 0.2105 37.7192 12.705 37.7663 ;
		END

		PORT
			 LAYER M4 ;
			RECT 0.2105 36.9286 12.705 36.9757 ;
		END

		PORT
			 LAYER M4 ;
			RECT 0.2105 36.138 12.705 36.1851 ;
		END

		PORT
			 LAYER M4 ;
			RECT 0.2105 60.6463 12.705 60.6933 ;
		END

		PORT
			 LAYER M4 ;
			RECT 0.2105 35.3475 12.705 35.3945 ;
		END

		PORT
			 LAYER M4 ;
			RECT 0.2105 34.5569 12.705 34.6039 ;
		END

		PORT
			 LAYER M4 ;
			RECT 0.2105 59.8557 12.705 59.9027 ;
		END

		PORT
			 LAYER M4 ;
			RECT 0.2105 27.0431 12.705 27.0902 ;
		END

		PORT
			 LAYER M4 ;
			RECT 0.2105 26.2525 12.705 26.2996 ;
		END

		PORT
			 LAYER M4 ;
			RECT 0.2105 25.462 12.705 25.509 ;
		END

		PORT
			 LAYER M4 ;
			RECT 0.2105 24.6714 12.705 24.7184 ;
		END

		PORT
			 LAYER M4 ;
			RECT 0.2105 23.8808 12.705 23.9278 ;
		END

		PORT
			 LAYER M4 ;
			RECT 0.2105 23.0902 12.705 23.1373 ;
		END

		PORT
			 LAYER M4 ;
			RECT 0.2105 22.2996 12.705 22.3467 ;
		END

		PORT
			 LAYER M4 ;
			RECT 0.2105 21.509 12.705 21.5561 ;
		END

		PORT
			 LAYER M4 ;
			RECT 0.2105 20.7184 12.705 20.7655 ;
		END

		PORT
			 LAYER M4 ;
			RECT 0.2105 19.9278 12.705 19.9749 ;
		END

		PORT
			 LAYER M4 ;
			RECT 0.2105 59.0651 12.705 59.1122 ;
		END

		PORT
			 LAYER M4 ;
			RECT 0.2105 19.1373 12.705 19.1843 ;
		END

		PORT
			 LAYER M4 ;
			RECT 0.2105 18.3467 12.705 18.3937 ;
		END

		PORT
			 LAYER M4 ;
			RECT 0.2105 17.5561 12.705 17.6031 ;
		END

		PORT
			 LAYER M4 ;
			RECT 0.2105 16.7655 12.705 16.8125 ;
		END

		PORT
			 LAYER M4 ;
			RECT 0.2105 15.9749 12.705 16.022 ;
		END

		PORT
			 LAYER M4 ;
			RECT 0.2105 15.1843 12.705 15.2314 ;
		END

		PORT
			 LAYER M4 ;
			RECT 0.2105 14.3937 12.705 14.4408 ;
		END

		PORT
			 LAYER M4 ;
			RECT 0.2105 13.6031 12.705 13.6502 ;
		END

		PORT
			 LAYER M4 ;
			RECT 0.2105 12.8125 12.705 12.8596 ;
		END

		PORT
			 LAYER M4 ;
			RECT 0.2105 12.022 12.705 12.069 ;
		END

		PORT
			 LAYER M4 ;
			RECT 0.2105 58.2745 12.705 58.3216 ;
		END

		PORT
			 LAYER M4 ;
			RECT 0.2105 11.2314 12.705 11.2784 ;
		END

		PORT
			 LAYER M4 ;
			RECT 0.2105 10.4408 12.705 10.4878 ;
		END

		PORT
			 LAYER M4 ;
			RECT 0.2105 9.6502 12.705 9.6973 ;
		END

		PORT
			 LAYER M4 ;
			RECT 0.2105 8.8596 12.705 8.9067 ;
		END

		PORT
			 LAYER M4 ;
			RECT 0.2105 8.069 12.705 8.1161 ;
		END

		PORT
			 LAYER M4 ;
			RECT 0.2105 7.2784 12.705 7.3255 ;
		END

		PORT
			 LAYER M4 ;
			RECT 0.2105 6.4878 12.705 6.5349 ;
		END

		PORT
			 LAYER M4 ;
			RECT 0.2105 5.6973 12.705 5.7443 ;
		END

		PORT
			 LAYER M4 ;
			RECT 0.2105 4.9067 12.705 4.9537 ;
		END

		PORT
			 LAYER M4 ;
			RECT 0.2105 4.1161 12.705 4.1631 ;
		END

		PORT
			 LAYER M4 ;
			RECT 0.2105 57.4839 12.705 57.531 ;
		END

		PORT
			 LAYER M4 ;
			RECT 0.2105 3.3255 12.705 3.3725 ;
		END

		PORT
			 LAYER M4 ;
			RECT 0.2105 2.5349 12.705 2.582 ;
		END

		PORT
			 LAYER M4 ;
			RECT 0.2105 1.7443 12.705 1.7914 ;
		END

		PORT
			 LAYER M4 ;
			RECT 0.2105 0.9537 12.705 1.0008 ;
		END

		PORT
			 LAYER M4 ;
			RECT 0.2105 56.6933 12.705 56.7404 ;
		END

		PORT
			 LAYER M4 ;
			RECT 0.2105 55.9027 12.705 55.9498 ;
		END

		PORT
			 LAYER M4 ;
			RECT 0.2105 55.1122 12.705 55.1592 ;
		END

		PORT
			 LAYER M4 ;
			RECT 0.2105 54.3216 12.705 54.3686 ;
		END

		PORT
			 LAYER M4 ;
			RECT 0.2105 53.531 12.705 53.578 ;
		END

		PORT
			 LAYER M4 ;
			RECT 0.2105 52.7404 12.705 52.7875 ;
		END

		PORT
			 LAYER M4 ;
			RECT 0.2105 51.9498 12.705 51.9969 ;
		END

		PORT
			 LAYER M4 ;
			RECT 0.2105 51.1592 12.705 51.2063 ;
		END

		PORT
			 LAYER M4 ;
			RECT 0.2105 50.3686 12.705 50.4157 ;
		END

		PORT
			 LAYER M4 ;
			RECT 0.2105 49.578 12.705 49.6251 ;
		END

		PORT
			 LAYER M4 ;
			RECT 0.2105 48.7875 12.705 48.8345 ;
		END

		PORT
			 LAYER M4 ;
			RECT 0.2105 47.9969 12.705 48.0439 ;
		END

		PORT
			 LAYER M4 ;
			RECT 0.2105 47.2063 12.705 47.2533 ;
		END

		PORT
			 LAYER M4 ;
			RECT 0.2105 46.4157 12.705 46.4627 ;
		END

		PORT
			 LAYER M4 ;
			RECT 0.2105 45.6251 12.705 45.6722 ;
		END

		PORT
			 LAYER M4 ;
			RECT 0.2105 44.8345 12.705 44.8816 ;
		END

		PORT
			 LAYER M4 ;
			RECT 0.2105 44.0439 12.705 44.091 ;
		END

		PORT
			 LAYER M4 ;
			RECT 0.2105 27.6345 12.705 27.6816 ;
		END

		PORT
			 LAYER M4 ;
			RECT 0.2105 27.9263 12.705 27.9733 ;
		END

		PORT
			 LAYER M4 ;
			RECT 0.2105 33.8808 12.705 33.9278 ;
		END

		PORT
			 LAYER M4 ;
			RECT 0.2105 34.1725 12.705 34.2196 ;
		END

		PORT
			 LAYER M4 ;
			RECT 0.2105 27.1843 12.705 27.2157 ;
		END

		PORT
			 LAYER M4 ;
			RECT 0.2105 34.4314 12.705 34.4627 ;
		END

		PORT
			 LAYER M4 ;
			RECT 0.2105 63.018 12.705 63.0494 ;
		END

		PORT
			 LAYER M4 ;
			RECT 0.2105 0.1788 12.705 0.2102 ;
		END

	END VDDCE

	PIN VDDPE
		USE POWER ;
		DIRECTION INOUT ;
		PORT
			 LAYER M4 ;
			RECT 0.2105 62.8612 12.705 62.9082 ;
		END

		PORT
			 LAYER M4 ;
			RECT 0.2105 43.8871 12.705 43.9341 ;
		END

		PORT
			 LAYER M4 ;
			RECT 0.2105 43.0965 12.705 43.1435 ;
		END

		PORT
			 LAYER M4 ;
			RECT 0.2105 42.3059 12.705 42.3529 ;
		END

		PORT
			 LAYER M4 ;
			RECT 0.2105 41.5153 12.705 41.5624 ;
		END

		PORT
			 LAYER M4 ;
			RECT 0.2105 40.7247 12.705 40.7718 ;
		END

		PORT
			 LAYER M4 ;
			RECT 0.2105 61.28 12.705 61.3271 ;
		END

		PORT
			 LAYER M4 ;
			RECT 0.2105 39.9341 12.705 39.9812 ;
		END

		PORT
			 LAYER M4 ;
			RECT 0.2105 39.1435 12.705 39.1906 ;
		END

		PORT
			 LAYER M4 ;
			RECT 0.2105 38.3529 12.705 38.4 ;
		END

		PORT
			 LAYER M4 ;
			RECT 0.2105 37.5624 12.705 37.6094 ;
		END

		PORT
			 LAYER M4 ;
			RECT 0.2105 36.7718 12.705 36.8188 ;
		END

		PORT
			 LAYER M4 ;
			RECT 0.2105 35.9812 12.705 36.0282 ;
		END

		PORT
			 LAYER M4 ;
			RECT 0.2105 35.1906 12.705 35.2376 ;
		END

		PORT
			 LAYER M4 ;
			RECT 0.2105 60.4894 12.705 60.5365 ;
		END

		PORT
			 LAYER M4 ;
			RECT 0.2105 26.4094 12.705 26.4565 ;
		END

		PORT
			 LAYER M4 ;
			RECT 0.2105 25.6188 12.705 25.6659 ;
		END

		PORT
			 LAYER M4 ;
			RECT 0.2105 24.8282 12.705 24.8753 ;
		END

		PORT
			 LAYER M4 ;
			RECT 0.2105 24.0376 12.705 24.0847 ;
		END

		PORT
			 LAYER M4 ;
			RECT 0.2105 23.2471 12.705 23.2941 ;
		END

		PORT
			 LAYER M4 ;
			RECT 0.2105 59.6988 12.705 59.7459 ;
		END

		PORT
			 LAYER M4 ;
			RECT 0.2105 22.4565 12.705 22.5035 ;
		END

		PORT
			 LAYER M4 ;
			RECT 0.2105 21.6659 12.705 21.7129 ;
		END

		PORT
			 LAYER M4 ;
			RECT 0.2105 20.8753 12.705 20.9224 ;
		END

		PORT
			 LAYER M4 ;
			RECT 0.2105 20.0847 12.705 20.1318 ;
		END

		PORT
			 LAYER M4 ;
			RECT 0.2105 19.2941 12.705 19.3412 ;
		END

		PORT
			 LAYER M4 ;
			RECT 0.2105 18.5035 12.705 18.5506 ;
		END

		PORT
			 LAYER M4 ;
			RECT 0.2105 17.7129 12.705 17.76 ;
		END

		PORT
			 LAYER M4 ;
			RECT 0.2105 16.9224 12.705 16.9694 ;
		END

		PORT
			 LAYER M4 ;
			RECT 0.2105 16.1318 12.705 16.1788 ;
		END

		PORT
			 LAYER M4 ;
			RECT 0.2105 15.3412 12.705 15.3882 ;
		END

		PORT
			 LAYER M4 ;
			RECT 0.2105 58.9082 12.705 58.9553 ;
		END

		PORT
			 LAYER M4 ;
			RECT 0.2105 14.5506 12.705 14.5976 ;
		END

		PORT
			 LAYER M4 ;
			RECT 0.2105 13.76 12.705 13.8071 ;
		END

		PORT
			 LAYER M4 ;
			RECT 0.2105 12.9694 12.705 13.0165 ;
		END

		PORT
			 LAYER M4 ;
			RECT 0.2105 12.1788 12.705 12.2259 ;
		END

		PORT
			 LAYER M4 ;
			RECT 0.2105 11.3882 12.705 11.4353 ;
		END

		PORT
			 LAYER M4 ;
			RECT 0.2105 10.5976 12.705 10.6447 ;
		END

		PORT
			 LAYER M4 ;
			RECT 0.2105 9.8071 12.705 9.8541 ;
		END

		PORT
			 LAYER M4 ;
			RECT 0.2105 9.0165 12.705 9.0635 ;
		END

		PORT
			 LAYER M4 ;
			RECT 0.2105 8.2259 12.705 8.2729 ;
		END

		PORT
			 LAYER M4 ;
			RECT 0.2105 7.4353 12.705 7.4824 ;
		END

		PORT
			 LAYER M4 ;
			RECT 0.2105 58.1176 12.705 58.1647 ;
		END

		PORT
			 LAYER M4 ;
			RECT 0.2105 6.6447 12.705 6.6918 ;
		END

		PORT
			 LAYER M4 ;
			RECT 0.2105 5.8541 12.705 5.9012 ;
		END

		PORT
			 LAYER M4 ;
			RECT 0.2105 5.0635 12.705 5.1106 ;
		END

		PORT
			 LAYER M4 ;
			RECT 0.2105 4.2729 12.705 4.32 ;
		END

		PORT
			 LAYER M4 ;
			RECT 0.2105 3.4824 12.705 3.5294 ;
		END

		PORT
			 LAYER M4 ;
			RECT 0.2105 2.6918 12.705 2.7388 ;
		END

		PORT
			 LAYER M4 ;
			RECT 0.2105 1.9012 12.705 1.9482 ;
		END

		PORT
			 LAYER M4 ;
			RECT 0.2105 1.1106 12.705 1.1576 ;
		END

		PORT
			 LAYER M4 ;
			RECT 0.2105 0.32 12.705 0.3671 ;
		END

		PORT
			 LAYER M4 ;
			RECT 0.2105 57.3271 12.705 57.3741 ;
		END

		PORT
			 LAYER M4 ;
			RECT 0.2105 56.5365 12.705 56.5835 ;
		END

		PORT
			 LAYER M4 ;
			RECT 0.2105 55.7459 12.705 55.7929 ;
		END

		PORT
			 LAYER M4 ;
			RECT 0.2105 54.9553 12.705 55.0024 ;
		END

		PORT
			 LAYER M4 ;
			RECT 0.2105 54.1647 12.705 54.2118 ;
		END

		PORT
			 LAYER M4 ;
			RECT 0.2105 53.3741 12.705 53.4212 ;
		END

		PORT
			 LAYER M4 ;
			RECT 0.2105 52.5835 12.705 52.6306 ;
		END

		PORT
			 LAYER M4 ;
			RECT 0.2105 51.7929 12.705 51.84 ;
		END

		PORT
			 LAYER M4 ;
			RECT 0.2105 51.0024 12.705 51.0494 ;
		END

		PORT
			 LAYER M4 ;
			RECT 0.2105 50.2118 12.705 50.2588 ;
		END

		PORT
			 LAYER M4 ;
			RECT 0.2105 49.4212 12.705 49.4682 ;
		END

		PORT
			 LAYER M4 ;
			RECT 0.2105 48.6306 12.705 48.6776 ;
		END

		PORT
			 LAYER M4 ;
			RECT 0.2105 62.0706 12.705 62.1176 ;
		END

		PORT
			 LAYER M4 ;
			RECT 0.2105 47.84 12.705 47.8871 ;
		END

		PORT
			 LAYER M4 ;
			RECT 0.2105 47.0494 12.705 47.0965 ;
		END

		PORT
			 LAYER M4 ;
			RECT 0.2105 46.2588 12.705 46.3059 ;
		END

		PORT
			 LAYER M4 ;
			RECT 0.2105 45.4682 12.705 45.5153 ;
		END

		PORT
			 LAYER M4 ;
			RECT 0.2105 44.6776 12.705 44.7247 ;
		END

		PORT
			 LAYER M4 ;
			RECT 0.2105 62.3059 12.705 62.3529 ;
		END

		PORT
			 LAYER M4 ;
			RECT 0.2105 43.3318 12.705 43.3788 ;
		END

		PORT
			 LAYER M4 ;
			RECT 0.2105 42.5412 12.705 42.5882 ;
		END

		PORT
			 LAYER M4 ;
			RECT 0.2105 41.7506 12.705 41.7976 ;
		END

		PORT
			 LAYER M4 ;
			RECT 0.2105 40.96 12.705 41.0071 ;
		END

		PORT
			 LAYER M4 ;
			RECT 0.2105 40.1694 12.705 40.2165 ;
		END

		PORT
			 LAYER M4 ;
			RECT 0.2105 39.3788 12.705 39.4259 ;
		END

		PORT
			 LAYER M4 ;
			RECT 0.2105 38.5882 12.705 38.6353 ;
		END

		PORT
			 LAYER M4 ;
			RECT 0.2105 37.7976 12.705 37.8447 ;
		END

		PORT
			 LAYER M4 ;
			RECT 0.2105 60.7247 12.705 60.7718 ;
		END

		PORT
			 LAYER M4 ;
			RECT 0.2105 37.0071 12.705 37.0541 ;
		END

		PORT
			 LAYER M4 ;
			RECT 0.2105 36.2165 12.705 36.2635 ;
		END

		PORT
			 LAYER M4 ;
			RECT 0.2105 35.4259 12.705 35.4729 ;
		END

		PORT
			 LAYER M4 ;
			RECT 0.2105 34.6353 12.705 34.6824 ;
		END

		PORT
			 LAYER M4 ;
			RECT 0.2105 59.9341 12.705 59.9812 ;
		END

		PORT
			 LAYER M4 ;
			RECT 0.2105 26.9647 12.705 27.0118 ;
		END

		PORT
			 LAYER M4 ;
			RECT 0.2105 26.1741 12.705 26.2212 ;
		END

		PORT
			 LAYER M4 ;
			RECT 0.2105 25.3835 12.705 25.4306 ;
		END

		PORT
			 LAYER M4 ;
			RECT 0.2105 24.5929 12.705 24.64 ;
		END

		PORT
			 LAYER M4 ;
			RECT 0.2105 23.8024 12.705 23.8494 ;
		END

		PORT
			 LAYER M4 ;
			RECT 0.2105 23.0118 12.705 23.0588 ;
		END

		PORT
			 LAYER M4 ;
			RECT 0.2105 22.2212 12.705 22.2682 ;
		END

		PORT
			 LAYER M4 ;
			RECT 0.2105 59.1435 12.705 59.1906 ;
		END

		PORT
			 LAYER M4 ;
			RECT 0.2105 21.4306 12.705 21.4776 ;
		END

		PORT
			 LAYER M4 ;
			RECT 0.2105 20.64 12.705 20.6871 ;
		END

		PORT
			 LAYER M4 ;
			RECT 0.2105 19.8494 12.705 19.8965 ;
		END

		PORT
			 LAYER M4 ;
			RECT 0.2105 19.0588 12.705 19.1059 ;
		END

		PORT
			 LAYER M4 ;
			RECT 0.2105 18.2682 12.705 18.3153 ;
		END

		PORT
			 LAYER M4 ;
			RECT 0.2105 17.4776 12.705 17.5247 ;
		END

		PORT
			 LAYER M4 ;
			RECT 0.2105 16.6871 12.705 16.7341 ;
		END

		PORT
			 LAYER M4 ;
			RECT 0.2105 15.8965 12.705 15.9435 ;
		END

		PORT
			 LAYER M4 ;
			RECT 0.2105 15.1059 12.705 15.1529 ;
		END

		PORT
			 LAYER M4 ;
			RECT 0.2105 14.3153 12.705 14.3624 ;
		END

		PORT
			 LAYER M4 ;
			RECT 0.2105 58.3529 12.705 58.4 ;
		END

		PORT
			 LAYER M4 ;
			RECT 0.2105 13.5247 12.705 13.5718 ;
		END

		PORT
			 LAYER M4 ;
			RECT 0.2105 12.7341 12.705 12.7812 ;
		END

		PORT
			 LAYER M4 ;
			RECT 0.2105 11.9435 12.705 11.9906 ;
		END

		PORT
			 LAYER M4 ;
			RECT 0.2105 11.1529 12.705 11.2 ;
		END

		PORT
			 LAYER M4 ;
			RECT 0.2105 10.3624 12.705 10.4094 ;
		END

		PORT
			 LAYER M4 ;
			RECT 0.2105 9.5718 12.705 9.6188 ;
		END

		PORT
			 LAYER M4 ;
			RECT 0.2105 8.7812 12.705 8.8282 ;
		END

		PORT
			 LAYER M4 ;
			RECT 0.2105 7.9906 12.705 8.0376 ;
		END

		PORT
			 LAYER M4 ;
			RECT 0.2105 7.2 12.705 7.2471 ;
		END

		PORT
			 LAYER M4 ;
			RECT 0.2105 6.4094 12.705 6.4565 ;
		END

		PORT
			 LAYER M4 ;
			RECT 0.2105 57.5624 12.705 57.6094 ;
		END

		PORT
			 LAYER M4 ;
			RECT 0.2105 5.6188 12.705 5.6659 ;
		END

		PORT
			 LAYER M4 ;
			RECT 0.2105 4.8282 12.705 4.8753 ;
		END

		PORT
			 LAYER M4 ;
			RECT 0.2105 4.0376 12.705 4.0847 ;
		END

		PORT
			 LAYER M4 ;
			RECT 0.2105 3.2471 12.705 3.2941 ;
		END

		PORT
			 LAYER M4 ;
			RECT 0.2105 2.4565 12.705 2.5035 ;
		END

		PORT
			 LAYER M4 ;
			RECT 0.2105 1.6659 12.705 1.7129 ;
		END

		PORT
			 LAYER M4 ;
			RECT 0.2105 0.8753 12.705 0.9224 ;
		END

		PORT
			 LAYER M4 ;
			RECT 0.2105 56.7718 12.705 56.8188 ;
		END

		PORT
			 LAYER M4 ;
			RECT 0.2105 55.9812 12.705 56.0282 ;
		END

		PORT
			 LAYER M4 ;
			RECT 0.2105 55.1906 12.705 55.2376 ;
		END

		PORT
			 LAYER M4 ;
			RECT 0.2105 54.4 12.705 54.4471 ;
		END

		PORT
			 LAYER M4 ;
			RECT 0.2105 53.6094 12.705 53.6565 ;
		END

		PORT
			 LAYER M4 ;
			RECT 0.2105 52.8188 12.705 52.8659 ;
		END

		PORT
			 LAYER M4 ;
			RECT 0.2105 52.0282 12.705 52.0753 ;
		END

		PORT
			 LAYER M4 ;
			RECT 0.2105 51.2376 12.705 51.2847 ;
		END

		PORT
			 LAYER M4 ;
			RECT 0.2105 50.4471 12.705 50.4941 ;
		END

		PORT
			 LAYER M4 ;
			RECT 0.2105 49.6565 12.705 49.7035 ;
		END

		PORT
			 LAYER M4 ;
			RECT 0.2105 48.8659 12.705 48.9129 ;
		END

		PORT
			 LAYER M4 ;
			RECT 0.2105 48.0753 12.705 48.1224 ;
		END

		PORT
			 LAYER M4 ;
			RECT 0.2105 47.2847 12.705 47.3318 ;
		END

		PORT
			 LAYER M4 ;
			RECT 0.2105 46.4941 12.705 46.5412 ;
		END

		PORT
			 LAYER M4 ;
			RECT 0.2105 45.7035 12.705 45.7506 ;
		END

		PORT
			 LAYER M4 ;
			RECT 0.2105 61.5153 12.705 61.5624 ;
		END

		PORT
			 LAYER M4 ;
			RECT 0.2105 44.9129 12.705 44.96 ;
		END

		PORT
			 LAYER M4 ;
			RECT 0.2105 44.1224 12.705 44.1694 ;
		END

		PORT
			 LAYER M4 ;
			RECT 0.2105 27.3882 12.705 27.4353 ;
		END

		PORT
			 LAYER M4 ;
			RECT 0.2105 28.0047 12.705 28.0518 ;
		END

		PORT
			 LAYER M4 ;
			RECT 0.2105 28.5318 12.705 28.5788 ;
		END

		PORT
			 LAYER M4 ;
			RECT 0.2105 29.0588 12.705 29.1059 ;
		END

		PORT
			 LAYER M4 ;
			RECT 0.2105 29.5859 12.705 29.6329 ;
		END

		PORT
			 LAYER M4 ;
			RECT 0.2105 30.1129 12.705 30.16 ;
		END

		PORT
			 LAYER M4 ;
			RECT 0.2105 31.1671 12.705 31.2141 ;
		END

		PORT
			 LAYER M4 ;
			RECT 0.2105 32.2212 12.705 32.2682 ;
		END

		PORT
			 LAYER M4 ;
			RECT 0.2105 32.7482 12.705 32.7953 ;
		END

		PORT
			 LAYER M4 ;
			RECT 0.2105 33.2753 12.705 33.3224 ;
		END

		PORT
			 LAYER M4 ;
			RECT 0.2105 33.8024 12.705 33.8494 ;
		END

		PORT
			 LAYER M4 ;
			RECT 0.2105 33.9592 12.705 34.0063 ;
		END

		PORT
			 LAYER M4 ;
			RECT 0.2105 27.2471 12.705 27.2784 ;
		END

		PORT
			 LAYER M4 ;
			RECT 0.2105 34.3686 12.705 34.4 ;
		END

		PORT
			 LAYER M4 ;
			RECT 0.2105 63.1435 12.705 63.1749 ;
		END

		PORT
			 LAYER M4 ;
			RECT 0.2105 0.0533 12.705 0.0847 ;
		END

	END VDDPE

	PIN VSSE
		USE GROUND ;
		DIRECTION INOUT ;
		PORT
			 LAYER M4 ;
			RECT 0.2105 27.1216 12.705 27.1529 ;
		END

		PORT
			 LAYER M4 ;
			RECT 0.2105 34.4941 12.705 34.5255 ;
		END

		PORT
			 LAYER M4 ;
			RECT 0.2105 63.0808 12.705 63.1122 ;
		END

		PORT
			 LAYER M4 ;
			RECT 0.2105 0.1161 12.705 0.1475 ;
		END

		PORT
			 LAYER M4 ;
			RECT 0.2105 27.3098 12.705 27.3569 ;
		END

		PORT
			 LAYER M4 ;
			RECT 0.2105 27.7129 12.705 27.76 ;
		END

		PORT
			 LAYER M4 ;
			RECT 0.2105 28.4533 12.705 28.5004 ;
		END

		PORT
			 LAYER M4 ;
			RECT 0.2105 28.9804 12.705 29.0275 ;
		END

		PORT
			 LAYER M4 ;
			RECT 0.2105 29.5075 12.705 29.5545 ;
		END

		PORT
			 LAYER M4 ;
			RECT 0.2105 30.0345 12.705 30.0816 ;
		END

		PORT
			 LAYER M4 ;
			RECT 0.2105 31.0886 12.705 31.1357 ;
		END

		PORT
			 LAYER M4 ;
			RECT 0.2105 32.1427 12.705 32.1898 ;
		END

		PORT
			 LAYER M4 ;
			RECT 0.2105 32.6698 12.705 32.7169 ;
		END

		PORT
			 LAYER M4 ;
			RECT 0.2105 33.1969 12.705 33.2439 ;
		END

		PORT
			 LAYER M4 ;
			RECT 0.2105 33.7239 12.705 33.771 ;
		END

		PORT
			 LAYER M4 ;
			RECT 0.2105 34.0941 12.705 34.1412 ;
		END

		PORT
			 LAYER M4 ;
			RECT 0.2105 62.9396 12.705 62.9867 ;
		END

		PORT
			 LAYER M4 ;
			RECT 0.2105 43.1749 12.705 43.222 ;
		END

		PORT
			 LAYER M4 ;
			RECT 0.2105 42.3843 12.705 42.4314 ;
		END

		PORT
			 LAYER M4 ;
			RECT 0.2105 61.3584 12.705 61.4055 ;
		END

		PORT
			 LAYER M4 ;
			RECT 0.2105 41.5937 12.705 41.6408 ;
		END

		PORT
			 LAYER M4 ;
			RECT 0.2105 40.8031 12.705 40.8502 ;
		END

		PORT
			 LAYER M4 ;
			RECT 0.2105 40.0125 12.705 40.0596 ;
		END

		PORT
			 LAYER M4 ;
			RECT 0.2105 39.222 12.705 39.269 ;
		END

		PORT
			 LAYER M4 ;
			RECT 0.2105 38.4314 12.705 38.4784 ;
		END

		PORT
			 LAYER M4 ;
			RECT 0.2105 37.6408 12.705 37.6878 ;
		END

		PORT
			 LAYER M4 ;
			RECT 0.2105 36.8502 12.705 36.8973 ;
		END

		PORT
			 LAYER M4 ;
			RECT 0.2105 36.0596 12.705 36.1067 ;
		END

		PORT
			 LAYER M4 ;
			RECT 0.2105 35.269 12.705 35.3161 ;
		END

		PORT
			 LAYER M4 ;
			RECT 0.2105 60.5678 12.705 60.6149 ;
		END

		PORT
			 LAYER M4 ;
			RECT 0.2105 26.331 12.705 26.378 ;
		END

		PORT
			 LAYER M4 ;
			RECT 0.2105 25.5404 12.705 25.5875 ;
		END

		PORT
			 LAYER M4 ;
			RECT 0.2105 59.7773 12.705 59.8243 ;
		END

		PORT
			 LAYER M4 ;
			RECT 0.2105 24.7498 12.705 24.7969 ;
		END

		PORT
			 LAYER M4 ;
			RECT 0.2105 23.9592 12.705 24.0063 ;
		END

		PORT
			 LAYER M4 ;
			RECT 0.2105 23.1686 12.705 23.2157 ;
		END

		PORT
			 LAYER M4 ;
			RECT 0.2105 22.378 12.705 22.4251 ;
		END

		PORT
			 LAYER M4 ;
			RECT 0.2105 21.5875 12.705 21.6345 ;
		END

		PORT
			 LAYER M4 ;
			RECT 0.2105 20.7969 12.705 20.8439 ;
		END

		PORT
			 LAYER M4 ;
			RECT 0.2105 20.0063 12.705 20.0533 ;
		END

		PORT
			 LAYER M4 ;
			RECT 0.2105 19.2157 12.705 19.2627 ;
		END

		PORT
			 LAYER M4 ;
			RECT 0.2105 18.4251 12.705 18.4722 ;
		END

		PORT
			 LAYER M4 ;
			RECT 0.2105 17.6345 12.705 17.6816 ;
		END

		PORT
			 LAYER M4 ;
			RECT 0.2105 58.9867 12.705 59.0337 ;
		END

		PORT
			 LAYER M4 ;
			RECT 0.2105 16.8439 12.705 16.891 ;
		END

		PORT
			 LAYER M4 ;
			RECT 0.2105 16.0533 12.705 16.1004 ;
		END

		PORT
			 LAYER M4 ;
			RECT 0.2105 15.2627 12.705 15.3098 ;
		END

		PORT
			 LAYER M4 ;
			RECT 0.2105 14.4722 12.705 14.5192 ;
		END

		PORT
			 LAYER M4 ;
			RECT 0.2105 13.6816 12.705 13.7286 ;
		END

		PORT
			 LAYER M4 ;
			RECT 0.2105 12.891 12.705 12.938 ;
		END

		PORT
			 LAYER M4 ;
			RECT 0.2105 12.1004 12.705 12.1475 ;
		END

		PORT
			 LAYER M4 ;
			RECT 0.2105 11.3098 12.705 11.3569 ;
		END

		PORT
			 LAYER M4 ;
			RECT 0.2105 10.5192 12.705 10.5663 ;
		END

		PORT
			 LAYER M4 ;
			RECT 0.2105 9.7286 12.705 9.7757 ;
		END

		PORT
			 LAYER M4 ;
			RECT 0.2105 58.1961 12.705 58.2431 ;
		END

		PORT
			 LAYER M4 ;
			RECT 0.2105 8.938 12.705 8.9851 ;
		END

		PORT
			 LAYER M4 ;
			RECT 0.2105 8.1475 12.705 8.1945 ;
		END

		PORT
			 LAYER M4 ;
			RECT 0.2105 7.3569 12.705 7.4039 ;
		END

		PORT
			 LAYER M4 ;
			RECT 0.2105 6.5663 12.705 6.6133 ;
		END

		PORT
			 LAYER M4 ;
			RECT 0.2105 5.7757 12.705 5.8227 ;
		END

		PORT
			 LAYER M4 ;
			RECT 0.2105 4.9851 12.705 5.0322 ;
		END

		PORT
			 LAYER M4 ;
			RECT 0.2105 4.1945 12.705 4.2416 ;
		END

		PORT
			 LAYER M4 ;
			RECT 0.2105 3.4039 12.705 3.451 ;
		END

		PORT
			 LAYER M4 ;
			RECT 0.2105 2.6133 12.705 2.6604 ;
		END

		PORT
			 LAYER M4 ;
			RECT 0.2105 1.8227 12.705 1.8698 ;
		END

		PORT
			 LAYER M4 ;
			RECT 0.2105 57.4055 12.705 57.4525 ;
		END

		PORT
			 LAYER M4 ;
			RECT 0.2105 1.0322 12.705 1.0792 ;
		END

		PORT
			 LAYER M4 ;
			RECT 0.2105 0.2416 12.705 0.2886 ;
		END

		PORT
			 LAYER M4 ;
			RECT 0.2105 56.6149 12.705 56.662 ;
		END

		PORT
			 LAYER M4 ;
			RECT 0.2105 55.8243 12.705 55.8714 ;
		END

		PORT
			 LAYER M4 ;
			RECT 0.2105 55.0337 12.705 55.0808 ;
		END

		PORT
			 LAYER M4 ;
			RECT 0.2105 54.2431 12.705 54.2902 ;
		END

		PORT
			 LAYER M4 ;
			RECT 0.2105 53.4525 12.705 53.4996 ;
		END

		PORT
			 LAYER M4 ;
			RECT 0.2105 52.662 12.705 52.709 ;
		END

		PORT
			 LAYER M4 ;
			RECT 0.2105 51.8714 12.705 51.9184 ;
		END

		PORT
			 LAYER M4 ;
			RECT 0.2105 51.0808 12.705 51.1278 ;
		END

		PORT
			 LAYER M4 ;
			RECT 0.2105 50.2902 12.705 50.3373 ;
		END

		PORT
			 LAYER M4 ;
			RECT 0.2105 62.149 12.705 62.1961 ;
		END

		PORT
			 LAYER M4 ;
			RECT 0.2105 49.4996 12.705 49.5467 ;
		END

		PORT
			 LAYER M4 ;
			RECT 0.2105 48.709 12.705 48.7561 ;
		END

		PORT
			 LAYER M4 ;
			RECT 0.2105 47.9184 12.705 47.9655 ;
		END

		PORT
			 LAYER M4 ;
			RECT 0.2105 47.1278 12.705 47.1749 ;
		END

		PORT
			 LAYER M4 ;
			RECT 0.2105 46.3373 12.705 46.3843 ;
		END

		PORT
			 LAYER M4 ;
			RECT 0.2105 45.5467 12.705 45.5937 ;
		END

		PORT
			 LAYER M4 ;
			RECT 0.2105 44.7561 12.705 44.8031 ;
		END

		PORT
			 LAYER M4 ;
			RECT 0.2105 43.9655 12.705 44.0125 ;
		END

	END VSSE

	PIN WENA[0]
		USE SIGNAL ;
		DIRECTION INPUT ;
		SHAPE ABUTMENT ;
		PORT
			 LAYER M2 ;
			RECT 0.0098 1.1796 0.0481 1.2173 ;
			 LAYER M3 ;
			RECT 0.0098 1.1796 0.0481 1.28 ;
			 LAYER V2 ;
			RECT 0.0215 1.1925 0.0364 1.2051 ;
		END

		ANTENNAGATEAREA 0.00027817 ;
		ANTENNADIFFAREA 0.00194719 ;
		ANTENNAPARTIALMETALAREA 0.00195671 ;
	END WENA[0]

	PIN WENA[10]
		USE SIGNAL ;
		DIRECTION INPUT ;
		SHAPE ABUTMENT ;
		PORT
			 LAYER M2 ;
			RECT 0.0098 16.9914 0.0481 17.029 ;
			 LAYER M3 ;
			RECT 0.0098 16.9914 0.0481 17.0918 ;
			 LAYER V2 ;
			RECT 0.0215 17.0043 0.0364 17.0169 ;
		END

		ANTENNAGATEAREA 0.00027817 ;
		ANTENNADIFFAREA 0.00194719 ;
		ANTENNAPARTIALMETALAREA 0.00195671 ;
	END WENA[10]

	PIN WENA[11]
		USE SIGNAL ;
		DIRECTION INPUT ;
		SHAPE ABUTMENT ;
		PORT
			 LAYER M2 ;
			RECT 0.0098 18.5725 0.0481 18.6102 ;
			 LAYER M3 ;
			RECT 0.0098 18.5725 0.0481 18.6729 ;
			 LAYER V2 ;
			RECT 0.0215 18.5855 0.0364 18.598 ;
		END

		ANTENNAGATEAREA 0.00027817 ;
		ANTENNADIFFAREA 0.00194719 ;
		ANTENNAPARTIALMETALAREA 0.00195671 ;
	END WENA[11]

	PIN WENA[12]
		USE SIGNAL ;
		DIRECTION INPUT ;
		SHAPE ABUTMENT ;
		PORT
			 LAYER M2 ;
			RECT 0.0098 20.1537 0.0481 20.1914 ;
			 LAYER M3 ;
			RECT 0.0098 20.1537 0.0481 20.2541 ;
			 LAYER V2 ;
			RECT 0.0215 20.1667 0.0364 20.1792 ;
		END

		ANTENNAGATEAREA 0.00027817 ;
		ANTENNADIFFAREA 0.00194719 ;
		ANTENNAPARTIALMETALAREA 0.00195671 ;
	END WENA[12]

	PIN WENA[13]
		USE SIGNAL ;
		DIRECTION INPUT ;
		SHAPE ABUTMENT ;
		PORT
			 LAYER M2 ;
			RECT 0.0098 21.7349 0.0481 21.7725 ;
			 LAYER M3 ;
			RECT 0.0098 21.7349 0.0481 21.8353 ;
			 LAYER V2 ;
			RECT 0.0215 21.7478 0.0364 21.7604 ;
		END

		ANTENNAGATEAREA 0.00027817 ;
		ANTENNADIFFAREA 0.00194719 ;
		ANTENNAPARTIALMETALAREA 0.00195671 ;
	END WENA[13]

	PIN WENA[14]
		USE SIGNAL ;
		DIRECTION INPUT ;
		SHAPE ABUTMENT ;
		PORT
			 LAYER M2 ;
			RECT 0.0098 23.3161 0.0481 23.3537 ;
			 LAYER M3 ;
			RECT 0.0098 23.3161 0.0481 23.4165 ;
			 LAYER V2 ;
			RECT 0.0215 23.329 0.0364 23.3416 ;
		END

		ANTENNAGATEAREA 0.00027817 ;
		ANTENNADIFFAREA 0.00194719 ;
		ANTENNAPARTIALMETALAREA 0.00195671 ;
	END WENA[14]

	PIN WENA[15]
		USE SIGNAL ;
		DIRECTION INPUT ;
		SHAPE ABUTMENT ;
		PORT
			 LAYER M2 ;
			RECT 0.0098 24.8973 0.0481 24.9349 ;
			 LAYER M3 ;
			RECT 0.0098 24.8973 0.0481 24.9976 ;
			 LAYER V2 ;
			RECT 0.0215 24.9102 0.0364 24.9227 ;
		END

		ANTENNAGATEAREA 0.00027817 ;
		ANTENNADIFFAREA 0.00194719 ;
		ANTENNAPARTIALMETALAREA 0.00195671 ;
	END WENA[15]

	PIN WENA[16]
		USE SIGNAL ;
		DIRECTION INPUT ;
		SHAPE ABUTMENT ;
		PORT
			 LAYER M2 ;
			RECT 0.0098 36.7122 0.0481 36.7498 ;
			 LAYER M3 ;
			RECT 0.0098 36.6494 0.0481 36.7498 ;
			 LAYER V2 ;
			RECT 0.0215 36.7243 0.0364 36.7369 ;
		END

		ANTENNAGATEAREA 0.00027817 ;
		ANTENNADIFFAREA 0.00194719 ;
		ANTENNAPARTIALMETALAREA 0.00195671 ;
	END WENA[16]

	PIN WENA[17]
		USE SIGNAL ;
		DIRECTION INPUT ;
		SHAPE ABUTMENT ;
		PORT
			 LAYER M2 ;
			RECT 0.0098 38.2933 0.0481 38.331 ;
			 LAYER M3 ;
			RECT 0.0098 38.2306 0.0481 38.331 ;
			 LAYER V2 ;
			RECT 0.0215 38.3055 0.0364 38.318 ;
		END

		ANTENNAGATEAREA 0.00027817 ;
		ANTENNADIFFAREA 0.00194719 ;
		ANTENNAPARTIALMETALAREA 0.00195671 ;
	END WENA[17]

	PIN WENA[18]
		USE SIGNAL ;
		DIRECTION INPUT ;
		SHAPE ABUTMENT ;
		PORT
			 LAYER M2 ;
			RECT 0.0098 39.8745 0.0481 39.9122 ;
			 LAYER M3 ;
			RECT 0.0098 39.8118 0.0481 39.9122 ;
			 LAYER V2 ;
			RECT 0.0215 39.8867 0.0364 39.8992 ;
		END

		ANTENNAGATEAREA 0.00027817 ;
		ANTENNADIFFAREA 0.00194719 ;
		ANTENNAPARTIALMETALAREA 0.00195671 ;
	END WENA[18]

	PIN WENA[19]
		USE SIGNAL ;
		DIRECTION INPUT ;
		SHAPE ABUTMENT ;
		PORT
			 LAYER M2 ;
			RECT 0.0098 41.4557 0.0481 41.4933 ;
			 LAYER M3 ;
			RECT 0.0098 41.3929 0.0481 41.4933 ;
			 LAYER V2 ;
			RECT 0.0215 41.4678 0.0364 41.4804 ;
		END

		ANTENNAGATEAREA 0.00027817 ;
		ANTENNADIFFAREA 0.00194719 ;
		ANTENNAPARTIALMETALAREA 0.00195671 ;
	END WENA[19]

	PIN WENA[1]
		USE SIGNAL ;
		DIRECTION INPUT ;
		SHAPE ABUTMENT ;
		PORT
			 LAYER M2 ;
			RECT 0.0098 2.7608 0.0481 2.7984 ;
			 LAYER M3 ;
			RECT 0.0098 2.7608 0.0481 2.8612 ;
			 LAYER V2 ;
			RECT 0.0215 2.7737 0.0364 2.7863 ;
		END

		ANTENNAGATEAREA 0.00027817 ;
		ANTENNADIFFAREA 0.00194719 ;
		ANTENNAPARTIALMETALAREA 0.00195671 ;
	END WENA[1]

	PIN WENA[20]
		USE SIGNAL ;
		DIRECTION INPUT ;
		SHAPE ABUTMENT ;
		PORT
			 LAYER M2 ;
			RECT 0.0098 43.0369 0.0481 43.0745 ;
			 LAYER M3 ;
			RECT 0.0098 42.9741 0.0481 43.0745 ;
			 LAYER V2 ;
			RECT 0.0215 43.049 0.0364 43.0616 ;
		END

		ANTENNAGATEAREA 0.00027817 ;
		ANTENNADIFFAREA 0.00194719 ;
		ANTENNAPARTIALMETALAREA 0.00195671 ;
	END WENA[20]

	PIN WENA[21]
		USE SIGNAL ;
		DIRECTION INPUT ;
		SHAPE ABUTMENT ;
		PORT
			 LAYER M2 ;
			RECT 0.0098 44.618 0.0481 44.6557 ;
			 LAYER M3 ;
			RECT 0.0098 44.5553 0.0481 44.6557 ;
			 LAYER V2 ;
			RECT 0.0215 44.6302 0.0364 44.6427 ;
		END

		ANTENNAGATEAREA 0.00027817 ;
		ANTENNADIFFAREA 0.00194719 ;
		ANTENNAPARTIALMETALAREA 0.00195671 ;
	END WENA[21]

	PIN WENA[22]
		USE SIGNAL ;
		DIRECTION INPUT ;
		SHAPE ABUTMENT ;
		PORT
			 LAYER M2 ;
			RECT 0.0098 46.1992 0.0481 46.2369 ;
			 LAYER M3 ;
			RECT 0.0098 46.1365 0.0481 46.2369 ;
			 LAYER V2 ;
			RECT 0.0215 46.2114 0.0364 46.2239 ;
		END

		ANTENNAGATEAREA 0.00027817 ;
		ANTENNADIFFAREA 0.00194719 ;
		ANTENNAPARTIALMETALAREA 0.00195671 ;
	END WENA[22]

	PIN WENA[23]
		USE SIGNAL ;
		DIRECTION INPUT ;
		SHAPE ABUTMENT ;
		PORT
			 LAYER M2 ;
			RECT 0.0098 47.7804 0.0481 47.818 ;
			 LAYER M3 ;
			RECT 0.0098 47.7176 0.0481 47.818 ;
			 LAYER V2 ;
			RECT 0.0215 47.7925 0.0364 47.8051 ;
		END

		ANTENNAGATEAREA 0.00027817 ;
		ANTENNADIFFAREA 0.00194719 ;
		ANTENNAPARTIALMETALAREA 0.00195671 ;
	END WENA[23]

	PIN WENA[24]
		USE SIGNAL ;
		DIRECTION INPUT ;
		SHAPE ABUTMENT ;
		PORT
			 LAYER M2 ;
			RECT 0.0098 49.3616 0.0481 49.3992 ;
			 LAYER M3 ;
			RECT 0.0098 49.2988 0.0481 49.3992 ;
			 LAYER V2 ;
			RECT 0.0215 49.3737 0.0364 49.3863 ;
		END

		ANTENNAGATEAREA 0.00027817 ;
		ANTENNADIFFAREA 0.00194719 ;
		ANTENNAPARTIALMETALAREA 0.00195671 ;
	END WENA[24]

	PIN WENA[25]
		USE SIGNAL ;
		DIRECTION INPUT ;
		SHAPE ABUTMENT ;
		PORT
			 LAYER M2 ;
			RECT 0.0098 50.9427 0.0481 50.9804 ;
			 LAYER M3 ;
			RECT 0.0098 50.88 0.0481 50.9804 ;
			 LAYER V2 ;
			RECT 0.0215 50.9549 0.0364 50.9675 ;
		END

		ANTENNAGATEAREA 0.00027817 ;
		ANTENNADIFFAREA 0.00194719 ;
		ANTENNAPARTIALMETALAREA 0.00195671 ;
	END WENA[25]

	PIN WENA[26]
		USE SIGNAL ;
		DIRECTION INPUT ;
		SHAPE ABUTMENT ;
		PORT
			 LAYER M2 ;
			RECT 0.0098 52.5239 0.0481 52.5616 ;
			 LAYER M3 ;
			RECT 0.0098 52.4612 0.0481 52.5616 ;
			 LAYER V2 ;
			RECT 0.0215 52.5361 0.0364 52.5486 ;
		END

		ANTENNAGATEAREA 0.00027817 ;
		ANTENNADIFFAREA 0.00194719 ;
		ANTENNAPARTIALMETALAREA 0.00195671 ;
	END WENA[26]

	PIN WENA[27]
		USE SIGNAL ;
		DIRECTION INPUT ;
		SHAPE ABUTMENT ;
		PORT
			 LAYER M2 ;
			RECT 0.0098 54.1051 0.0481 54.1427 ;
			 LAYER M3 ;
			RECT 0.0098 54.0424 0.0481 54.1427 ;
			 LAYER V2 ;
			RECT 0.0215 54.1173 0.0364 54.1298 ;
		END

		ANTENNAGATEAREA 0.00027817 ;
		ANTENNADIFFAREA 0.00194719 ;
		ANTENNAPARTIALMETALAREA 0.00195671 ;
	END WENA[27]

	PIN WENA[28]
		USE SIGNAL ;
		DIRECTION INPUT ;
		SHAPE ABUTMENT ;
		PORT
			 LAYER M2 ;
			RECT 0.0098 55.6863 0.0481 55.7239 ;
			 LAYER M3 ;
			RECT 0.0098 55.6235 0.0481 55.7239 ;
			 LAYER V2 ;
			RECT 0.0215 55.6984 0.0364 55.711 ;
		END

		ANTENNAGATEAREA 0.00027817 ;
		ANTENNADIFFAREA 0.00194719 ;
		ANTENNAPARTIALMETALAREA 0.00195671 ;
	END WENA[28]

	PIN WENA[29]
		USE SIGNAL ;
		DIRECTION INPUT ;
		SHAPE ABUTMENT ;
		PORT
			 LAYER M2 ;
			RECT 0.0098 57.2675 0.0481 57.3051 ;
			 LAYER M3 ;
			RECT 0.0098 57.2047 0.0481 57.3051 ;
			 LAYER V2 ;
			RECT 0.0215 57.2796 0.0364 57.2922 ;
		END

		ANTENNAGATEAREA 0.00027817 ;
		ANTENNADIFFAREA 0.00194719 ;
		ANTENNAPARTIALMETALAREA 0.00195671 ;
	END WENA[29]

	PIN WENA[2]
		USE SIGNAL ;
		DIRECTION INPUT ;
		SHAPE ABUTMENT ;
		PORT
			 LAYER M2 ;
			RECT 0.0098 4.342 0.0481 4.3796 ;
			 LAYER M3 ;
			RECT 0.0098 4.342 0.0481 4.4424 ;
			 LAYER V2 ;
			RECT 0.0215 4.3549 0.0364 4.3675 ;
		END

		ANTENNAGATEAREA 0.00027817 ;
		ANTENNADIFFAREA 0.00194719 ;
		ANTENNAPARTIALMETALAREA 0.00195671 ;
	END WENA[2]

	PIN WENA[30]
		USE SIGNAL ;
		DIRECTION INPUT ;
		SHAPE ABUTMENT ;
		PORT
			 LAYER M2 ;
			RECT 0.0098 58.8486 0.0481 58.8863 ;
			 LAYER M3 ;
			RECT 0.0098 58.7859 0.0481 58.8863 ;
			 LAYER V2 ;
			RECT 0.0215 58.8608 0.0364 58.8733 ;
		END

		ANTENNAGATEAREA 0.00027817 ;
		ANTENNADIFFAREA 0.00194719 ;
		ANTENNAPARTIALMETALAREA 0.00195671 ;
	END WENA[30]

	PIN WENA[31]
		USE SIGNAL ;
		DIRECTION INPUT ;
		SHAPE ABUTMENT ;
		PORT
			 LAYER M2 ;
			RECT 0.0098 60.4298 0.0481 60.4675 ;
			 LAYER M3 ;
			RECT 0.0098 60.3671 0.0481 60.4675 ;
			 LAYER V2 ;
			RECT 0.0215 60.442 0.0364 60.4545 ;
		END

		ANTENNAGATEAREA 0.00027817 ;
		ANTENNADIFFAREA 0.00194719 ;
		ANTENNAPARTIALMETALAREA 0.00195671 ;
	END WENA[31]

	PIN WENA[32]
		USE SIGNAL ;
		DIRECTION INPUT ;
		SHAPE ABUTMENT ;
		PORT
			 LAYER M2 ;
			RECT 0.0098 62.011 0.0481 62.0486 ;
			 LAYER M3 ;
			RECT 0.0098 61.9482 0.0481 62.0486 ;
			 LAYER V2 ;
			RECT 0.0215 62.0231 0.0364 62.0357 ;
		END

		ANTENNAGATEAREA 0.00027817 ;
		ANTENNADIFFAREA 0.00194719 ;
		ANTENNAPARTIALMETALAREA 0.00195671 ;
	END WENA[32]

	PIN WENA[3]
		USE SIGNAL ;
		DIRECTION INPUT ;
		SHAPE ABUTMENT ;
		PORT
			 LAYER M2 ;
			RECT 0.0098 5.9231 0.0481 5.9608 ;
			 LAYER M3 ;
			RECT 0.0098 5.9231 0.0481 6.0235 ;
			 LAYER V2 ;
			RECT 0.0215 5.9361 0.0364 5.9486 ;
		END

		ANTENNAGATEAREA 0.00027817 ;
		ANTENNADIFFAREA 0.00194719 ;
		ANTENNAPARTIALMETALAREA 0.00195671 ;
	END WENA[3]

	PIN WENA[4]
		USE SIGNAL ;
		DIRECTION INPUT ;
		SHAPE ABUTMENT ;
		PORT
			 LAYER M2 ;
			RECT 0.0098 7.5043 0.0481 7.542 ;
			 LAYER M3 ;
			RECT 0.0098 7.5043 0.0481 7.6047 ;
			 LAYER V2 ;
			RECT 0.0215 7.5173 0.0364 7.5298 ;
		END

		ANTENNAGATEAREA 0.00027817 ;
		ANTENNADIFFAREA 0.00194719 ;
		ANTENNAPARTIALMETALAREA 0.00195671 ;
	END WENA[4]

	PIN WENA[5]
		USE SIGNAL ;
		DIRECTION INPUT ;
		SHAPE ABUTMENT ;
		PORT
			 LAYER M2 ;
			RECT 0.0098 9.0855 0.0481 9.1231 ;
			 LAYER M3 ;
			RECT 0.0098 9.0855 0.0481 9.1859 ;
			 LAYER V2 ;
			RECT 0.0215 9.0984 0.0364 9.111 ;
		END

		ANTENNAGATEAREA 0.00027817 ;
		ANTENNADIFFAREA 0.00194719 ;
		ANTENNAPARTIALMETALAREA 0.00195671 ;
	END WENA[5]

	PIN WENA[6]
		USE SIGNAL ;
		DIRECTION INPUT ;
		SHAPE ABUTMENT ;
		PORT
			 LAYER M2 ;
			RECT 0.0098 10.6667 0.0481 10.7043 ;
			 LAYER M3 ;
			RECT 0.0098 10.6667 0.0481 10.7671 ;
			 LAYER V2 ;
			RECT 0.0215 10.6796 0.0364 10.6922 ;
		END

		ANTENNAGATEAREA 0.00027817 ;
		ANTENNADIFFAREA 0.00194719 ;
		ANTENNAPARTIALMETALAREA 0.00195671 ;
	END WENA[6]

	PIN WENA[7]
		USE SIGNAL ;
		DIRECTION INPUT ;
		SHAPE ABUTMENT ;
		PORT
			 LAYER M2 ;
			RECT 0.0098 12.2478 0.0481 12.2855 ;
			 LAYER M3 ;
			RECT 0.0098 12.2478 0.0481 12.3482 ;
			 LAYER V2 ;
			RECT 0.0215 12.2608 0.0364 12.2733 ;
		END

		ANTENNAGATEAREA 0.00027817 ;
		ANTENNADIFFAREA 0.00194719 ;
		ANTENNAPARTIALMETALAREA 0.00195671 ;
	END WENA[7]

	PIN WENA[8]
		USE SIGNAL ;
		DIRECTION INPUT ;
		SHAPE ABUTMENT ;
		PORT
			 LAYER M2 ;
			RECT 0.0098 13.829 0.0481 13.8667 ;
			 LAYER M3 ;
			RECT 0.0098 13.829 0.0481 13.9294 ;
			 LAYER V2 ;
			RECT 0.0215 13.842 0.0364 13.8545 ;
		END

		ANTENNAGATEAREA 0.00027817 ;
		ANTENNADIFFAREA 0.00194719 ;
		ANTENNAPARTIALMETALAREA 0.00195671 ;
	END WENA[8]

	PIN WENA[9]
		USE SIGNAL ;
		DIRECTION INPUT ;
		SHAPE ABUTMENT ;
		PORT
			 LAYER M2 ;
			RECT 0.0098 15.4102 0.0481 15.4478 ;
			 LAYER M3 ;
			RECT 0.0098 15.4102 0.0481 15.5106 ;
			 LAYER V2 ;
			RECT 0.0215 15.4231 0.0364 15.4357 ;
		END

		ANTENNAGATEAREA 0.00027817 ;
		ANTENNADIFFAREA 0.00194719 ;
		ANTENNAPARTIALMETALAREA 0.00195671 ;
	END WENA[9]

	PIN WENB[0]
		USE SIGNAL ;
		DIRECTION INPUT ;
		SHAPE ABUTMENT ;
		PORT
			 LAYER M2 ;
			RECT 0.0098 1.029 0.0481 1.0667 ;
		END

		ANTENNAGATEAREA 0.00027817 ;
		ANTENNADIFFAREA 0.00194719 ;
		ANTENNAPARTIALMETALAREA 0.00195671 ;
	END WENB[0]

	PIN WENB[10]
		USE SIGNAL ;
		DIRECTION INPUT ;
		SHAPE ABUTMENT ;
		PORT
			 LAYER M2 ;
			RECT 0.0098 16.8408 0.0481 16.8784 ;
		END

		ANTENNAGATEAREA 0.00027817 ;
		ANTENNADIFFAREA 0.00194719 ;
		ANTENNAPARTIALMETALAREA 0.00195671 ;
	END WENB[10]

	PIN WENB[11]
		USE SIGNAL ;
		DIRECTION INPUT ;
		SHAPE ABUTMENT ;
		PORT
			 LAYER M2 ;
			RECT 0.0098 18.422 0.0481 18.4596 ;
		END

		ANTENNAGATEAREA 0.00027817 ;
		ANTENNADIFFAREA 0.00194719 ;
		ANTENNAPARTIALMETALAREA 0.00195671 ;
	END WENB[11]

	PIN WENB[12]
		USE SIGNAL ;
		DIRECTION INPUT ;
		SHAPE ABUTMENT ;
		PORT
			 LAYER M2 ;
			RECT 0.0098 20.0031 0.0481 20.0408 ;
		END

		ANTENNAGATEAREA 0.00027817 ;
		ANTENNADIFFAREA 0.00194719 ;
		ANTENNAPARTIALMETALAREA 0.00195671 ;
	END WENB[12]

	PIN WENB[13]
		USE SIGNAL ;
		DIRECTION INPUT ;
		SHAPE ABUTMENT ;
		PORT
			 LAYER M2 ;
			RECT 0.0098 21.5843 0.0481 21.622 ;
		END

		ANTENNAGATEAREA 0.00027817 ;
		ANTENNADIFFAREA 0.00194719 ;
		ANTENNAPARTIALMETALAREA 0.00195671 ;
	END WENB[13]

	PIN WENB[14]
		USE SIGNAL ;
		DIRECTION INPUT ;
		SHAPE ABUTMENT ;
		PORT
			 LAYER M2 ;
			RECT 0.0098 23.1655 0.0481 23.2031 ;
		END

		ANTENNAGATEAREA 0.00027817 ;
		ANTENNADIFFAREA 0.00194719 ;
		ANTENNAPARTIALMETALAREA 0.00195671 ;
	END WENB[14]

	PIN WENB[15]
		USE SIGNAL ;
		DIRECTION INPUT ;
		SHAPE ABUTMENT ;
		PORT
			 LAYER M2 ;
			RECT 0.0098 24.7467 0.0481 24.7843 ;
		END

		ANTENNAGATEAREA 0.00027817 ;
		ANTENNADIFFAREA 0.00194719 ;
		ANTENNAPARTIALMETALAREA 0.00195671 ;
	END WENB[15]

	PIN WENB[16]
		USE SIGNAL ;
		DIRECTION INPUT ;
		SHAPE ABUTMENT ;
		PORT
			 LAYER M2 ;
			RECT 0.0098 36.8627 0.0481 36.9004 ;
		END

		ANTENNAGATEAREA 0.00027817 ;
		ANTENNADIFFAREA 0.00194719 ;
		ANTENNAPARTIALMETALAREA 0.00195671 ;
	END WENB[16]

	PIN WENB[17]
		USE SIGNAL ;
		DIRECTION INPUT ;
		SHAPE ABUTMENT ;
		PORT
			 LAYER M2 ;
			RECT 0.0098 38.4439 0.0481 38.4816 ;
		END

		ANTENNAGATEAREA 0.00027817 ;
		ANTENNADIFFAREA 0.00194719 ;
		ANTENNAPARTIALMETALAREA 0.00195671 ;
	END WENB[17]

	PIN WENB[18]
		USE SIGNAL ;
		DIRECTION INPUT ;
		SHAPE ABUTMENT ;
		PORT
			 LAYER M2 ;
			RECT 0.0098 40.0251 0.0481 40.0627 ;
		END

		ANTENNAGATEAREA 0.00027817 ;
		ANTENNADIFFAREA 0.00194719 ;
		ANTENNAPARTIALMETALAREA 0.00195671 ;
	END WENB[18]

	PIN WENB[19]
		USE SIGNAL ;
		DIRECTION INPUT ;
		SHAPE ABUTMENT ;
		PORT
			 LAYER M2 ;
			RECT 0.0098 41.6063 0.0481 41.6439 ;
		END

		ANTENNAGATEAREA 0.00027817 ;
		ANTENNADIFFAREA 0.00194719 ;
		ANTENNAPARTIALMETALAREA 0.00195671 ;
	END WENB[19]

	PIN WENB[1]
		USE SIGNAL ;
		DIRECTION INPUT ;
		SHAPE ABUTMENT ;
		PORT
			 LAYER M2 ;
			RECT 0.0098 2.6102 0.0481 2.6478 ;
		END

		ANTENNAGATEAREA 0.00027817 ;
		ANTENNADIFFAREA 0.00194719 ;
		ANTENNAPARTIALMETALAREA 0.00195671 ;
	END WENB[1]

	PIN WENB[20]
		USE SIGNAL ;
		DIRECTION INPUT ;
		SHAPE ABUTMENT ;
		PORT
			 LAYER M2 ;
			RECT 0.0098 43.1875 0.0481 43.2251 ;
		END

		ANTENNAGATEAREA 0.00027817 ;
		ANTENNADIFFAREA 0.00194719 ;
		ANTENNAPARTIALMETALAREA 0.00195671 ;
	END WENB[20]

	PIN WENB[21]
		USE SIGNAL ;
		DIRECTION INPUT ;
		SHAPE ABUTMENT ;
		PORT
			 LAYER M2 ;
			RECT 0.0098 44.7686 0.0481 44.8063 ;
		END

		ANTENNAGATEAREA 0.00027817 ;
		ANTENNADIFFAREA 0.00194719 ;
		ANTENNAPARTIALMETALAREA 0.00195671 ;
	END WENB[21]

	PIN WENB[22]
		USE SIGNAL ;
		DIRECTION INPUT ;
		SHAPE ABUTMENT ;
		PORT
			 LAYER M2 ;
			RECT 0.0098 46.3498 0.0481 46.3875 ;
		END

		ANTENNAGATEAREA 0.00027817 ;
		ANTENNADIFFAREA 0.00194719 ;
		ANTENNAPARTIALMETALAREA 0.00195671 ;
	END WENB[22]

	PIN WENB[23]
		USE SIGNAL ;
		DIRECTION INPUT ;
		SHAPE ABUTMENT ;
		PORT
			 LAYER M2 ;
			RECT 0.0098 47.931 0.0481 47.9686 ;
		END

		ANTENNAGATEAREA 0.00027817 ;
		ANTENNADIFFAREA 0.00194719 ;
		ANTENNAPARTIALMETALAREA 0.00195671 ;
	END WENB[23]

	PIN WENB[24]
		USE SIGNAL ;
		DIRECTION INPUT ;
		SHAPE ABUTMENT ;
		PORT
			 LAYER M2 ;
			RECT 0.0098 49.5122 0.0481 49.5498 ;
		END

		ANTENNAGATEAREA 0.00027817 ;
		ANTENNADIFFAREA 0.00194719 ;
		ANTENNAPARTIALMETALAREA 0.00195671 ;
	END WENB[24]

	PIN WENB[25]
		USE SIGNAL ;
		DIRECTION INPUT ;
		SHAPE ABUTMENT ;
		PORT
			 LAYER M2 ;
			RECT 0.0098 51.0933 0.0481 51.131 ;
		END

		ANTENNAGATEAREA 0.00027817 ;
		ANTENNADIFFAREA 0.00194719 ;
		ANTENNAPARTIALMETALAREA 0.00195671 ;
	END WENB[25]

	PIN WENB[26]
		USE SIGNAL ;
		DIRECTION INPUT ;
		SHAPE ABUTMENT ;
		PORT
			 LAYER M2 ;
			RECT 0.0098 52.6745 0.0481 52.7122 ;
		END

		ANTENNAGATEAREA 0.00027817 ;
		ANTENNADIFFAREA 0.00194719 ;
		ANTENNAPARTIALMETALAREA 0.00195671 ;
	END WENB[26]

	PIN WENB[27]
		USE SIGNAL ;
		DIRECTION INPUT ;
		SHAPE ABUTMENT ;
		PORT
			 LAYER M2 ;
			RECT 0.0098 54.2557 0.0481 54.2933 ;
		END

		ANTENNAGATEAREA 0.00027817 ;
		ANTENNADIFFAREA 0.00194719 ;
		ANTENNAPARTIALMETALAREA 0.00195671 ;
	END WENB[27]

	PIN WENB[28]
		USE SIGNAL ;
		DIRECTION INPUT ;
		SHAPE ABUTMENT ;
		PORT
			 LAYER M2 ;
			RECT 0.0098 55.8369 0.0481 55.8745 ;
		END

		ANTENNAGATEAREA 0.00027817 ;
		ANTENNADIFFAREA 0.00194719 ;
		ANTENNAPARTIALMETALAREA 0.00195671 ;
	END WENB[28]

	PIN WENB[29]
		USE SIGNAL ;
		DIRECTION INPUT ;
		SHAPE ABUTMENT ;
		PORT
			 LAYER M2 ;
			RECT 0.0098 57.418 0.0481 57.4557 ;
		END

		ANTENNAGATEAREA 0.00027817 ;
		ANTENNADIFFAREA 0.00194719 ;
		ANTENNAPARTIALMETALAREA 0.00195671 ;
	END WENB[29]

	PIN WENB[2]
		USE SIGNAL ;
		DIRECTION INPUT ;
		SHAPE ABUTMENT ;
		PORT
			 LAYER M2 ;
			RECT 0.0098 4.1914 0.0481 4.229 ;
		END

		ANTENNAGATEAREA 0.00027817 ;
		ANTENNADIFFAREA 0.00194719 ;
		ANTENNAPARTIALMETALAREA 0.00195671 ;
	END WENB[2]

	PIN WENB[30]
		USE SIGNAL ;
		DIRECTION INPUT ;
		SHAPE ABUTMENT ;
		PORT
			 LAYER M2 ;
			RECT 0.0098 58.9992 0.0481 59.0369 ;
		END

		ANTENNAGATEAREA 0.00027817 ;
		ANTENNADIFFAREA 0.00194719 ;
		ANTENNAPARTIALMETALAREA 0.00195671 ;
	END WENB[30]

	PIN WENB[31]
		USE SIGNAL ;
		DIRECTION INPUT ;
		SHAPE ABUTMENT ;
		PORT
			 LAYER M2 ;
			RECT 0.0098 60.5804 0.0481 60.618 ;
		END

		ANTENNAGATEAREA 0.00027817 ;
		ANTENNADIFFAREA 0.00194719 ;
		ANTENNAPARTIALMETALAREA 0.00195671 ;
	END WENB[31]

	PIN WENB[32]
		USE SIGNAL ;
		DIRECTION INPUT ;
		SHAPE ABUTMENT ;
		PORT
			 LAYER M2 ;
			RECT 0.0098 62.1616 0.0481 62.1992 ;
		END

		ANTENNAGATEAREA 0.00027817 ;
		ANTENNADIFFAREA 0.00194719 ;
		ANTENNAPARTIALMETALAREA 0.00195671 ;
	END WENB[32]

	PIN WENB[3]
		USE SIGNAL ;
		DIRECTION INPUT ;
		SHAPE ABUTMENT ;
		PORT
			 LAYER M2 ;
			RECT 0.0098 5.7725 0.0481 5.8102 ;
		END

		ANTENNAGATEAREA 0.00027817 ;
		ANTENNADIFFAREA 0.00194719 ;
		ANTENNAPARTIALMETALAREA 0.00195671 ;
	END WENB[3]

	PIN WENB[4]
		USE SIGNAL ;
		DIRECTION INPUT ;
		SHAPE ABUTMENT ;
		PORT
			 LAYER M2 ;
			RECT 0.0098 7.3537 0.0481 7.3914 ;
		END

		ANTENNAGATEAREA 0.00027817 ;
		ANTENNADIFFAREA 0.00194719 ;
		ANTENNAPARTIALMETALAREA 0.00195671 ;
	END WENB[4]

	PIN WENB[5]
		USE SIGNAL ;
		DIRECTION INPUT ;
		SHAPE ABUTMENT ;
		PORT
			 LAYER M2 ;
			RECT 0.0098 8.9349 0.0481 8.9725 ;
		END

		ANTENNAGATEAREA 0.00027817 ;
		ANTENNADIFFAREA 0.00194719 ;
		ANTENNAPARTIALMETALAREA 0.00195671 ;
	END WENB[5]

	PIN WENB[6]
		USE SIGNAL ;
		DIRECTION INPUT ;
		SHAPE ABUTMENT ;
		PORT
			 LAYER M2 ;
			RECT 0.0098 10.5161 0.0481 10.5537 ;
		END

		ANTENNAGATEAREA 0.00027817 ;
		ANTENNADIFFAREA 0.00194719 ;
		ANTENNAPARTIALMETALAREA 0.00195671 ;
	END WENB[6]

	PIN WENB[7]
		USE SIGNAL ;
		DIRECTION INPUT ;
		SHAPE ABUTMENT ;
		PORT
			 LAYER M2 ;
			RECT 0.0098 12.0973 0.0481 12.1349 ;
		END

		ANTENNAGATEAREA 0.00027817 ;
		ANTENNADIFFAREA 0.00194719 ;
		ANTENNAPARTIALMETALAREA 0.00195671 ;
	END WENB[7]

	PIN WENB[8]
		USE SIGNAL ;
		DIRECTION INPUT ;
		SHAPE ABUTMENT ;
		PORT
			 LAYER M2 ;
			RECT 0.0098 13.6784 0.0481 13.7161 ;
		END

		ANTENNAGATEAREA 0.00027817 ;
		ANTENNADIFFAREA 0.00194719 ;
		ANTENNAPARTIALMETALAREA 0.00195671 ;
	END WENB[8]

	PIN WENB[9]
		USE SIGNAL ;
		DIRECTION INPUT ;
		SHAPE ABUTMENT ;
		PORT
			 LAYER M2 ;
			RECT 0.0098 15.2596 0.0481 15.2973 ;
		END

		ANTENNAGATEAREA 0.00027817 ;
		ANTENNADIFFAREA 0.00194719 ;
		ANTENNAPARTIALMETALAREA 0.00195671 ;
	END WENB[9]

	PIN WENYA[0]
		USE SIGNAL ;
		DIRECTION OUTPUT ;
		SHAPE ABUTMENT ;
		PORT
			 LAYER M2 ;
			RECT 0.0098 1.3302 0.0481 1.3678 ;
			 LAYER M3 ;
			RECT 0.0098 1.3302 0.0481 1.4306 ;
			 LAYER V2 ;
			RECT 0.0215 1.3431 0.0364 1.3557 ;
		END

		ANTENNADIFFAREA 0.00194719 ;
		ANTENNAPARTIALMETALAREA 0.00195671 ;
	END WENYA[0]

	PIN WENYA[10]
		USE SIGNAL ;
		DIRECTION OUTPUT ;
		SHAPE ABUTMENT ;
		PORT
			 LAYER M2 ;
			RECT 0.0098 17.142 0.0481 17.1796 ;
			 LAYER M3 ;
			RECT 0.0098 17.142 0.0481 17.2424 ;
			 LAYER V2 ;
			RECT 0.0215 17.1549 0.0364 17.1675 ;
		END

		ANTENNADIFFAREA 0.00194719 ;
		ANTENNAPARTIALMETALAREA 0.00195671 ;
	END WENYA[10]

	PIN WENYA[11]
		USE SIGNAL ;
		DIRECTION OUTPUT ;
		SHAPE ABUTMENT ;
		PORT
			 LAYER M2 ;
			RECT 0.0098 18.7231 0.0481 18.7608 ;
			 LAYER M3 ;
			RECT 0.0098 18.7231 0.0481 18.8235 ;
			 LAYER V2 ;
			RECT 0.0215 18.7361 0.0364 18.7486 ;
		END

		ANTENNADIFFAREA 0.00194719 ;
		ANTENNAPARTIALMETALAREA 0.00195671 ;
	END WENYA[11]

	PIN WENYA[12]
		USE SIGNAL ;
		DIRECTION OUTPUT ;
		SHAPE ABUTMENT ;
		PORT
			 LAYER M2 ;
			RECT 0.0098 20.3043 0.0481 20.342 ;
			 LAYER M3 ;
			RECT 0.0098 20.3043 0.0481 20.4047 ;
			 LAYER V2 ;
			RECT 0.0215 20.3173 0.0364 20.3298 ;
		END

		ANTENNADIFFAREA 0.00194719 ;
		ANTENNAPARTIALMETALAREA 0.00195671 ;
	END WENYA[12]

	PIN WENYA[13]
		USE SIGNAL ;
		DIRECTION OUTPUT ;
		SHAPE ABUTMENT ;
		PORT
			 LAYER M2 ;
			RECT 0.0098 21.8855 0.0481 21.9231 ;
			 LAYER M3 ;
			RECT 0.0098 21.8855 0.0481 21.9859 ;
			 LAYER V2 ;
			RECT 0.0215 21.8984 0.0364 21.911 ;
		END

		ANTENNADIFFAREA 0.00194719 ;
		ANTENNAPARTIALMETALAREA 0.00195671 ;
	END WENYA[13]

	PIN WENYA[14]
		USE SIGNAL ;
		DIRECTION OUTPUT ;
		SHAPE ABUTMENT ;
		PORT
			 LAYER M2 ;
			RECT 0.0098 23.4667 0.0481 23.5043 ;
			 LAYER M3 ;
			RECT 0.0098 23.4667 0.0481 23.5671 ;
			 LAYER V2 ;
			RECT 0.0215 23.4796 0.0364 23.4922 ;
		END

		ANTENNADIFFAREA 0.00194719 ;
		ANTENNAPARTIALMETALAREA 0.00195671 ;
	END WENYA[14]

	PIN WENYA[15]
		USE SIGNAL ;
		DIRECTION OUTPUT ;
		SHAPE ABUTMENT ;
		PORT
			 LAYER M2 ;
			RECT 0.0098 25.0478 0.0481 25.0855 ;
			 LAYER M3 ;
			RECT 0.0098 25.0478 0.0481 25.1482 ;
			 LAYER V2 ;
			RECT 0.0215 25.0608 0.0364 25.0733 ;
		END

		ANTENNADIFFAREA 0.00194719 ;
		ANTENNAPARTIALMETALAREA 0.00195671 ;
	END WENYA[15]

	PIN WENYA[16]
		USE SIGNAL ;
		DIRECTION OUTPUT ;
		SHAPE ABUTMENT ;
		PORT
			 LAYER M2 ;
			RECT 0.0098 36.5616 0.0481 36.5992 ;
			 LAYER M3 ;
			RECT 0.0098 36.4988 0.0481 36.5992 ;
			 LAYER V2 ;
			RECT 0.0215 36.5737 0.0364 36.5863 ;
		END

		ANTENNADIFFAREA 0.00194719 ;
		ANTENNAPARTIALMETALAREA 0.00195671 ;
	END WENYA[16]

	PIN WENYA[17]
		USE SIGNAL ;
		DIRECTION OUTPUT ;
		SHAPE ABUTMENT ;
		PORT
			 LAYER M2 ;
			RECT 0.0098 38.1427 0.0481 38.1804 ;
			 LAYER M3 ;
			RECT 0.0098 38.08 0.0481 38.1804 ;
			 LAYER V2 ;
			RECT 0.0215 38.1549 0.0364 38.1675 ;
		END

		ANTENNADIFFAREA 0.00194719 ;
		ANTENNAPARTIALMETALAREA 0.00195671 ;
	END WENYA[17]

	PIN WENYA[18]
		USE SIGNAL ;
		DIRECTION OUTPUT ;
		SHAPE ABUTMENT ;
		PORT
			 LAYER M2 ;
			RECT 0.0098 39.7239 0.0481 39.7616 ;
			 LAYER M3 ;
			RECT 0.0098 39.6612 0.0481 39.7616 ;
			 LAYER V2 ;
			RECT 0.0215 39.7361 0.0364 39.7486 ;
		END

		ANTENNADIFFAREA 0.00194719 ;
		ANTENNAPARTIALMETALAREA 0.00195671 ;
	END WENYA[18]

	PIN WENYA[19]
		USE SIGNAL ;
		DIRECTION OUTPUT ;
		SHAPE ABUTMENT ;
		PORT
			 LAYER M2 ;
			RECT 0.0098 41.3051 0.0481 41.3427 ;
			 LAYER M3 ;
			RECT 0.0098 41.2424 0.0481 41.3427 ;
			 LAYER V2 ;
			RECT 0.0215 41.3173 0.0364 41.3298 ;
		END

		ANTENNADIFFAREA 0.00194719 ;
		ANTENNAPARTIALMETALAREA 0.00195671 ;
	END WENYA[19]

	PIN WENYA[1]
		USE SIGNAL ;
		DIRECTION OUTPUT ;
		SHAPE ABUTMENT ;
		PORT
			 LAYER M2 ;
			RECT 0.0098 2.9114 0.0481 2.949 ;
			 LAYER M3 ;
			RECT 0.0098 2.9114 0.0481 3.0118 ;
			 LAYER V2 ;
			RECT 0.0215 2.9243 0.0364 2.9369 ;
		END

		ANTENNADIFFAREA 0.00194719 ;
		ANTENNAPARTIALMETALAREA 0.00195671 ;
	END WENYA[1]

	PIN WENYA[20]
		USE SIGNAL ;
		DIRECTION OUTPUT ;
		SHAPE ABUTMENT ;
		PORT
			 LAYER M2 ;
			RECT 0.0098 42.8863 0.0481 42.9239 ;
			 LAYER M3 ;
			RECT 0.0098 42.8235 0.0481 42.9239 ;
			 LAYER V2 ;
			RECT 0.0215 42.8984 0.0364 42.911 ;
		END

		ANTENNADIFFAREA 0.00194719 ;
		ANTENNAPARTIALMETALAREA 0.00195671 ;
	END WENYA[20]

	PIN WENYA[21]
		USE SIGNAL ;
		DIRECTION OUTPUT ;
		SHAPE ABUTMENT ;
		PORT
			 LAYER M2 ;
			RECT 0.0098 44.4675 0.0481 44.5051 ;
			 LAYER M3 ;
			RECT 0.0098 44.4047 0.0481 44.5051 ;
			 LAYER V2 ;
			RECT 0.0215 44.4796 0.0364 44.4922 ;
		END

		ANTENNADIFFAREA 0.00194719 ;
		ANTENNAPARTIALMETALAREA 0.00195671 ;
	END WENYA[21]

	PIN WENYA[22]
		USE SIGNAL ;
		DIRECTION OUTPUT ;
		SHAPE ABUTMENT ;
		PORT
			 LAYER M2 ;
			RECT 0.0098 46.0486 0.0481 46.0863 ;
			 LAYER M3 ;
			RECT 0.0098 45.9859 0.0481 46.0863 ;
			 LAYER V2 ;
			RECT 0.0215 46.0608 0.0364 46.0733 ;
		END

		ANTENNADIFFAREA 0.00194719 ;
		ANTENNAPARTIALMETALAREA 0.00195671 ;
	END WENYA[22]

	PIN WENYA[23]
		USE SIGNAL ;
		DIRECTION OUTPUT ;
		SHAPE ABUTMENT ;
		PORT
			 LAYER M2 ;
			RECT 0.0098 47.6298 0.0481 47.6675 ;
			 LAYER M3 ;
			RECT 0.0098 47.5671 0.0481 47.6675 ;
			 LAYER V2 ;
			RECT 0.0215 47.642 0.0364 47.6545 ;
		END

		ANTENNADIFFAREA 0.00194719 ;
		ANTENNAPARTIALMETALAREA 0.00195671 ;
	END WENYA[23]

	PIN WENYA[24]
		USE SIGNAL ;
		DIRECTION OUTPUT ;
		SHAPE ABUTMENT ;
		PORT
			 LAYER M2 ;
			RECT 0.0098 49.211 0.0481 49.2486 ;
			 LAYER M3 ;
			RECT 0.0098 49.1482 0.0481 49.2486 ;
			 LAYER V2 ;
			RECT 0.0215 49.2231 0.0364 49.2357 ;
		END

		ANTENNADIFFAREA 0.00194719 ;
		ANTENNAPARTIALMETALAREA 0.00195671 ;
	END WENYA[24]

	PIN WENYA[25]
		USE SIGNAL ;
		DIRECTION OUTPUT ;
		SHAPE ABUTMENT ;
		PORT
			 LAYER M2 ;
			RECT 0.0098 50.7922 0.0481 50.8298 ;
			 LAYER M3 ;
			RECT 0.0098 50.7294 0.0481 50.8298 ;
			 LAYER V2 ;
			RECT 0.0215 50.8043 0.0364 50.8169 ;
		END

		ANTENNADIFFAREA 0.00194719 ;
		ANTENNAPARTIALMETALAREA 0.00195671 ;
	END WENYA[25]

	PIN WENYA[26]
		USE SIGNAL ;
		DIRECTION OUTPUT ;
		SHAPE ABUTMENT ;
		PORT
			 LAYER M2 ;
			RECT 0.0098 52.3733 0.0481 52.411 ;
			 LAYER M3 ;
			RECT 0.0098 52.3106 0.0481 52.411 ;
			 LAYER V2 ;
			RECT 0.0215 52.3855 0.0364 52.398 ;
		END

		ANTENNADIFFAREA 0.00194719 ;
		ANTENNAPARTIALMETALAREA 0.00195671 ;
	END WENYA[26]

	PIN WENYA[27]
		USE SIGNAL ;
		DIRECTION OUTPUT ;
		SHAPE ABUTMENT ;
		PORT
			 LAYER M2 ;
			RECT 0.0098 53.9545 0.0481 53.9922 ;
			 LAYER M3 ;
			RECT 0.0098 53.8918 0.0481 53.9922 ;
			 LAYER V2 ;
			RECT 0.0215 53.9667 0.0364 53.9792 ;
		END

		ANTENNADIFFAREA 0.00194719 ;
		ANTENNAPARTIALMETALAREA 0.00195671 ;
	END WENYA[27]

	PIN WENYA[28]
		USE SIGNAL ;
		DIRECTION OUTPUT ;
		SHAPE ABUTMENT ;
		PORT
			 LAYER M2 ;
			RECT 0.0098 55.5357 0.0481 55.5733 ;
			 LAYER M3 ;
			RECT 0.0098 55.4729 0.0481 55.5733 ;
			 LAYER V2 ;
			RECT 0.0215 55.5478 0.0364 55.5604 ;
		END

		ANTENNADIFFAREA 0.00194719 ;
		ANTENNAPARTIALMETALAREA 0.00195671 ;
	END WENYA[28]

	PIN WENYA[29]
		USE SIGNAL ;
		DIRECTION OUTPUT ;
		SHAPE ABUTMENT ;
		PORT
			 LAYER M2 ;
			RECT 0.0098 57.1169 0.0481 57.1545 ;
			 LAYER M3 ;
			RECT 0.0098 57.0541 0.0481 57.1545 ;
			 LAYER V2 ;
			RECT 0.0215 57.129 0.0364 57.1416 ;
		END

		ANTENNADIFFAREA 0.00194719 ;
		ANTENNAPARTIALMETALAREA 0.00195671 ;
	END WENYA[29]

	PIN WENYA[2]
		USE SIGNAL ;
		DIRECTION OUTPUT ;
		SHAPE ABUTMENT ;
		PORT
			 LAYER M2 ;
			RECT 0.0098 4.4925 0.0481 4.5302 ;
			 LAYER M3 ;
			RECT 0.0098 4.4925 0.0481 4.5929 ;
			 LAYER V2 ;
			RECT 0.0215 4.5055 0.0364 4.518 ;
		END

		ANTENNADIFFAREA 0.00194719 ;
		ANTENNAPARTIALMETALAREA 0.00195671 ;
	END WENYA[2]

	PIN WENYA[30]
		USE SIGNAL ;
		DIRECTION OUTPUT ;
		SHAPE ABUTMENT ;
		PORT
			 LAYER M2 ;
			RECT 0.0098 58.698 0.0481 58.7357 ;
			 LAYER M3 ;
			RECT 0.0098 58.6353 0.0481 58.7357 ;
			 LAYER V2 ;
			RECT 0.0215 58.7102 0.0364 58.7227 ;
		END

		ANTENNADIFFAREA 0.00194719 ;
		ANTENNAPARTIALMETALAREA 0.00195671 ;
	END WENYA[30]

	PIN WENYA[31]
		USE SIGNAL ;
		DIRECTION OUTPUT ;
		SHAPE ABUTMENT ;
		PORT
			 LAYER M2 ;
			RECT 0.0098 60.2792 0.0481 60.3169 ;
			 LAYER M3 ;
			RECT 0.0098 60.2165 0.0481 60.3169 ;
			 LAYER V2 ;
			RECT 0.0215 60.2914 0.0364 60.3039 ;
		END

		ANTENNADIFFAREA 0.00194719 ;
		ANTENNAPARTIALMETALAREA 0.00195671 ;
	END WENYA[31]

	PIN WENYA[32]
		USE SIGNAL ;
		DIRECTION OUTPUT ;
		SHAPE ABUTMENT ;
		PORT
			 LAYER M2 ;
			RECT 0.0098 61.8604 0.0481 61.898 ;
			 LAYER M3 ;
			RECT 0.0098 61.7976 0.0481 61.898 ;
			 LAYER V2 ;
			RECT 0.0215 61.8725 0.0364 61.8851 ;
		END

		ANTENNADIFFAREA 0.00194719 ;
		ANTENNAPARTIALMETALAREA 0.00195671 ;
	END WENYA[32]

	PIN WENYA[3]
		USE SIGNAL ;
		DIRECTION OUTPUT ;
		SHAPE ABUTMENT ;
		PORT
			 LAYER M2 ;
			RECT 0.0098 6.0737 0.0481 6.1114 ;
			 LAYER M3 ;
			RECT 0.0098 6.0737 0.0481 6.1741 ;
			 LAYER V2 ;
			RECT 0.0215 6.0867 0.0364 6.0992 ;
		END

		ANTENNADIFFAREA 0.00194719 ;
		ANTENNAPARTIALMETALAREA 0.00195671 ;
	END WENYA[3]

	PIN WENYA[4]
		USE SIGNAL ;
		DIRECTION OUTPUT ;
		SHAPE ABUTMENT ;
		PORT
			 LAYER M2 ;
			RECT 0.0098 7.6549 0.0481 7.6925 ;
			 LAYER M3 ;
			RECT 0.0098 7.6549 0.0481 7.7553 ;
			 LAYER V2 ;
			RECT 0.0215 7.6678 0.0364 7.6804 ;
		END

		ANTENNADIFFAREA 0.00194719 ;
		ANTENNAPARTIALMETALAREA 0.00195671 ;
	END WENYA[4]

	PIN WENYA[5]
		USE SIGNAL ;
		DIRECTION OUTPUT ;
		SHAPE ABUTMENT ;
		PORT
			 LAYER M2 ;
			RECT 0.0098 9.2361 0.0481 9.2737 ;
			 LAYER M3 ;
			RECT 0.0098 9.2361 0.0481 9.3365 ;
			 LAYER V2 ;
			RECT 0.0215 9.249 0.0364 9.2616 ;
		END

		ANTENNADIFFAREA 0.00194719 ;
		ANTENNAPARTIALMETALAREA 0.00195671 ;
	END WENYA[5]

	PIN WENYA[6]
		USE SIGNAL ;
		DIRECTION OUTPUT ;
		SHAPE ABUTMENT ;
		PORT
			 LAYER M2 ;
			RECT 0.0098 10.8173 0.0481 10.8549 ;
			 LAYER M3 ;
			RECT 0.0098 10.8173 0.0481 10.9176 ;
			 LAYER V2 ;
			RECT 0.0215 10.8302 0.0364 10.8427 ;
		END

		ANTENNADIFFAREA 0.00194719 ;
		ANTENNAPARTIALMETALAREA 0.00195671 ;
	END WENYA[6]

	PIN WENYA[7]
		USE SIGNAL ;
		DIRECTION OUTPUT ;
		SHAPE ABUTMENT ;
		PORT
			 LAYER M2 ;
			RECT 0.0098 12.3984 0.0481 12.4361 ;
			 LAYER M3 ;
			RECT 0.0098 12.3984 0.0481 12.4988 ;
			 LAYER V2 ;
			RECT 0.0215 12.4114 0.0364 12.4239 ;
		END

		ANTENNADIFFAREA 0.00194719 ;
		ANTENNAPARTIALMETALAREA 0.00195671 ;
	END WENYA[7]

	PIN WENYA[8]
		USE SIGNAL ;
		DIRECTION OUTPUT ;
		SHAPE ABUTMENT ;
		PORT
			 LAYER M2 ;
			RECT 0.0098 13.9796 0.0481 14.0173 ;
			 LAYER M3 ;
			RECT 0.0098 13.9796 0.0481 14.08 ;
			 LAYER V2 ;
			RECT 0.0215 13.9925 0.0364 14.0051 ;
		END

		ANTENNADIFFAREA 0.00194719 ;
		ANTENNAPARTIALMETALAREA 0.00195671 ;
	END WENYA[8]

	PIN WENYA[9]
		USE SIGNAL ;
		DIRECTION OUTPUT ;
		SHAPE ABUTMENT ;
		PORT
			 LAYER M2 ;
			RECT 0.0098 15.5608 0.0481 15.5984 ;
			 LAYER M3 ;
			RECT 0.0098 15.5608 0.0481 15.6612 ;
			 LAYER V2 ;
			RECT 0.0215 15.5737 0.0364 15.5863 ;
		END

		ANTENNADIFFAREA 0.00194719 ;
		ANTENNAPARTIALMETALAREA 0.00195671 ;
	END WENYA[9]

	PIN WENYB[0]
		USE SIGNAL ;
		DIRECTION OUTPUT ;
		SHAPE ABUTMENT ;
		PORT
			 LAYER M3 ;
			RECT 0.0714 1.029 0.1097 1.1294 ;
		END

		ANTENNADIFFAREA 0.00194719 ;
		ANTENNAPARTIALMETALAREA 0.00195671 ;
	END WENYB[0]

	PIN WENYB[10]
		USE SIGNAL ;
		DIRECTION OUTPUT ;
		SHAPE ABUTMENT ;
		PORT
			 LAYER M3 ;
			RECT 0.0714 16.8408 0.1097 16.9412 ;
		END

		ANTENNADIFFAREA 0.00194719 ;
		ANTENNAPARTIALMETALAREA 0.00195671 ;
	END WENYB[10]

	PIN WENYB[11]
		USE SIGNAL ;
		DIRECTION OUTPUT ;
		SHAPE ABUTMENT ;
		PORT
			 LAYER M3 ;
			RECT 0.0714 18.422 0.1097 18.5224 ;
		END

		ANTENNADIFFAREA 0.00194719 ;
		ANTENNAPARTIALMETALAREA 0.00195671 ;
	END WENYB[11]

	PIN WENYB[12]
		USE SIGNAL ;
		DIRECTION OUTPUT ;
		SHAPE ABUTMENT ;
		PORT
			 LAYER M3 ;
			RECT 0.0714 20.0031 0.1097 20.1035 ;
		END

		ANTENNADIFFAREA 0.00194719 ;
		ANTENNAPARTIALMETALAREA 0.00195671 ;
	END WENYB[12]

	PIN WENYB[13]
		USE SIGNAL ;
		DIRECTION OUTPUT ;
		SHAPE ABUTMENT ;
		PORT
			 LAYER M3 ;
			RECT 0.0714 21.5843 0.1097 21.6847 ;
		END

		ANTENNADIFFAREA 0.00194719 ;
		ANTENNAPARTIALMETALAREA 0.00195671 ;
	END WENYB[13]

	PIN WENYB[14]
		USE SIGNAL ;
		DIRECTION OUTPUT ;
		SHAPE ABUTMENT ;
		PORT
			 LAYER M3 ;
			RECT 0.0714 23.1655 0.1097 23.2659 ;
		END

		ANTENNADIFFAREA 0.00194719 ;
		ANTENNAPARTIALMETALAREA 0.00195671 ;
	END WENYB[14]

	PIN WENYB[15]
		USE SIGNAL ;
		DIRECTION OUTPUT ;
		SHAPE ABUTMENT ;
		PORT
			 LAYER M3 ;
			RECT 0.0714 24.7467 0.1097 24.8471 ;
		END

		ANTENNADIFFAREA 0.00194719 ;
		ANTENNAPARTIALMETALAREA 0.00195671 ;
	END WENYB[15]

	PIN WENYB[16]
		USE SIGNAL ;
		DIRECTION OUTPUT ;
		SHAPE ABUTMENT ;
		PORT
			 LAYER M3 ;
			RECT 0.0714 36.8 0.1097 36.9004 ;
		END

		ANTENNADIFFAREA 0.00194719 ;
		ANTENNAPARTIALMETALAREA 0.00195671 ;
	END WENYB[16]

	PIN WENYB[17]
		USE SIGNAL ;
		DIRECTION OUTPUT ;
		SHAPE ABUTMENT ;
		PORT
			 LAYER M3 ;
			RECT 0.0714 38.3812 0.1097 38.4816 ;
		END

		ANTENNADIFFAREA 0.00194719 ;
		ANTENNAPARTIALMETALAREA 0.00195671 ;
	END WENYB[17]

	PIN WENYB[18]
		USE SIGNAL ;
		DIRECTION OUTPUT ;
		SHAPE ABUTMENT ;
		PORT
			 LAYER M3 ;
			RECT 0.0714 39.9624 0.1097 40.0627 ;
		END

		ANTENNADIFFAREA 0.00194719 ;
		ANTENNAPARTIALMETALAREA 0.00195671 ;
	END WENYB[18]

	PIN WENYB[19]
		USE SIGNAL ;
		DIRECTION OUTPUT ;
		SHAPE ABUTMENT ;
		PORT
			 LAYER M3 ;
			RECT 0.0714 41.5435 0.1097 41.6439 ;
		END

		ANTENNADIFFAREA 0.00194719 ;
		ANTENNAPARTIALMETALAREA 0.00195671 ;
	END WENYB[19]

	PIN WENYB[1]
		USE SIGNAL ;
		DIRECTION OUTPUT ;
		SHAPE ABUTMENT ;
		PORT
			 LAYER M3 ;
			RECT 0.0714 2.6102 0.1097 2.7106 ;
		END

		ANTENNADIFFAREA 0.00194719 ;
		ANTENNAPARTIALMETALAREA 0.00195671 ;
	END WENYB[1]

	PIN WENYB[20]
		USE SIGNAL ;
		DIRECTION OUTPUT ;
		SHAPE ABUTMENT ;
		PORT
			 LAYER M3 ;
			RECT 0.0714 43.1247 0.1097 43.2251 ;
		END

		ANTENNADIFFAREA 0.00194719 ;
		ANTENNAPARTIALMETALAREA 0.00195671 ;
	END WENYB[20]

	PIN WENYB[21]
		USE SIGNAL ;
		DIRECTION OUTPUT ;
		SHAPE ABUTMENT ;
		PORT
			 LAYER M3 ;
			RECT 0.0714 44.7059 0.1097 44.8063 ;
		END

		ANTENNADIFFAREA 0.00194719 ;
		ANTENNAPARTIALMETALAREA 0.00195671 ;
	END WENYB[21]

	PIN WENYB[22]
		USE SIGNAL ;
		DIRECTION OUTPUT ;
		SHAPE ABUTMENT ;
		PORT
			 LAYER M3 ;
			RECT 0.0714 46.2871 0.1097 46.3875 ;
		END

		ANTENNADIFFAREA 0.00194719 ;
		ANTENNAPARTIALMETALAREA 0.00195671 ;
	END WENYB[22]

	PIN WENYB[23]
		USE SIGNAL ;
		DIRECTION OUTPUT ;
		SHAPE ABUTMENT ;
		PORT
			 LAYER M3 ;
			RECT 0.0714 47.8682 0.1097 47.9686 ;
		END

		ANTENNADIFFAREA 0.00194719 ;
		ANTENNAPARTIALMETALAREA 0.00195671 ;
	END WENYB[23]

	PIN WENYB[24]
		USE SIGNAL ;
		DIRECTION OUTPUT ;
		SHAPE ABUTMENT ;
		PORT
			 LAYER M3 ;
			RECT 0.0714 49.4494 0.1097 49.5498 ;
		END

		ANTENNADIFFAREA 0.00194719 ;
		ANTENNAPARTIALMETALAREA 0.00195671 ;
	END WENYB[24]

	PIN WENYB[25]
		USE SIGNAL ;
		DIRECTION OUTPUT ;
		SHAPE ABUTMENT ;
		PORT
			 LAYER M3 ;
			RECT 0.0714 51.0306 0.1097 51.131 ;
		END

		ANTENNADIFFAREA 0.00194719 ;
		ANTENNAPARTIALMETALAREA 0.00195671 ;
	END WENYB[25]

	PIN WENYB[26]
		USE SIGNAL ;
		DIRECTION OUTPUT ;
		SHAPE ABUTMENT ;
		PORT
			 LAYER M3 ;
			RECT 0.0714 52.6118 0.1097 52.7122 ;
		END

		ANTENNADIFFAREA 0.00194719 ;
		ANTENNAPARTIALMETALAREA 0.00195671 ;
	END WENYB[26]

	PIN WENYB[27]
		USE SIGNAL ;
		DIRECTION OUTPUT ;
		SHAPE ABUTMENT ;
		PORT
			 LAYER M3 ;
			RECT 0.0714 54.1929 0.1097 54.2933 ;
		END

		ANTENNADIFFAREA 0.00194719 ;
		ANTENNAPARTIALMETALAREA 0.00195671 ;
	END WENYB[27]

	PIN WENYB[28]
		USE SIGNAL ;
		DIRECTION OUTPUT ;
		SHAPE ABUTMENT ;
		PORT
			 LAYER M3 ;
			RECT 0.0714 55.7741 0.1097 55.8745 ;
		END

		ANTENNADIFFAREA 0.00194719 ;
		ANTENNAPARTIALMETALAREA 0.00195671 ;
	END WENYB[28]

	PIN WENYB[29]
		USE SIGNAL ;
		DIRECTION OUTPUT ;
		SHAPE ABUTMENT ;
		PORT
			 LAYER M3 ;
			RECT 0.0714 57.3553 0.1097 57.4557 ;
		END

		ANTENNADIFFAREA 0.00194719 ;
		ANTENNAPARTIALMETALAREA 0.00195671 ;
	END WENYB[29]

	PIN WENYB[2]
		USE SIGNAL ;
		DIRECTION OUTPUT ;
		SHAPE ABUTMENT ;
		PORT
			 LAYER M3 ;
			RECT 0.0714 4.1914 0.1097 4.2918 ;
		END

		ANTENNADIFFAREA 0.00194719 ;
		ANTENNAPARTIALMETALAREA 0.00195671 ;
	END WENYB[2]

	PIN WENYB[30]
		USE SIGNAL ;
		DIRECTION OUTPUT ;
		SHAPE ABUTMENT ;
		PORT
			 LAYER M3 ;
			RECT 0.0714 58.9365 0.1097 59.0369 ;
		END

		ANTENNADIFFAREA 0.00194719 ;
		ANTENNAPARTIALMETALAREA 0.00195671 ;
	END WENYB[30]

	PIN WENYB[31]
		USE SIGNAL ;
		DIRECTION OUTPUT ;
		SHAPE ABUTMENT ;
		PORT
			 LAYER M3 ;
			RECT 0.0714 60.5176 0.1097 60.618 ;
		END

		ANTENNADIFFAREA 0.00194719 ;
		ANTENNAPARTIALMETALAREA 0.00195671 ;
	END WENYB[31]

	PIN WENYB[32]
		USE SIGNAL ;
		DIRECTION OUTPUT ;
		SHAPE ABUTMENT ;
		PORT
			 LAYER M3 ;
			RECT 0.0714 62.0988 0.1097 62.1992 ;
		END

		ANTENNADIFFAREA 0.00194719 ;
		ANTENNAPARTIALMETALAREA 0.00195671 ;
	END WENYB[32]

	PIN WENYB[3]
		USE SIGNAL ;
		DIRECTION OUTPUT ;
		SHAPE ABUTMENT ;
		PORT
			 LAYER M3 ;
			RECT 0.0714 5.7725 0.1097 5.8729 ;
		END

		ANTENNADIFFAREA 0.00194719 ;
		ANTENNAPARTIALMETALAREA 0.00195671 ;
	END WENYB[3]

	PIN WENYB[4]
		USE SIGNAL ;
		DIRECTION OUTPUT ;
		SHAPE ABUTMENT ;
		PORT
			 LAYER M3 ;
			RECT 0.0714 7.3537 0.1097 7.4541 ;
		END

		ANTENNADIFFAREA 0.00194719 ;
		ANTENNAPARTIALMETALAREA 0.00195671 ;
	END WENYB[4]

	PIN WENYB[5]
		USE SIGNAL ;
		DIRECTION OUTPUT ;
		SHAPE ABUTMENT ;
		PORT
			 LAYER M3 ;
			RECT 0.0714 8.9349 0.1097 9.0353 ;
		END

		ANTENNADIFFAREA 0.00194719 ;
		ANTENNAPARTIALMETALAREA 0.00195671 ;
	END WENYB[5]

	PIN WENYB[6]
		USE SIGNAL ;
		DIRECTION OUTPUT ;
		SHAPE ABUTMENT ;
		PORT
			 LAYER M3 ;
			RECT 0.0714 10.5161 0.1097 10.6165 ;
		END

		ANTENNADIFFAREA 0.00194719 ;
		ANTENNAPARTIALMETALAREA 0.00195671 ;
	END WENYB[6]

	PIN WENYB[7]
		USE SIGNAL ;
		DIRECTION OUTPUT ;
		SHAPE ABUTMENT ;
		PORT
			 LAYER M3 ;
			RECT 0.0714 12.0973 0.1097 12.1976 ;
		END

		ANTENNADIFFAREA 0.00194719 ;
		ANTENNAPARTIALMETALAREA 0.00195671 ;
	END WENYB[7]

	PIN WENYB[8]
		USE SIGNAL ;
		DIRECTION OUTPUT ;
		SHAPE ABUTMENT ;
		PORT
			 LAYER M3 ;
			RECT 0.0714 13.6784 0.1097 13.7788 ;
		END

		ANTENNADIFFAREA 0.00194719 ;
		ANTENNAPARTIALMETALAREA 0.00195671 ;
	END WENYB[8]

	PIN WENYB[9]
		USE SIGNAL ;
		DIRECTION OUTPUT ;
		SHAPE ABUTMENT ;
		PORT
			 LAYER M3 ;
			RECT 0.0714 15.2596 0.1097 15.36 ;
		END

		ANTENNADIFFAREA 0.00194719 ;
		ANTENNAPARTIALMETALAREA 0.00195671 ;
	END WENYB[9]

	OBS
		 LAYER M1 SPACING 0.012 ;
		RECT 0 0 12.705 63.2282 ;
		 LAYER M2 SPACING 0.012 ;
		RECT 0.133 0 12.705 63.2282 ;
		RECT 0 0 0.133 0.069 ;
		RECT 0 0.2071 0.133 1.0102 ;
		RECT 0 1.1482 0.133 1.1608 ;
		RECT 0 1.2988 0.133 1.3114 ;
		RECT 0 1.4494 0.133 1.462 ;
		RECT 0 1.6 0.133 1.6125 ;
		RECT 0 1.7506 0.133 2.5914 ;
		RECT 0 2.7294 0.133 2.742 ;
		RECT 0 2.88 0.133 2.8925 ;
		RECT 0 3.0306 0.133 3.0431 ;
		RECT 0 3.1812 0.133 3.1937 ;
		RECT 0 3.3318 0.133 4.1725 ;
		RECT 0 4.3106 0.133 4.3231 ;
		RECT 0 4.4612 0.133 4.4737 ;
		RECT 0 4.6118 0.133 4.6243 ;
		RECT 0 4.7624 0.133 4.7749 ;
		RECT 0 4.9129 0.133 5.7537 ;
		RECT 0 5.8918 0.133 5.9043 ;
		RECT 0 6.0424 0.133 6.0549 ;
		RECT 0 6.1929 0.133 6.2055 ;
		RECT 0 6.3435 0.133 6.3561 ;
		RECT 0 6.4941 0.133 7.3349 ;
		RECT 0 7.4729 0.133 7.4855 ;
		RECT 0 7.6235 0.133 7.6361 ;
		RECT 0 7.7741 0.133 7.7867 ;
		RECT 0 7.9247 0.133 7.9373 ;
		RECT 0 8.0753 0.133 8.9161 ;
		RECT 0 9.0541 0.133 9.0667 ;
		RECT 0 9.2047 0.133 9.2173 ;
		RECT 0 9.3553 0.133 9.3678 ;
		RECT 0 9.5059 0.133 9.5184 ;
		RECT 0 9.6565 0.133 10.4973 ;
		RECT 0 10.6353 0.133 10.6478 ;
		RECT 0 10.7859 0.133 10.7984 ;
		RECT 0 10.9365 0.133 10.949 ;
		RECT 0 11.0871 0.133 11.0996 ;
		RECT 0 11.2376 0.133 12.0784 ;
		RECT 0 12.2165 0.133 12.229 ;
		RECT 0 12.3671 0.133 12.3796 ;
		RECT 0 12.5176 0.133 12.5302 ;
		RECT 0 12.6682 0.133 12.6808 ;
		RECT 0 12.8188 0.133 13.6596 ;
		RECT 0 13.7976 0.133 13.8102 ;
		RECT 0 13.9482 0.133 13.9608 ;
		RECT 0 14.0988 0.133 14.1114 ;
		RECT 0 14.2494 0.133 14.262 ;
		RECT 0 14.4 0.133 15.2408 ;
		RECT 0 15.3788 0.133 15.3914 ;
		RECT 0 15.5294 0.133 15.542 ;
		RECT 0 15.68 0.133 15.6925 ;
		RECT 0 15.8306 0.133 15.8431 ;
		RECT 0 15.9812 0.133 16.822 ;
		RECT 0 16.96 0.133 16.9725 ;
		RECT 0 17.1106 0.133 17.1231 ;
		RECT 0 17.2612 0.133 17.2737 ;
		RECT 0 17.4118 0.133 17.4243 ;
		RECT 0 17.5624 0.133 18.4031 ;
		RECT 0 18.5412 0.133 18.5537 ;
		RECT 0 18.6918 0.133 18.7043 ;
		RECT 0 18.8424 0.133 18.8549 ;
		RECT 0 18.9929 0.133 19.0055 ;
		RECT 0 19.1435 0.133 19.9843 ;
		RECT 0 20.1224 0.133 20.1349 ;
		RECT 0 20.2729 0.133 20.2855 ;
		RECT 0 20.4235 0.133 20.4361 ;
		RECT 0 20.5741 0.133 20.5867 ;
		RECT 0 20.7247 0.133 21.5655 ;
		RECT 0 21.7035 0.133 21.7161 ;
		RECT 0 21.8541 0.133 21.8667 ;
		RECT 0 22.0047 0.133 22.0173 ;
		RECT 0 22.1553 0.133 22.1678 ;
		RECT 0 22.3059 0.133 23.1467 ;
		RECT 0 23.2847 0.133 23.2973 ;
		RECT 0 23.4353 0.133 23.4478 ;
		RECT 0 23.5859 0.133 23.5984 ;
		RECT 0 23.7365 0.133 23.749 ;
		RECT 0 23.8871 0.133 24.7278 ;
		RECT 0 24.8659 0.133 24.8784 ;
		RECT 0 25.0165 0.133 25.029 ;
		RECT 0 25.1671 0.133 25.1796 ;
		RECT 0 25.3176 0.133 25.3302 ;
		RECT 0 25.4682 0.133 27.1498 ;
		RECT 0 27.2878 0.133 27.3004 ;
		RECT 0.0714 27.3004 0.133 27.6016 ;
		RECT 0 27.4384 0.133 27.6016 ;
		RECT 0 27.7396 0.133 28.0533 ;
		RECT 0 28.1914 0.133 28.2039 ;
		RECT 0 28.342 0.133 28.3545 ;
		RECT 0 28.869 0.133 29.0573 ;
		RECT 0 29.1953 0.133 29.2078 ;
		RECT 0 29.3459 0.133 29.3584 ;
		RECT 0 29.622 0.133 29.6345 ;
		RECT 0 29.7725 0.133 30.0863 ;
		RECT 0 30.2243 0.133 30.2369 ;
		RECT 0 30.6259 0.133 30.6384 ;
		RECT 0 30.902 0.133 31.1655 ;
		RECT 0 31.3035 0.133 31.4165 ;
		RECT 0 31.68 0.133 31.6925 ;
		RECT 0 32.2071 0.133 32.2196 ;
		RECT 0 32.7341 0.133 33.5247 ;
		RECT 0 33.7882 0.133 34.0518 ;
		RECT 0 34.1898 0.133 34.2024 ;
		RECT 0 34.3404 0.133 34.3529 ;
		RECT 0 34.491 0.133 36.1788 ;
		RECT 0 36.3169 0.133 36.3294 ;
		RECT 0 36.4675 0.133 36.48 ;
		RECT 0 36.618 0.133 36.6306 ;
		RECT 0 36.7686 0.133 36.7812 ;
		RECT 0 36.9192 0.133 37.76 ;
		RECT 0 37.898 0.133 37.9106 ;
		RECT 0 38.0486 0.133 38.0612 ;
		RECT 0 38.1992 0.133 38.2118 ;
		RECT 0 38.3498 0.133 38.3624 ;
		RECT 0 38.5004 0.133 39.3412 ;
		RECT 0 39.4792 0.133 39.4918 ;
		RECT 0 39.6298 0.133 39.6424 ;
		RECT 0 39.7804 0.133 39.7929 ;
		RECT 0 39.931 0.133 39.9435 ;
		RECT 0 40.0816 0.133 40.9224 ;
		RECT 0 41.0604 0.133 41.0729 ;
		RECT 0 41.211 0.133 41.2235 ;
		RECT 0 41.3616 0.133 41.3741 ;
		RECT 0 41.5122 0.133 41.5247 ;
		RECT 0 41.6627 0.133 42.5035 ;
		RECT 0 42.6416 0.133 42.6541 ;
		RECT 0 42.7922 0.133 42.8047 ;
		RECT 0 42.9427 0.133 42.9553 ;
		RECT 0 43.0933 0.133 43.1059 ;
		RECT 0 43.2439 0.133 44.0847 ;
		RECT 0 44.2227 0.133 44.2353 ;
		RECT 0 44.3733 0.133 44.3859 ;
		RECT 0 44.5239 0.133 44.5365 ;
		RECT 0 44.6745 0.133 44.6871 ;
		RECT 0 44.8251 0.133 45.6659 ;
		RECT 0 45.8039 0.133 45.8165 ;
		RECT 0 45.9545 0.133 45.9671 ;
		RECT 0 46.1051 0.133 46.1176 ;
		RECT 0 46.2557 0.133 46.2682 ;
		RECT 0 46.4063 0.133 47.2471 ;
		RECT 0 47.3851 0.133 47.3976 ;
		RECT 0 47.5357 0.133 47.5482 ;
		RECT 0 47.6863 0.133 47.6988 ;
		RECT 0 47.8369 0.133 47.8494 ;
		RECT 0 47.9875 0.133 48.8282 ;
		RECT 0 48.9663 0.133 48.9788 ;
		RECT 0 49.1169 0.133 49.1294 ;
		RECT 0 49.2675 0.133 49.28 ;
		RECT 0 49.418 0.133 49.4306 ;
		RECT 0 49.5686 0.133 50.4094 ;
		RECT 0 50.5475 0.133 50.56 ;
		RECT 0 50.698 0.133 50.7106 ;
		RECT 0 50.8486 0.133 50.8612 ;
		RECT 0 50.9992 0.133 51.0118 ;
		RECT 0 51.1498 0.133 51.9906 ;
		RECT 0 52.1286 0.133 52.1412 ;
		RECT 0 52.2792 0.133 52.2918 ;
		RECT 0 52.4298 0.133 52.4424 ;
		RECT 0 52.5804 0.133 52.5929 ;
		RECT 0 52.731 0.133 53.5718 ;
		RECT 0 53.7098 0.133 53.7224 ;
		RECT 0 53.8604 0.133 53.8729 ;
		RECT 0 54.011 0.133 54.0235 ;
		RECT 0 54.1616 0.133 54.1741 ;
		RECT 0 54.3122 0.133 55.1529 ;
		RECT 0 55.291 0.133 55.3035 ;
		RECT 0 55.4416 0.133 55.4541 ;
		RECT 0 55.5922 0.133 55.6047 ;
		RECT 0 55.7427 0.133 55.7553 ;
		RECT 0 55.8933 0.133 56.7341 ;
		RECT 0 56.8722 0.133 56.8847 ;
		RECT 0 57.0227 0.133 57.0353 ;
		RECT 0 57.1733 0.133 57.1859 ;
		RECT 0 57.3239 0.133 57.3365 ;
		RECT 0 57.4745 0.133 58.3153 ;
		RECT 0 58.4533 0.133 58.4659 ;
		RECT 0 58.6039 0.133 58.6165 ;
		RECT 0 58.7545 0.133 58.7671 ;
		RECT 0 58.9051 0.133 58.9176 ;
		RECT 0 59.0557 0.133 59.8965 ;
		RECT 0 60.0345 0.133 60.0471 ;
		RECT 0 60.1851 0.133 60.1976 ;
		RECT 0 60.3357 0.133 60.3482 ;
		RECT 0 60.4863 0.133 60.4988 ;
		RECT 0 60.6369 0.133 61.4776 ;
		RECT 0 61.6157 0.133 61.6282 ;
		RECT 0 61.7663 0.133 61.7788 ;
		RECT 0 61.9169 0.133 61.9294 ;
		RECT 0 62.0675 0.133 62.08 ;
		RECT 0 62.218 0.133 63.0212 ;
		RECT 0 63.1592 0.133 63.2282 ;
		 LAYER M2 ;
		RECT 0.0714 1.029 0.1097 1.1294 ;
		RECT 0.0714 1.6314 0.1097 1.7318 ;
		RECT 0.0714 2.6102 0.1097 2.7106 ;
		RECT 0.0714 3.2125 0.1097 3.3129 ;
		RECT 0.0714 4.1914 0.1097 4.2918 ;
		RECT 0.0714 4.7937 0.1097 4.8941 ;
		RECT 0.0714 5.7725 0.1097 5.8729 ;
		RECT 0.0714 6.3749 0.1097 6.4753 ;
		RECT 0.0714 7.3537 0.1097 7.4541 ;
		RECT 0.0714 7.9561 0.1097 8.0565 ;
		RECT 0.0714 8.9349 0.1097 9.0353 ;
		RECT 0.0714 9.5373 0.1097 9.6376 ;
		RECT 0.0714 10.5161 0.1097 10.6165 ;
		RECT 0.0714 11.1184 0.1097 11.2188 ;
		RECT 0.0714 12.0973 0.1097 12.1976 ;
		RECT 0.0714 12.6996 0.1097 12.8 ;
		RECT 0.0714 13.6784 0.1097 13.7788 ;
		RECT 0.0714 14.2808 0.1097 14.3812 ;
		RECT 0.0714 15.2596 0.1097 15.36 ;
		RECT 0.0714 15.862 0.1097 15.9624 ;
		RECT 0.0714 16.8408 0.1097 16.9412 ;
		RECT 0.0714 17.4431 0.1097 17.5435 ;
		RECT 0.0714 18.422 0.1097 18.5224 ;
		RECT 0.0714 19.0243 0.1097 19.1247 ;
		RECT 0.0714 20.0031 0.1097 20.1035 ;
		RECT 0.0714 20.6055 0.1097 20.7059 ;
		RECT 0.0714 21.5843 0.1097 21.6847 ;
		RECT 0.0714 22.1867 0.1097 22.2871 ;
		RECT 0.0714 23.1655 0.1097 23.2659 ;
		RECT 0.0714 23.7678 0.1097 23.8682 ;
		RECT 0.0714 24.7467 0.1097 24.8471 ;
		RECT 0.0714 25.349 0.1097 25.4494 ;
		RECT 0.0714 27.6204 0.1097 27.7208 ;
		RECT 0.0714 28.0722 0.1097 28.1725 ;
		RECT 0.0714 28.2227 0.1097 28.3231 ;
		RECT 0.0714 28.6243 0.1097 28.7247 ;
		RECT 0.0714 29.0761 0.1097 29.1765 ;
		RECT 0.0714 29.2267 0.1097 29.3271 ;
		RECT 0.0714 29.5027 0.1097 29.6031 ;
		RECT 0.0714 29.6533 0.1097 29.7537 ;
		RECT 0.0714 30.1051 0.1097 30.2055 ;
		RECT 0.0714 30.2557 0.1097 30.3561 ;
		RECT 0.0714 30.3812 0.1097 30.4816 ;
		RECT 0.0714 30.5067 0.1097 30.6071 ;
		RECT 0.0714 30.6573 0.1097 30.7576 ;
		RECT 0.0714 30.7827 0.1097 30.8831 ;
		RECT 0.0714 31.1843 0.1097 31.2847 ;
		RECT 0.0714 31.4353 0.1097 31.5357 ;
		RECT 0.0714 31.5608 0.1097 31.6612 ;
		RECT 0.0714 31.7114 0.1097 31.8118 ;
		RECT 0.0714 31.8369 0.1097 31.9373 ;
		RECT 0.0714 31.9624 0.1097 32.0627 ;
		RECT 0.0714 32.0878 0.1097 32.1882 ;
		RECT 0.0714 32.2384 0.1097 32.3388 ;
		RECT 0.0714 32.3639 0.1097 32.4643 ;
		RECT 0.0714 32.4894 0.1097 32.5898 ;
		RECT 0.0714 32.6149 0.1097 32.7153 ;
		RECT 0.0714 33.5435 0.1097 33.6439 ;
		RECT 0.0714 33.669 0.1097 33.7694 ;
		RECT 0.0714 34.0706 0.1097 34.171 ;
		RECT 0.0714 34.2212 0.1097 34.3216 ;
		RECT 0.0714 34.3718 0.1097 34.4722 ;
		RECT 0.0714 36.1976 0.1097 36.298 ;
		RECT 0.0714 36.8 0.1097 36.9004 ;
		RECT 0.0714 37.7788 0.1097 37.8792 ;
		RECT 0.0714 38.3812 0.1097 38.4816 ;
		RECT 0.0714 39.36 0.1097 39.4604 ;
		RECT 0.0714 39.9624 0.1097 40.0627 ;
		RECT 0.0714 40.9412 0.1097 41.0416 ;
		RECT 0.0714 41.5435 0.1097 41.6439 ;
		RECT 0.0714 42.5224 0.1097 42.6227 ;
		RECT 0.0714 43.1247 0.1097 43.2251 ;
		RECT 0.0714 44.1035 0.1097 44.2039 ;
		RECT 0.0714 44.7059 0.1097 44.8063 ;
		RECT 0.0714 45.6847 0.1097 45.7851 ;
		RECT 0.0714 46.2871 0.1097 46.3875 ;
		RECT 0.0714 47.2659 0.1097 47.3663 ;
		RECT 0.0714 47.8682 0.1097 47.9686 ;
		RECT 0.0714 48.8471 0.1097 48.9475 ;
		RECT 0.0714 49.4494 0.1097 49.5498 ;
		RECT 0.0714 50.4282 0.1097 50.5286 ;
		RECT 0.0714 51.0306 0.1097 51.131 ;
		RECT 0.0714 52.0094 0.1097 52.1098 ;
		RECT 0.0714 52.6118 0.1097 52.7122 ;
		RECT 0.0714 53.5906 0.1097 53.691 ;
		RECT 0.0714 54.1929 0.1097 54.2933 ;
		RECT 0.0714 55.1718 0.1097 55.2722 ;
		RECT 0.0714 55.7741 0.1097 55.8745 ;
		RECT 0.0714 56.7529 0.1097 56.8533 ;
		RECT 0.0714 57.3553 0.1097 57.4557 ;
		RECT 0.0714 58.3341 0.1097 58.4345 ;
		RECT 0.0714 58.9365 0.1097 59.0369 ;
		RECT 0.0714 59.9153 0.1097 60.0157 ;
		RECT 0.0714 60.5176 0.1097 60.618 ;
		RECT 0.0714 61.4965 0.1097 61.5969 ;
		RECT 0.0714 62.0988 0.1097 62.1992 ;
		RECT 0.0098 27.2314 0.0481 27.269 ;
		RECT 0.0098 27.4698 0.0481 27.5702 ;
		RECT 0.0098 29.3773 0.0481 29.4149 ;
		RECT 0.0098 29.5655 0.0481 29.6031 ;
		RECT 0.0098 29.6533 0.0481 29.691 ;
		RECT 0.0098 29.8039 0.0481 29.8416 ;
		RECT 0.0098 29.8667 0.0481 29.9043 ;
		RECT 0.0098 29.9545 0.0481 29.9922 ;
		RECT 0.0098 30.0173 0.0481 30.0549 ;
		RECT 0.0098 30.9082 0.0481 30.9459 ;
		RECT 0.0098 30.971 0.0481 31.0086 ;
		RECT 0.0098 31.0337 0.0481 31.0714 ;
		RECT 0.0098 27.771 0.0481 27.8086 ;
		RECT 0.0098 31.0965 0.0481 31.1341 ;
		RECT 0.0098 31.1843 0.0481 31.222 ;
		RECT 0.0098 31.2471 0.0481 31.2847 ;
		RECT 0.0098 31.3098 0.0481 31.3475 ;
		RECT 0.0098 31.3725 0.0481 31.4102 ;
		RECT 0.0098 31.5608 0.0481 31.5984 ;
		RECT 0.0098 32.7655 0.0481 32.8031 ;
		RECT 0.0098 32.8282 0.0481 32.8659 ;
		RECT 0.0098 32.891 0.0481 32.9286 ;
		RECT 0.0098 32.9537 0.0481 32.9914 ;
		RECT 0.0098 27.8337 0.0481 27.8714 ;
		RECT 0.0098 33.0165 0.0481 33.0541 ;
		RECT 0.0098 33.0792 0.0481 33.1169 ;
		RECT 0.0098 33.142 0.0481 33.1796 ;
		RECT 0.0098 33.2047 0.0481 33.2424 ;
		RECT 0.0098 33.2925 0.0481 33.3302 ;
		RECT 0.0098 33.3553 0.0481 33.3929 ;
		RECT 0.0098 33.418 0.0481 33.4557 ;
		RECT 0.0098 33.4808 0.0481 33.5184 ;
		RECT 0.0098 33.8196 0.0481 33.8573 ;
		RECT 0.0098 33.8824 0.0481 33.92 ;
		RECT 0.0098 27.9216 0.0481 27.9592 ;
		RECT 0.0098 33.9451 0.0481 33.9827 ;
		RECT 0.0098 34.0078 0.0481 34.0455 ;
		RECT 0.0098 34.2212 0.0481 34.2588 ;
		RECT 0.0098 34.2839 0.0481 34.3216 ;
		RECT 0.0098 27.9843 0.0481 28.022 ;
		RECT 0.0714 28.9255 0.1097 28.9631 ;
		RECT 0.0098 28.9882 0.0481 29.0259 ;
		RECT 0.0098 29.2267 0.0481 29.2643 ;
		RECT 0.0098 29.2894 0.0481 29.3271 ;
		 LAYER M2 SPACING 0.012 ;
		RECT 0.0714 1.029 0.1097 1.1294 ;
		RECT 0.0714 1.6314 0.1097 1.7318 ;
		RECT 0.0714 2.6102 0.1097 2.7106 ;
		RECT 0.0714 3.2125 0.1097 3.3129 ;
		RECT 0.0714 4.1914 0.1097 4.2918 ;
		RECT 0.0714 4.7937 0.1097 4.8941 ;
		RECT 0.0714 5.7725 0.1097 5.8729 ;
		RECT 0.0714 6.3749 0.1097 6.4753 ;
		RECT 0.0714 7.3537 0.1097 7.4541 ;
		RECT 0.0714 7.9561 0.1097 8.0565 ;
		RECT 0.0714 8.9349 0.1097 9.0353 ;
		RECT 0.0714 9.5373 0.1097 9.6376 ;
		RECT 0.0714 10.5161 0.1097 10.6165 ;
		RECT 0.0714 11.1184 0.1097 11.2188 ;
		RECT 0.0714 12.0973 0.1097 12.1976 ;
		RECT 0.0714 12.6996 0.1097 12.8 ;
		RECT 0.0714 13.6784 0.1097 13.7788 ;
		RECT 0.0714 14.2808 0.1097 14.3812 ;
		RECT 0.0714 15.2596 0.1097 15.36 ;
		RECT 0.0714 15.862 0.1097 15.9624 ;
		RECT 0.0714 16.8408 0.1097 16.9412 ;
		RECT 0.0714 17.4431 0.1097 17.5435 ;
		RECT 0.0714 18.422 0.1097 18.5224 ;
		RECT 0.0714 19.0243 0.1097 19.1247 ;
		RECT 0.0714 20.0031 0.1097 20.1035 ;
		RECT 0.0714 20.6055 0.1097 20.7059 ;
		RECT 0.0714 21.5843 0.1097 21.6847 ;
		RECT 0.0714 22.1867 0.1097 22.2871 ;
		RECT 0.0714 23.1655 0.1097 23.2659 ;
		RECT 0.0714 23.7678 0.1097 23.8682 ;
		RECT 0.0714 24.7467 0.1097 24.8471 ;
		RECT 0.0714 25.349 0.1097 25.4494 ;
		RECT 0.0714 27.6204 0.1097 27.7208 ;
		RECT 0.0714 28.0722 0.1097 28.1725 ;
		RECT 0.0714 28.2227 0.1097 28.3231 ;
		RECT 0.0714 28.6243 0.1097 28.7247 ;
		RECT 0.0714 29.0761 0.1097 29.1765 ;
		RECT 0.0714 29.2267 0.1097 29.3271 ;
		RECT 0.0714 29.5027 0.1097 29.6031 ;
		RECT 0.0714 29.6533 0.1097 29.7537 ;
		RECT 0.0714 30.1051 0.1097 30.2055 ;
		RECT 0.0714 30.2557 0.1097 30.3561 ;
		RECT 0.0714 30.3812 0.1097 30.4816 ;
		RECT 0.0714 30.5067 0.1097 30.6071 ;
		RECT 0.0714 30.6573 0.1097 30.7576 ;
		RECT 0.0714 30.7827 0.1097 30.8831 ;
		RECT 0.0714 31.1843 0.1097 31.2847 ;
		RECT 0.0714 31.4353 0.1097 31.5357 ;
		RECT 0.0714 31.5608 0.1097 31.6612 ;
		RECT 0.0714 31.7114 0.1097 31.8118 ;
		RECT 0.0714 31.8369 0.1097 31.9373 ;
		RECT 0.0714 31.9624 0.1097 32.0627 ;
		RECT 0.0714 32.0878 0.1097 32.1882 ;
		RECT 0.0714 32.2384 0.1097 32.3388 ;
		RECT 0.0714 32.3639 0.1097 32.4643 ;
		RECT 0.0714 32.4894 0.1097 32.5898 ;
		RECT 0.0714 32.6149 0.1097 32.7153 ;
		RECT 0.0714 33.5435 0.1097 33.6439 ;
		RECT 0.0714 33.669 0.1097 33.7694 ;
		RECT 0.0714 34.0706 0.1097 34.171 ;
		RECT 0.0714 34.2212 0.1097 34.3216 ;
		RECT 0.0714 34.3718 0.1097 34.4722 ;
		RECT 0.0714 36.1976 0.1097 36.298 ;
		RECT 0.0714 36.8 0.1097 36.9004 ;
		RECT 0.0714 37.7788 0.1097 37.8792 ;
		RECT 0.0714 38.3812 0.1097 38.4816 ;
		RECT 0.0714 39.36 0.1097 39.4604 ;
		RECT 0.0714 39.9624 0.1097 40.0627 ;
		RECT 0.0714 40.9412 0.1097 41.0416 ;
		RECT 0.0714 41.5435 0.1097 41.6439 ;
		RECT 0.0714 42.5224 0.1097 42.6227 ;
		RECT 0.0714 43.1247 0.1097 43.2251 ;
		RECT 0.0714 44.1035 0.1097 44.2039 ;
		RECT 0.0714 44.7059 0.1097 44.8063 ;
		RECT 0.0714 45.6847 0.1097 45.7851 ;
		RECT 0.0714 46.2871 0.1097 46.3875 ;
		RECT 0.0714 47.2659 0.1097 47.3663 ;
		RECT 0.0714 47.8682 0.1097 47.9686 ;
		RECT 0.0714 48.8471 0.1097 48.9475 ;
		RECT 0.0714 49.4494 0.1097 49.5498 ;
		RECT 0.0714 50.4282 0.1097 50.5286 ;
		RECT 0.0714 51.0306 0.1097 51.131 ;
		RECT 0.0714 52.0094 0.1097 52.1098 ;
		RECT 0.0714 52.6118 0.1097 52.7122 ;
		RECT 0.0714 53.5906 0.1097 53.691 ;
		RECT 0.0714 54.1929 0.1097 54.2933 ;
		RECT 0.0714 55.1718 0.1097 55.2722 ;
		RECT 0.0714 55.7741 0.1097 55.8745 ;
		RECT 0.0714 56.7529 0.1097 56.8533 ;
		RECT 0.0714 57.3553 0.1097 57.4557 ;
		RECT 0.0714 58.3341 0.1097 58.4345 ;
		RECT 0.0714 58.9365 0.1097 59.0369 ;
		RECT 0.0714 59.9153 0.1097 60.0157 ;
		RECT 0.0714 60.5176 0.1097 60.618 ;
		RECT 0.0714 61.4965 0.1097 61.5969 ;
		RECT 0.0714 62.0988 0.1097 62.1992 ;
		RECT 0.0098 27.2314 0.0481 27.269 ;
		RECT 0.0098 27.4698 0.0481 27.5702 ;
		RECT 0.0098 29.3773 0.0481 29.4149 ;
		RECT 0.0098 29.5655 0.0481 29.6031 ;
		RECT 0.0098 29.6533 0.0481 29.691 ;
		RECT 0.0098 29.8039 0.0481 29.8416 ;
		RECT 0.0098 29.8667 0.0481 29.9043 ;
		RECT 0.0098 29.9545 0.0481 29.9922 ;
		RECT 0.0098 30.0173 0.0481 30.0549 ;
		RECT 0.0098 30.9082 0.0481 30.9459 ;
		RECT 0.0098 30.971 0.0481 31.0086 ;
		RECT 0.0098 31.0337 0.0481 31.0714 ;
		RECT 0.0098 27.771 0.0481 27.8086 ;
		RECT 0.0098 31.0965 0.0481 31.1341 ;
		RECT 0.0098 31.1843 0.0481 31.222 ;
		RECT 0.0098 31.2471 0.0481 31.2847 ;
		RECT 0.0098 31.3098 0.0481 31.3475 ;
		RECT 0.0098 31.3725 0.0481 31.4102 ;
		RECT 0.0098 31.5608 0.0481 31.5984 ;
		RECT 0.0098 32.7655 0.0481 32.8031 ;
		RECT 0.0098 32.8282 0.0481 32.8659 ;
		RECT 0.0098 32.891 0.0481 32.9286 ;
		RECT 0.0098 32.9537 0.0481 32.9914 ;
		RECT 0.0098 27.8337 0.0481 27.8714 ;
		RECT 0.0098 33.0165 0.0481 33.0541 ;
		RECT 0.0098 33.0792 0.0481 33.1169 ;
		RECT 0.0098 33.142 0.0481 33.1796 ;
		RECT 0.0098 33.2047 0.0481 33.2424 ;
		RECT 0.0098 33.2925 0.0481 33.3302 ;
		RECT 0.0098 33.3553 0.0481 33.3929 ;
		RECT 0.0098 33.418 0.0481 33.4557 ;
		RECT 0.0098 33.4808 0.0481 33.5184 ;
		RECT 0.0098 33.8196 0.0481 33.8573 ;
		RECT 0.0098 33.8824 0.0481 33.92 ;
		RECT 0.0098 27.9216 0.0481 27.9592 ;
		RECT 0.0098 33.9451 0.0481 33.9827 ;
		RECT 0.0098 34.0078 0.0481 34.0455 ;
		RECT 0.0098 34.2212 0.0481 34.2588 ;
		RECT 0.0098 34.2839 0.0481 34.3216 ;
		RECT 0.0098 27.9843 0.0481 28.022 ;
		RECT 0.0714 28.9255 0.1097 28.9631 ;
		RECT 0.0098 28.9882 0.0481 29.0259 ;
		RECT 0.0098 29.2267 0.0481 29.2643 ;
		RECT 0.0098 29.2894 0.0481 29.3271 ;
		 LAYER M3 SPACING 0.012 ;
		RECT 0.133 0 12.705 63.2282 ;
		RECT 0 0 0.133 0.069 ;
		RECT 0 0.2071 0.133 1.0102 ;
		RECT 0 1.1482 0.133 1.1608 ;
		RECT 0 1.2988 0.133 1.3114 ;
		RECT 0 1.4494 0.133 1.462 ;
		RECT 0 1.6 0.133 1.6125 ;
		RECT 0 1.7506 0.133 2.5914 ;
		RECT 0 2.7294 0.133 2.742 ;
		RECT 0 2.88 0.133 2.8925 ;
		RECT 0 3.0306 0.133 3.0431 ;
		RECT 0 3.1812 0.133 3.1937 ;
		RECT 0 3.3318 0.133 4.1725 ;
		RECT 0 4.3106 0.133 4.3231 ;
		RECT 0 4.4612 0.133 4.4737 ;
		RECT 0 4.6118 0.133 4.6243 ;
		RECT 0 4.7624 0.133 4.7749 ;
		RECT 0 4.9129 0.133 5.7537 ;
		RECT 0 5.8918 0.133 5.9043 ;
		RECT 0 6.0424 0.133 6.0549 ;
		RECT 0 6.1929 0.133 6.2055 ;
		RECT 0 6.3435 0.133 6.3561 ;
		RECT 0 6.4941 0.133 7.3349 ;
		RECT 0 7.4729 0.133 7.4855 ;
		RECT 0 7.6235 0.133 7.6361 ;
		RECT 0 7.7741 0.133 7.7867 ;
		RECT 0 7.9247 0.133 7.9373 ;
		RECT 0 8.0753 0.133 8.9161 ;
		RECT 0 9.0541 0.133 9.0667 ;
		RECT 0 9.2047 0.133 9.2173 ;
		RECT 0 9.3553 0.133 9.3678 ;
		RECT 0 9.5059 0.133 9.5184 ;
		RECT 0 9.6565 0.133 10.4973 ;
		RECT 0 10.6353 0.133 10.6478 ;
		RECT 0 10.7859 0.133 10.7984 ;
		RECT 0 10.9365 0.133 10.949 ;
		RECT 0 11.0871 0.133 11.0996 ;
		RECT 0 11.2376 0.133 12.0784 ;
		RECT 0 12.2165 0.133 12.229 ;
		RECT 0 12.3671 0.133 12.3796 ;
		RECT 0 12.5176 0.133 12.5302 ;
		RECT 0 12.6682 0.133 12.6808 ;
		RECT 0 12.8188 0.133 13.6596 ;
		RECT 0 13.7976 0.133 13.8102 ;
		RECT 0 13.9482 0.133 13.9608 ;
		RECT 0 14.0988 0.133 14.1114 ;
		RECT 0 14.2494 0.133 14.262 ;
		RECT 0 14.4 0.133 15.2408 ;
		RECT 0 15.3788 0.133 15.3914 ;
		RECT 0 15.5294 0.133 15.542 ;
		RECT 0 15.68 0.133 15.6925 ;
		RECT 0 15.8306 0.133 15.8431 ;
		RECT 0 15.9812 0.133 16.822 ;
		RECT 0 16.96 0.133 16.9725 ;
		RECT 0 17.1106 0.133 17.1231 ;
		RECT 0 17.2612 0.133 17.2737 ;
		RECT 0 17.4118 0.133 17.4243 ;
		RECT 0 17.5624 0.133 18.4031 ;
		RECT 0 18.5412 0.133 18.5537 ;
		RECT 0 18.6918 0.133 18.7043 ;
		RECT 0 18.8424 0.133 18.8549 ;
		RECT 0 18.9929 0.133 19.0055 ;
		RECT 0 19.1435 0.133 19.9843 ;
		RECT 0 20.1224 0.133 20.1349 ;
		RECT 0 20.2729 0.133 20.2855 ;
		RECT 0 20.4235 0.133 20.4361 ;
		RECT 0 20.5741 0.133 20.5867 ;
		RECT 0 20.7247 0.133 21.5655 ;
		RECT 0 21.7035 0.133 21.7161 ;
		RECT 0 21.8541 0.133 21.8667 ;
		RECT 0 22.0047 0.133 22.0173 ;
		RECT 0 22.1553 0.133 22.1678 ;
		RECT 0 22.3059 0.133 23.1467 ;
		RECT 0 23.2847 0.133 23.2973 ;
		RECT 0 23.4353 0.133 23.4478 ;
		RECT 0 23.5859 0.133 23.5984 ;
		RECT 0 23.7365 0.133 23.749 ;
		RECT 0 23.8871 0.133 24.7278 ;
		RECT 0 24.8659 0.133 24.8784 ;
		RECT 0 25.0165 0.133 25.029 ;
		RECT 0 25.1671 0.133 25.1796 ;
		RECT 0 25.3176 0.133 25.3302 ;
		RECT 0 25.4682 0.133 27.1498 ;
		RECT 0 27.2878 0.133 27.3004 ;
		RECT 0.0714 27.3004 0.133 27.6016 ;
		RECT 0 27.4384 0.133 27.6016 ;
		RECT 0 27.7396 0.133 28.0533 ;
		RECT 0 28.1914 0.133 28.2039 ;
		RECT 0 28.342 0.133 28.3545 ;
		RECT 0 28.869 0.133 29.0573 ;
		RECT 0 29.1953 0.133 29.2078 ;
		RECT 0 29.3459 0.133 29.3584 ;
		RECT 0 29.622 0.133 29.6345 ;
		RECT 0 29.7725 0.133 30.0863 ;
		RECT 0 30.2243 0.133 30.2369 ;
		RECT 0 30.6259 0.133 30.6384 ;
		RECT 0 30.902 0.133 31.1655 ;
		RECT 0 31.3035 0.133 31.4165 ;
		RECT 0 31.68 0.133 31.6925 ;
		RECT 0 32.2071 0.133 32.2196 ;
		RECT 0 32.7341 0.133 33.5247 ;
		RECT 0 33.7882 0.133 34.0518 ;
		RECT 0 34.1898 0.133 34.2024 ;
		RECT 0 34.3404 0.133 34.3529 ;
		RECT 0 34.491 0.133 36.1788 ;
		RECT 0 36.3169 0.133 36.3294 ;
		RECT 0 36.4675 0.133 36.48 ;
		RECT 0 36.618 0.133 36.6306 ;
		RECT 0 36.7686 0.133 36.7812 ;
		RECT 0 36.9192 0.133 37.76 ;
		RECT 0 37.898 0.133 37.9106 ;
		RECT 0 38.0486 0.133 38.0612 ;
		RECT 0 38.1992 0.133 38.2118 ;
		RECT 0 38.3498 0.133 38.3624 ;
		RECT 0 38.5004 0.133 39.3412 ;
		RECT 0 39.4792 0.133 39.4918 ;
		RECT 0 39.6298 0.133 39.6424 ;
		RECT 0 39.7804 0.133 39.7929 ;
		RECT 0 39.931 0.133 39.9435 ;
		RECT 0 40.0816 0.133 40.9224 ;
		RECT 0 41.0604 0.133 41.0729 ;
		RECT 0 41.211 0.133 41.2235 ;
		RECT 0 41.3616 0.133 41.3741 ;
		RECT 0 41.5122 0.133 41.5247 ;
		RECT 0 41.6627 0.133 42.5035 ;
		RECT 0 42.6416 0.133 42.6541 ;
		RECT 0 42.7922 0.133 42.8047 ;
		RECT 0 42.9427 0.133 42.9553 ;
		RECT 0 43.0933 0.133 43.1059 ;
		RECT 0 43.2439 0.133 44.0847 ;
		RECT 0 44.2227 0.133 44.2353 ;
		RECT 0 44.3733 0.133 44.3859 ;
		RECT 0 44.5239 0.133 44.5365 ;
		RECT 0 44.6745 0.133 44.6871 ;
		RECT 0 44.8251 0.133 45.6659 ;
		RECT 0 45.8039 0.133 45.8165 ;
		RECT 0 45.9545 0.133 45.9671 ;
		RECT 0 46.1051 0.133 46.1176 ;
		RECT 0 46.2557 0.133 46.2682 ;
		RECT 0 46.4063 0.133 47.2471 ;
		RECT 0 47.3851 0.133 47.3976 ;
		RECT 0 47.5357 0.133 47.5482 ;
		RECT 0 47.6863 0.133 47.6988 ;
		RECT 0 47.8369 0.133 47.8494 ;
		RECT 0 47.9875 0.133 48.8282 ;
		RECT 0 48.9663 0.133 48.9788 ;
		RECT 0 49.1169 0.133 49.1294 ;
		RECT 0 49.2675 0.133 49.28 ;
		RECT 0 49.418 0.133 49.4306 ;
		RECT 0 49.5686 0.133 50.4094 ;
		RECT 0 50.5475 0.133 50.56 ;
		RECT 0 50.698 0.133 50.7106 ;
		RECT 0 50.8486 0.133 50.8612 ;
		RECT 0 50.9992 0.133 51.0118 ;
		RECT 0 51.1498 0.133 51.9906 ;
		RECT 0 52.1286 0.133 52.1412 ;
		RECT 0 52.2792 0.133 52.2918 ;
		RECT 0 52.4298 0.133 52.4424 ;
		RECT 0 52.5804 0.133 52.5929 ;
		RECT 0 52.731 0.133 53.5718 ;
		RECT 0 53.7098 0.133 53.7224 ;
		RECT 0 53.8604 0.133 53.8729 ;
		RECT 0 54.011 0.133 54.0235 ;
		RECT 0 54.1616 0.133 54.1741 ;
		RECT 0 54.3122 0.133 55.1529 ;
		RECT 0 55.291 0.133 55.3035 ;
		RECT 0 55.4416 0.133 55.4541 ;
		RECT 0 55.5922 0.133 55.6047 ;
		RECT 0 55.7427 0.133 55.7553 ;
		RECT 0 55.8933 0.133 56.7341 ;
		RECT 0 56.8722 0.133 56.8847 ;
		RECT 0 57.0227 0.133 57.0353 ;
		RECT 0 57.1733 0.133 57.1859 ;
		RECT 0 57.3239 0.133 57.3365 ;
		RECT 0 57.4745 0.133 58.3153 ;
		RECT 0 58.4533 0.133 58.4659 ;
		RECT 0 58.6039 0.133 58.6165 ;
		RECT 0 58.7545 0.133 58.7671 ;
		RECT 0 58.9051 0.133 58.9176 ;
		RECT 0 59.0557 0.133 59.8965 ;
		RECT 0 60.0345 0.133 60.0471 ;
		RECT 0 60.1851 0.133 60.1976 ;
		RECT 0 60.3357 0.133 60.3482 ;
		RECT 0 60.4863 0.133 60.4988 ;
		RECT 0 60.6369 0.133 61.4776 ;
		RECT 0 61.6157 0.133 61.6282 ;
		RECT 0 61.7663 0.133 61.7788 ;
		RECT 0 61.9169 0.133 61.9294 ;
		RECT 0 62.0675 0.133 62.08 ;
		RECT 0 62.218 0.133 63.0212 ;
		RECT 0 63.1592 0.133 63.2282 ;
		 LAYER M3 ;
		RECT 0.0098 27.1686 0.0481 27.269 ;
		RECT 0.0098 27.4698 0.0481 27.5702 ;
		RECT 0.0714 27.771 0.1097 27.8714 ;
		RECT 0.0714 27.9216 0.1097 28.022 ;
		RECT 0.0714 28.6243 0.1097 28.7247 ;
		RECT 0.0098 28.9255 0.0481 29.0259 ;
		RECT 0.0714 28.9255 0.1097 29.0259 ;
		RECT 0.0098 29.3773 0.0481 29.4776 ;
		RECT 0.0714 29.8039 0.1097 29.9043 ;
		RECT 0.0714 29.9545 0.1097 30.0549 ;
		RECT 0.0714 30.9082 0.1097 31.0086 ;
		RECT 0.0714 31.0337 0.1097 31.1341 ;
		RECT 0.0714 31.3098 0.1097 31.4102 ;
		RECT 0.0714 32.7655 0.1097 32.8659 ;
		RECT 0.0714 32.891 0.1097 32.9914 ;
		RECT 0.0714 33.0165 0.1097 33.1169 ;
		RECT 0.0714 33.142 0.1097 33.2424 ;
		RECT 0.0714 33.2925 0.1097 33.3929 ;
		RECT 0.0714 33.418 0.1097 33.5184 ;
		RECT 0.0714 33.8196 0.1097 33.92 ;
		RECT 0.0714 33.9451 0.1097 34.0455 ;
		 LAYER M3 SPACING 0.012 ;
		RECT 0.0098 27.1686 0.0481 27.269 ;
		RECT 0.0098 27.4698 0.0481 27.5702 ;
		RECT 0.0714 27.771 0.1097 27.8714 ;
		RECT 0.0714 27.9216 0.1097 28.022 ;
		RECT 0.0714 28.6243 0.1097 28.7247 ;
		RECT 0.0098 28.9255 0.0481 29.0259 ;
		RECT 0.0714 28.9255 0.1097 29.0259 ;
		RECT 0.0098 29.3773 0.0481 29.4776 ;
		RECT 0.0714 29.8039 0.1097 29.9043 ;
		RECT 0.0714 29.9545 0.1097 30.0549 ;
		RECT 0.0714 30.9082 0.1097 31.0086 ;
		RECT 0.0714 31.0337 0.1097 31.1341 ;
		RECT 0.0714 31.3098 0.1097 31.4102 ;
		RECT 0.0714 32.7655 0.1097 32.8659 ;
		RECT 0.0714 32.891 0.1097 32.9914 ;
		RECT 0.0714 33.0165 0.1097 33.1169 ;
		RECT 0.0714 33.142 0.1097 33.2424 ;
		RECT 0.0714 33.2925 0.1097 33.3929 ;
		RECT 0.0714 33.418 0.1097 33.5184 ;
		RECT 0.0714 33.8196 0.1097 33.92 ;
		RECT 0.0714 33.9451 0.1097 34.0455 ;
		 LAYER M4 SPACING 0.018 ;
		RECT 0.2105 0.3984 12.558 0.8439 ;
		RECT 12.558 0.3984 12.705 0.8439 ;
		RECT 0.2105 1.189 12.558 1.6345 ;
		RECT 12.558 1.189 12.705 1.6345 ;
		RECT 0.2105 1.9796 12.558 2.4251 ;
		RECT 12.558 1.9796 12.705 2.4251 ;
		RECT 0.2105 2.7702 12.558 3.2157 ;
		RECT 12.558 2.7702 12.705 3.2157 ;
		RECT 0.2105 3.5608 12.558 4.0063 ;
		RECT 12.558 3.5608 12.705 4.0063 ;
		RECT 0.2105 4.3514 12.558 4.7969 ;
		RECT 12.558 4.3514 12.705 4.7969 ;
		RECT 0.2105 5.142 12.558 5.5875 ;
		RECT 12.558 5.142 12.705 5.5875 ;
		RECT 0.2105 5.9325 12.558 6.378 ;
		RECT 12.558 5.9325 12.705 6.378 ;
		RECT 0.2105 6.7231 12.558 7.1686 ;
		RECT 12.558 6.7231 12.705 7.1686 ;
		RECT 0.2105 7.5137 12.558 7.9592 ;
		RECT 12.558 7.5137 12.705 7.9592 ;
		RECT 0.2105 8.3043 12.558 8.7498 ;
		RECT 12.558 8.3043 12.705 8.7498 ;
		RECT 0.2105 9.0949 12.558 9.5404 ;
		RECT 12.558 9.0949 12.705 9.5404 ;
		RECT 0.2105 9.8855 12.558 10.331 ;
		RECT 12.558 9.8855 12.705 10.331 ;
		RECT 0.2105 10.6761 12.558 11.1216 ;
		RECT 12.558 10.6761 12.705 11.1216 ;
		RECT 0.2105 11.4667 12.558 11.9122 ;
		RECT 12.558 11.4667 12.705 11.9122 ;
		RECT 0.2105 12.2573 12.558 12.7027 ;
		RECT 12.558 12.2573 12.705 12.7027 ;
		RECT 0.2105 13.0478 12.558 13.4933 ;
		RECT 12.558 13.0478 12.705 13.4933 ;
		RECT 0.2105 13.8384 12.558 14.2839 ;
		RECT 12.558 13.8384 12.705 14.2839 ;
		RECT 0.2105 14.629 12.558 15.0745 ;
		RECT 12.558 14.629 12.705 15.0745 ;
		RECT 0.2105 15.4196 12.558 15.8651 ;
		RECT 12.558 15.4196 12.705 15.8651 ;
		RECT 0.2105 16.2102 12.558 16.6557 ;
		RECT 12.558 16.2102 12.705 16.6557 ;
		RECT 0.2105 17.0008 12.558 17.4463 ;
		RECT 12.558 17.0008 12.705 17.4463 ;
		RECT 0.2105 17.7914 12.558 18.2369 ;
		RECT 12.558 17.7914 12.705 18.2369 ;
		RECT 0.2105 18.582 12.558 19.0275 ;
		RECT 12.558 18.582 12.705 19.0275 ;
		RECT 0.2105 19.3725 12.558 19.818 ;
		RECT 12.558 19.3725 12.705 19.818 ;
		RECT 0.2105 20.1631 12.558 20.6086 ;
		RECT 12.558 20.1631 12.705 20.6086 ;
		RECT 0.2105 20.9537 12.558 21.3992 ;
		RECT 12.558 20.9537 12.705 21.3992 ;
		RECT 0.2105 21.7443 12.558 22.1898 ;
		RECT 12.558 21.7443 12.705 22.1898 ;
		RECT 0.2105 22.5349 12.558 22.9804 ;
		RECT 12.558 22.5349 12.705 22.9804 ;
		RECT 0.2105 23.3255 12.558 23.771 ;
		RECT 12.558 23.3255 12.705 23.771 ;
		RECT 0.2105 24.1161 12.558 24.5616 ;
		RECT 12.558 24.1161 12.705 24.5616 ;
		RECT 0.2105 24.9067 12.558 25.3522 ;
		RECT 12.558 24.9067 12.705 25.3522 ;
		RECT 0.2105 25.6973 12.558 26.1427 ;
		RECT 12.558 25.6973 12.705 26.1427 ;
		RECT 0.2105 26.4878 12.558 26.9333 ;
		RECT 12.558 26.4878 12.705 26.9333 ;
		RECT 0.2105 27.4667 12.558 27.6031 ;
		RECT 12.558 27.4667 12.705 27.6031 ;
		RECT 0.2105 27.7914 12.558 27.8949 ;
		RECT 12.558 27.7914 12.705 27.8949 ;
		RECT 0.2105 28.0831 12.558 28.422 ;
		RECT 12.558 28.0831 12.705 28.422 ;
		RECT 0.2105 28.6102 12.558 28.949 ;
		RECT 12.558 28.6102 12.705 28.949 ;
		RECT 0.2105 29.1373 12.558 29.4761 ;
		RECT 12.558 29.1373 12.705 29.4761 ;
		RECT 0.2105 29.6643 12.558 30.0031 ;
		RECT 12.558 29.6643 12.705 30.0031 ;
		RECT 0.2105 30.1914 12.558 31.0573 ;
		RECT 12.558 30.1914 12.705 31.0573 ;
		RECT 0.2105 31.2455 12.558 32.1114 ;
		RECT 12.558 31.2455 12.705 32.1114 ;
		RECT 0.2105 32.2996 12.558 32.6384 ;
		RECT 12.558 32.2996 12.705 32.6384 ;
		RECT 0.2105 32.8267 12.558 33.1655 ;
		RECT 12.558 32.8267 12.705 33.1655 ;
		RECT 0.2105 33.3537 12.558 33.6925 ;
		RECT 12.558 33.3537 12.705 33.6925 ;
		RECT 0.2105 34.251 12.558 34.3373 ;
		RECT 12.558 34.251 12.705 34.3373 ;
		RECT 0.2105 34.7137 12.558 35.1592 ;
		RECT 12.558 34.7137 12.705 35.1592 ;
		RECT 0.2105 35.5043 12.558 35.9498 ;
		RECT 12.558 35.5043 12.705 35.9498 ;
		RECT 0.2105 36.2949 12.558 36.7404 ;
		RECT 12.558 36.2949 12.705 36.7404 ;
		RECT 0.2105 37.0855 12.558 37.531 ;
		RECT 12.558 37.0855 12.705 37.531 ;
		RECT 0.2105 37.8761 12.558 38.3216 ;
		RECT 12.558 37.8761 12.705 38.3216 ;
		RECT 0.2105 38.6667 12.558 39.1122 ;
		RECT 12.558 38.6667 12.705 39.1122 ;
		RECT 0.2105 39.4573 12.558 39.9027 ;
		RECT 12.558 39.4573 12.705 39.9027 ;
		RECT 0.2105 40.2478 12.558 40.6933 ;
		RECT 12.558 40.2478 12.705 40.6933 ;
		RECT 0.2105 41.0384 12.558 41.4839 ;
		RECT 12.558 41.0384 12.705 41.4839 ;
		RECT 0.2105 41.829 12.558 42.2745 ;
		RECT 12.558 41.829 12.705 42.2745 ;
		RECT 0.2105 42.6196 12.558 43.0651 ;
		RECT 12.558 42.6196 12.705 43.0651 ;
		RECT 0.2105 43.4102 12.558 43.8557 ;
		RECT 12.558 43.4102 12.705 43.8557 ;
		RECT 0.2105 44.2008 12.558 44.6463 ;
		RECT 12.558 44.2008 12.705 44.6463 ;
		RECT 0.2105 44.9914 12.558 45.4369 ;
		RECT 12.558 44.9914 12.705 45.4369 ;
		RECT 0.2105 45.782 12.558 46.2275 ;
		RECT 12.558 45.782 12.705 46.2275 ;
		RECT 0.2105 46.5725 12.558 47.018 ;
		RECT 12.558 46.5725 12.705 47.018 ;
		RECT 0.2105 47.3631 12.558 47.8086 ;
		RECT 12.558 47.3631 12.705 47.8086 ;
		RECT 0.2105 48.1537 12.558 48.5992 ;
		RECT 12.558 48.1537 12.705 48.5992 ;
		RECT 0.2105 48.9443 12.558 49.3898 ;
		RECT 12.558 48.9443 12.705 49.3898 ;
		RECT 0.2105 49.7349 12.558 50.1804 ;
		RECT 12.558 49.7349 12.705 50.1804 ;
		RECT 0.2105 50.5255 12.558 50.971 ;
		RECT 12.558 50.5255 12.705 50.971 ;
		RECT 0.2105 51.3161 12.558 51.7616 ;
		RECT 12.558 51.3161 12.705 51.7616 ;
		RECT 0.2105 52.1067 12.558 52.5522 ;
		RECT 12.558 52.1067 12.705 52.5522 ;
		RECT 0.2105 52.8973 12.558 53.3427 ;
		RECT 12.558 52.8973 12.705 53.3427 ;
		RECT 0.2105 53.6878 12.558 54.1333 ;
		RECT 12.558 53.6878 12.705 54.1333 ;
		RECT 0.2105 54.4784 12.558 54.9239 ;
		RECT 12.558 54.4784 12.705 54.9239 ;
		RECT 0.2105 55.269 12.558 55.7145 ;
		RECT 12.558 55.269 12.705 55.7145 ;
		RECT 0.2105 56.0596 12.558 56.5051 ;
		RECT 12.558 56.0596 12.705 56.5051 ;
		RECT 0.2105 56.8502 12.558 57.2957 ;
		RECT 12.558 56.8502 12.705 57.2957 ;
		RECT 0.2105 57.6408 12.558 58.0863 ;
		RECT 12.558 57.6408 12.705 58.0863 ;
		RECT 0.2105 58.4314 12.558 58.8769 ;
		RECT 12.558 58.4314 12.705 58.8769 ;
		RECT 0.2105 59.222 12.558 59.6675 ;
		RECT 12.558 59.222 12.705 59.6675 ;
		RECT 0.2105 60.0125 12.558 60.458 ;
		RECT 12.558 60.0125 12.705 60.458 ;
		RECT 0.2105 60.8031 12.558 61.2486 ;
		RECT 12.558 60.8031 12.705 61.2486 ;
		RECT 0.2105 61.5937 12.558 62.0392 ;
		RECT 12.558 61.5937 12.705 62.0392 ;
		RECT 0.2105 62.3843 12.558 62.8298 ;
		RECT 12.558 62.3843 12.705 62.8298 ;
		 LAYER M4 ;
		RECT 0.2105 0 12.558 0.022 ;
		RECT 12.558 0 12.705 0.022 ;
		RECT 0.2105 34.0376 12.558 34.0627 ;
		RECT 12.558 34.0376 12.705 34.0627 ;
		RECT 0.2105 63.2063 12.558 63.2282 ;
		RECT 12.558 63.2063 12.705 63.2282 ;
		 LAYER M4 SPACING 0.018 ;
		RECT 0.2105 0 12.558 0.022 ;
		RECT 12.558 0 12.705 0.022 ;
		RECT 0.2105 34.0376 12.558 34.0627 ;
		RECT 12.558 34.0376 12.705 34.0627 ;
		RECT 0.2105 63.2063 12.558 63.2282 ;
		RECT 12.558 63.2063 12.705 63.2282 ;
		 LAYER V1 SPACING 0 ;
		RECT 0 0 12.705 63.2282 ;
		 LAYER V2 SPACING 0 ;
		RECT 0.1097 0 12.705 63.2282 ;
		RECT 0 0 0.1097 0.0878 ;
		RECT 0 0.1882 0.1097 1.029 ;
		RECT 0 1.029 0.0098 1.1294 ;
		RECT 0 1.1294 0.1097 1.1796 ;
		RECT 0 1.28 0.1097 1.3302 ;
		RECT 0 1.4306 0.1097 1.4808 ;
		RECT 0 1.5812 0.1097 1.6314 ;
		RECT 0 1.6314 0.0098 1.7318 ;
		RECT 0 1.7318 0.1097 2.6102 ;
		RECT 0 2.6102 0.0098 2.7106 ;
		RECT 0 2.7106 0.1097 2.7608 ;
		RECT 0 2.8612 0.1097 2.9114 ;
		RECT 0 3.0118 0.1097 3.062 ;
		RECT 0 3.1624 0.1097 3.2125 ;
		RECT 0 3.2125 0.0098 3.3129 ;
		RECT 0 3.3129 0.1097 4.1914 ;
		RECT 0 4.1914 0.0098 4.2918 ;
		RECT 0 4.2918 0.1097 4.342 ;
		RECT 0 4.4424 0.1097 4.4925 ;
		RECT 0 4.5929 0.1097 4.6431 ;
		RECT 0 4.7435 0.1097 4.7937 ;
		RECT 0 4.7937 0.0098 4.8941 ;
		RECT 0 4.8941 0.1097 5.7725 ;
		RECT 0 5.7725 0.0098 5.8729 ;
		RECT 0 5.8729 0.1097 5.9231 ;
		RECT 0 6.0235 0.1097 6.0737 ;
		RECT 0 6.1741 0.1097 6.2243 ;
		RECT 0 6.3247 0.1097 6.3749 ;
		RECT 0 6.3749 0.0098 6.4753 ;
		RECT 0 6.4753 0.1097 7.3537 ;
		RECT 0 7.3537 0.0098 7.4541 ;
		RECT 0 7.4541 0.1097 7.5043 ;
		RECT 0 7.6047 0.1097 7.6549 ;
		RECT 0 7.7553 0.1097 7.8055 ;
		RECT 0 7.9059 0.1097 7.9561 ;
		RECT 0 7.9561 0.0098 8.0565 ;
		RECT 0 8.0565 0.1097 8.9349 ;
		RECT 0 8.9349 0.0098 9.0353 ;
		RECT 0 9.0353 0.1097 9.0855 ;
		RECT 0 9.1859 0.1097 9.2361 ;
		RECT 0 9.3365 0.1097 9.3867 ;
		RECT 0 9.4871 0.1097 9.5373 ;
		RECT 0 9.5373 0.0098 9.6376 ;
		RECT 0 9.6376 0.1097 10.5161 ;
		RECT 0 10.5161 0.0098 10.6165 ;
		RECT 0 10.6165 0.1097 10.6667 ;
		RECT 0 10.7671 0.1097 10.8173 ;
		RECT 0 10.9176 0.1097 10.9678 ;
		RECT 0 11.0682 0.1097 11.1184 ;
		RECT 0 11.1184 0.0098 11.2188 ;
		RECT 0 11.2188 0.1097 12.0973 ;
		RECT 0 12.0973 0.0098 12.1976 ;
		RECT 0 12.1976 0.1097 12.2478 ;
		RECT 0 12.3482 0.1097 12.3984 ;
		RECT 0 12.4988 0.1097 12.549 ;
		RECT 0 12.6494 0.1097 12.6996 ;
		RECT 0 12.6996 0.0098 12.8 ;
		RECT 0 12.8 0.1097 13.6784 ;
		RECT 0 13.6784 0.0098 13.7788 ;
		RECT 0 13.7788 0.1097 13.829 ;
		RECT 0 13.9294 0.1097 13.9796 ;
		RECT 0 14.08 0.1097 14.1302 ;
		RECT 0 14.2306 0.1097 14.2808 ;
		RECT 0 14.2808 0.0098 14.3812 ;
		RECT 0 14.3812 0.1097 15.2596 ;
		RECT 0 15.2596 0.0098 15.36 ;
		RECT 0 15.36 0.1097 15.4102 ;
		RECT 0 15.5106 0.1097 15.5608 ;
		RECT 0 15.6612 0.1097 15.7114 ;
		RECT 0 15.8118 0.1097 15.862 ;
		RECT 0 15.862 0.0098 15.9624 ;
		RECT 0 15.9624 0.1097 16.8408 ;
		RECT 0 16.8408 0.0098 16.9412 ;
		RECT 0 16.9412 0.1097 16.9914 ;
		RECT 0 17.0918 0.1097 17.142 ;
		RECT 0 17.2424 0.1097 17.2925 ;
		RECT 0 17.3929 0.1097 17.4431 ;
		RECT 0 17.4431 0.0098 17.5435 ;
		RECT 0 17.5435 0.1097 18.422 ;
		RECT 0 18.422 0.0098 18.5224 ;
		RECT 0 18.5224 0.1097 18.5725 ;
		RECT 0 18.6729 0.1097 18.7231 ;
		RECT 0 18.8235 0.1097 18.8737 ;
		RECT 0 18.9741 0.1097 19.0243 ;
		RECT 0 19.0243 0.0098 19.1247 ;
		RECT 0 19.1247 0.1097 20.0031 ;
		RECT 0 20.0031 0.0098 20.1035 ;
		RECT 0 20.1035 0.1097 20.1537 ;
		RECT 0 20.2541 0.1097 20.3043 ;
		RECT 0 20.4047 0.1097 20.4549 ;
		RECT 0 20.5553 0.1097 20.6055 ;
		RECT 0 20.6055 0.0098 20.7059 ;
		RECT 0 20.7059 0.1097 21.5843 ;
		RECT 0 21.5843 0.0098 21.6847 ;
		RECT 0 21.6847 0.1097 21.7349 ;
		RECT 0 21.8353 0.1097 21.8855 ;
		RECT 0 21.9859 0.1097 22.0361 ;
		RECT 0 22.1365 0.1097 22.1867 ;
		RECT 0 22.1867 0.0098 22.2871 ;
		RECT 0 22.2871 0.1097 23.1655 ;
		RECT 0 23.1655 0.0098 23.2659 ;
		RECT 0 23.2659 0.1097 23.3161 ;
		RECT 0 23.4165 0.1097 23.4667 ;
		RECT 0 23.5671 0.1097 23.6173 ;
		RECT 0 23.7176 0.1097 23.7678 ;
		RECT 0 23.7678 0.0098 23.8682 ;
		RECT 0 23.8682 0.1097 24.7467 ;
		RECT 0 24.7467 0.0098 24.8471 ;
		RECT 0 24.8471 0.1097 24.8973 ;
		RECT 0 24.9976 0.1097 25.0478 ;
		RECT 0 25.1482 0.1097 25.1984 ;
		RECT 0 25.2988 0.1097 25.349 ;
		RECT 0 25.349 0.0098 25.4494 ;
		RECT 0 25.4494 0.1097 27.1686 ;
		RECT 0 27.269 0.1097 27.3192 ;
		RECT 0 27.4196 0.1097 27.6204 ;
		RECT 0 27.6204 0.0098 27.7208 ;
		RECT 0 27.7208 0.1097 28.0722 ;
		RECT 0 28.0722 0.0098 28.1725 ;
		RECT 0 28.1725 0.1097 28.2227 ;
		RECT 0 28.2227 0.0098 28.3231 ;
		RECT 0 28.3231 0.1097 28.3733 ;
		RECT 0 28.4737 0.1097 28.4988 ;
		RECT 0 28.5992 0.1097 28.6243 ;
		RECT 0 28.6243 0.0098 28.7247 ;
		RECT 0 28.7247 0.1097 28.7498 ;
		RECT 0 28.8502 0.1097 29.0761 ;
		RECT 0 29.0761 0.0098 29.1765 ;
		RECT 0 29.1765 0.1097 29.2267 ;
		RECT 0 29.2267 0.0098 29.3271 ;
		RECT 0 29.3271 0.1097 29.3773 ;
		RECT 0 29.4776 0.1097 29.5027 ;
		RECT 0 29.5027 0.0098 29.6031 ;
		RECT 0 29.6031 0.1097 29.6533 ;
		RECT 0 29.6533 0.0098 29.7537 ;
		RECT 0 29.7537 0.1097 30.1051 ;
		RECT 0 30.1051 0.0098 30.2055 ;
		RECT 0 30.2055 0.1097 30.2557 ;
		RECT 0 30.2557 0.0098 30.3561 ;
		RECT 0 30.3561 0.1097 30.3812 ;
		RECT 0 30.3812 0.0098 30.4816 ;
		RECT 0 30.4816 0.1097 30.5067 ;
		RECT 0 30.5067 0.0098 30.6071 ;
		RECT 0 30.6071 0.1097 30.6573 ;
		RECT 0 30.6573 0.0098 30.7576 ;
		RECT 0 30.7576 0.1097 30.7827 ;
		RECT 0 30.7827 0.0098 30.8831 ;
		RECT 0 30.8831 0.1097 31.1843 ;
		RECT 0 31.1843 0.0098 31.2847 ;
		RECT 0 31.2847 0.1097 31.4353 ;
		RECT 0 31.4353 0.0098 31.5357 ;
		RECT 0 31.5357 0.1097 31.5608 ;
		RECT 0 31.5608 0.0098 31.6612 ;
		RECT 0 31.6612 0.1097 31.7114 ;
		RECT 0 31.7114 0.0098 31.8118 ;
		RECT 0 31.8118 0.1097 31.8369 ;
		RECT 0 31.8369 0.0098 31.9373 ;
		RECT 0 31.9373 0.1097 31.9624 ;
		RECT 0 31.9624 0.0098 32.0627 ;
		RECT 0 32.0627 0.1097 32.0878 ;
		RECT 0 32.0878 0.0098 32.1882 ;
		RECT 0 32.1882 0.1097 32.2384 ;
		RECT 0 32.2384 0.0098 32.3388 ;
		RECT 0 32.3388 0.1097 32.3639 ;
		RECT 0 32.3639 0.0098 32.4643 ;
		RECT 0 32.4643 0.1097 32.4894 ;
		RECT 0 32.4894 0.0098 32.5898 ;
		RECT 0 32.5898 0.1097 32.6149 ;
		RECT 0 32.6149 0.0098 32.7153 ;
		RECT 0 32.7153 0.1097 33.5435 ;
		RECT 0 33.5435 0.0098 33.6439 ;
		RECT 0 33.6439 0.1097 33.669 ;
		RECT 0 33.669 0.0098 33.7694 ;
		RECT 0 33.7694 0.1097 34.0706 ;
		RECT 0 34.0706 0.0098 34.171 ;
		RECT 0 34.171 0.1097 34.2212 ;
		RECT 0 34.2212 0.0098 34.3216 ;
		RECT 0 34.3216 0.1097 34.3718 ;
		RECT 0 34.3718 0.0098 34.4722 ;
		RECT 0 34.4722 0.1097 36.1976 ;
		RECT 0 36.1976 0.0098 36.298 ;
		RECT 0 36.298 0.1097 36.3482 ;
		RECT 0 36.4486 0.1097 36.4988 ;
		RECT 0 36.5992 0.1097 36.6494 ;
		RECT 0 36.7498 0.1097 36.8 ;
		RECT 0 36.8 0.0098 36.9004 ;
		RECT 0 36.9004 0.1097 37.7788 ;
		RECT 0 37.7788 0.0098 37.8792 ;
		RECT 0 37.8792 0.1097 37.9294 ;
		RECT 0 38.0298 0.1097 38.08 ;
		RECT 0 38.1804 0.1097 38.2306 ;
		RECT 0 38.331 0.1097 38.3812 ;
		RECT 0 38.3812 0.0098 38.4816 ;
		RECT 0 38.4816 0.1097 39.36 ;
		RECT 0 39.36 0.0098 39.4604 ;
		RECT 0 39.4604 0.1097 39.5106 ;
		RECT 0 39.611 0.1097 39.6612 ;
		RECT 0 39.7616 0.1097 39.8118 ;
		RECT 0 39.9122 0.1097 39.9624 ;
		RECT 0 39.9624 0.0098 40.0627 ;
		RECT 0 40.0627 0.1097 40.9412 ;
		RECT 0 40.9412 0.0098 41.0416 ;
		RECT 0 41.0416 0.1097 41.0918 ;
		RECT 0 41.1922 0.1097 41.2424 ;
		RECT 0 41.3427 0.1097 41.3929 ;
		RECT 0 41.4933 0.1097 41.5435 ;
		RECT 0 41.5435 0.0098 41.6439 ;
		RECT 0 41.6439 0.1097 42.5224 ;
		RECT 0 42.5224 0.0098 42.6227 ;
		RECT 0 42.6227 0.1097 42.6729 ;
		RECT 0 42.7733 0.1097 42.8235 ;
		RECT 0 42.9239 0.1097 42.9741 ;
		RECT 0 43.0745 0.1097 43.1247 ;
		RECT 0 43.1247 0.0098 43.2251 ;
		RECT 0 43.2251 0.1097 44.1035 ;
		RECT 0 44.1035 0.0098 44.2039 ;
		RECT 0 44.2039 0.1097 44.2541 ;
		RECT 0 44.3545 0.1097 44.4047 ;
		RECT 0 44.5051 0.1097 44.5553 ;
		RECT 0 44.6557 0.1097 44.7059 ;
		RECT 0 44.7059 0.0098 44.8063 ;
		RECT 0 44.8063 0.1097 45.6847 ;
		RECT 0 45.6847 0.0098 45.7851 ;
		RECT 0 45.7851 0.1097 45.8353 ;
		RECT 0 45.9357 0.1097 45.9859 ;
		RECT 0 46.0863 0.1097 46.1365 ;
		RECT 0 46.2369 0.1097 46.2871 ;
		RECT 0 46.2871 0.0098 46.3875 ;
		RECT 0 46.3875 0.1097 47.2659 ;
		RECT 0 47.2659 0.0098 47.3663 ;
		RECT 0 47.3663 0.1097 47.4165 ;
		RECT 0 47.5169 0.1097 47.5671 ;
		RECT 0 47.6675 0.1097 47.7176 ;
		RECT 0 47.818 0.1097 47.8682 ;
		RECT 0 47.8682 0.0098 47.9686 ;
		RECT 0 47.9686 0.1097 48.8471 ;
		RECT 0 48.8471 0.0098 48.9475 ;
		RECT 0 48.9475 0.1097 48.9976 ;
		RECT 0 49.098 0.1097 49.1482 ;
		RECT 0 49.2486 0.1097 49.2988 ;
		RECT 0 49.3992 0.1097 49.4494 ;
		RECT 0 49.4494 0.0098 49.5498 ;
		RECT 0 49.5498 0.1097 50.4282 ;
		RECT 0 50.4282 0.0098 50.5286 ;
		RECT 0 50.5286 0.1097 50.5788 ;
		RECT 0 50.6792 0.1097 50.7294 ;
		RECT 0 50.8298 0.1097 50.88 ;
		RECT 0 50.9804 0.1097 51.0306 ;
		RECT 0 51.0306 0.0098 51.131 ;
		RECT 0 51.131 0.1097 52.0094 ;
		RECT 0 52.0094 0.0098 52.1098 ;
		RECT 0 52.1098 0.1097 52.16 ;
		RECT 0 52.2604 0.1097 52.3106 ;
		RECT 0 52.411 0.1097 52.4612 ;
		RECT 0 52.5616 0.1097 52.6118 ;
		RECT 0 52.6118 0.0098 52.7122 ;
		RECT 0 52.7122 0.1097 53.5906 ;
		RECT 0 53.5906 0.0098 53.691 ;
		RECT 0 53.691 0.1097 53.7412 ;
		RECT 0 53.8416 0.1097 53.8918 ;
		RECT 0 53.9922 0.1097 54.0424 ;
		RECT 0 54.1427 0.1097 54.1929 ;
		RECT 0 54.1929 0.0098 54.2933 ;
		RECT 0 54.2933 0.1097 55.1718 ;
		RECT 0 55.1718 0.0098 55.2722 ;
		RECT 0 55.2722 0.1097 55.3224 ;
		RECT 0 55.4227 0.1097 55.4729 ;
		RECT 0 55.5733 0.1097 55.6235 ;
		RECT 0 55.7239 0.1097 55.7741 ;
		RECT 0 55.7741 0.0098 55.8745 ;
		RECT 0 55.8745 0.1097 56.7529 ;
		RECT 0 56.7529 0.0098 56.8533 ;
		RECT 0 56.8533 0.1097 56.9035 ;
		RECT 0 57.0039 0.1097 57.0541 ;
		RECT 0 57.1545 0.1097 57.2047 ;
		RECT 0 57.3051 0.1097 57.3553 ;
		RECT 0 57.3553 0.0098 57.4557 ;
		RECT 0 57.4557 0.1097 58.3341 ;
		RECT 0 58.3341 0.0098 58.4345 ;
		RECT 0 58.4345 0.1097 58.4847 ;
		RECT 0 58.5851 0.1097 58.6353 ;
		RECT 0 58.7357 0.1097 58.7859 ;
		RECT 0 58.8863 0.1097 58.9365 ;
		RECT 0 58.9365 0.0098 59.0369 ;
		RECT 0 59.0369 0.1097 59.9153 ;
		RECT 0 59.9153 0.0098 60.0157 ;
		RECT 0 60.0157 0.1097 60.0659 ;
		RECT 0 60.1663 0.1097 60.2165 ;
		RECT 0 60.3169 0.1097 60.3671 ;
		RECT 0 60.4675 0.1097 60.5176 ;
		RECT 0 60.5176 0.0098 60.618 ;
		RECT 0 60.618 0.1097 61.4965 ;
		RECT 0 61.4965 0.0098 61.5969 ;
		RECT 0 61.5969 0.1097 61.6471 ;
		RECT 0 61.7475 0.1097 61.7976 ;
		RECT 0 61.898 0.1097 61.9482 ;
		RECT 0 62.0486 0.1097 62.0988 ;
		RECT 0 62.0988 0.0098 62.1992 ;
		RECT 0 62.1992 0.1097 63.04 ;
		RECT 0 63.1404 0.1097 63.2282 ;
		 LAYER V2 ;
		RECT 0.0481 27.3192 0.1097 27.6204 ;
		RECT 0.0215 27.2435 0.0364 27.2561 ;
		RECT 0.021 27.5447 0.0359 27.5573 ;
		RECT 0.0831 27.6647 0.098 27.6773 ;
		RECT 0.0831 27.8153 0.098 27.8278 ;
		RECT 0.0831 27.9659 0.098 27.9784 ;
		RECT 0.0831 28.1165 0.098 28.129 ;
		RECT 0.0831 28.2671 0.098 28.2796 ;
		RECT 0.0831 28.6686 0.098 28.6812 ;
		RECT 0.0831 28.9376 0.098 28.9502 ;
		RECT 0.0215 29.0004 0.0364 29.0129 ;
		RECT 0.0831 29.1204 0.098 29.1329 ;
		RECT 0.0831 29.271 0.098 29.2835 ;
		RECT 0.0215 29.3902 0.0364 29.4027 ;
		RECT 0.0831 29.5471 0.098 29.5596 ;
		RECT 0.0831 29.6976 0.098 29.7102 ;
		RECT 0.0831 29.8482 0.098 29.8608 ;
		RECT 0.0831 29.9988 0.098 30.0114 ;
		RECT 0.0831 30.1494 0.098 30.162 ;
		RECT 0.0831 30.3 0.098 30.3125 ;
		RECT 0.0831 30.4255 0.098 30.438 ;
		RECT 0.0831 30.551 0.098 30.5635 ;
		RECT 0.0831 30.7016 0.098 30.7141 ;
		RECT 0.0831 30.8271 0.098 30.8396 ;
		RECT 0.0831 30.9525 0.098 30.9651 ;
		RECT 0.0831 31.078 0.098 31.0906 ;
		RECT 0.0831 31.2286 0.098 31.2412 ;
		RECT 0.0831 31.3541 0.098 31.3667 ;
		RECT 0.0831 31.4796 0.098 31.4922 ;
		RECT 0.0831 31.6051 0.098 31.6176 ;
		RECT 0.0831 31.7557 0.098 31.7682 ;
		RECT 0.0831 31.8812 0.098 31.8937 ;
		RECT 0.0831 32.0067 0.098 32.0192 ;
		RECT 0.0831 32.1322 0.098 32.1447 ;
		RECT 0.0831 32.2827 0.098 32.2953 ;
		RECT 0.0831 32.4082 0.098 32.4208 ;
		RECT 0.0831 32.5337 0.098 32.5463 ;
		RECT 0.0831 32.6592 0.098 32.6718 ;
		RECT 0.0831 32.8098 0.098 32.8224 ;
		RECT 0.0831 32.9353 0.098 32.9478 ;
		RECT 0.0831 33.0608 0.098 33.0733 ;
		RECT 0.0831 33.1863 0.098 33.1988 ;
		RECT 0.0831 33.3369 0.098 33.3494 ;
		RECT 0.0831 33.4624 0.098 33.4749 ;
		RECT 0.0831 33.5878 0.098 33.6004 ;
		RECT 0.0831 33.7133 0.098 33.7259 ;
		RECT 0.0831 33.8639 0.098 33.8765 ;
		RECT 0.0831 33.9894 0.098 34.002 ;
		RECT 0.0831 34.1149 0.098 34.1275 ;
		RECT 0.0831 34.2655 0.098 34.278 ;
		RECT 0.0831 34.4161 0.098 34.4286 ;
		RECT 0.0831 2.6545 0.098 2.6671 ;
		RECT 0.0831 3.2569 0.098 3.2694 ;
		RECT 0.0831 16.8851 0.098 16.8976 ;
		RECT 0.0831 17.4875 0.098 17.5 ;
		RECT 0.0831 18.4663 0.098 18.4788 ;
		RECT 0.0831 19.0686 0.098 19.0812 ;
		RECT 0.0831 20.0475 0.098 20.06 ;
		RECT 0.0831 20.6498 0.098 20.6624 ;
		RECT 0.0831 21.6286 0.098 21.6412 ;
		RECT 0.0831 22.231 0.098 22.2435 ;
		RECT 0.0831 23.2098 0.098 23.2224 ;
		RECT 0.0831 23.8122 0.098 23.8247 ;
		RECT 0.0831 4.2357 0.098 4.2482 ;
		RECT 0.0831 4.838 0.098 4.8506 ;
		RECT 0.0831 5.8169 0.098 5.8294 ;
		RECT 0.0831 6.4192 0.098 6.4318 ;
		RECT 0.0831 7.398 0.098 7.4106 ;
		RECT 0.0831 8.0004 0.098 8.0129 ;
		RECT 0.0831 8.9792 0.098 8.9918 ;
		RECT 0.0831 9.5816 0.098 9.5941 ;
		RECT 0.0831 10.5604 0.098 10.5729 ;
		RECT 0.0831 11.1627 0.098 11.1753 ;
		RECT 0.0831 12.1416 0.098 12.1541 ;
		RECT 0.0831 12.7439 0.098 12.7565 ;
		RECT 0.0831 13.7227 0.098 13.7353 ;
		RECT 0.0831 14.3251 0.098 14.3376 ;
		RECT 0.0831 15.3039 0.098 15.3165 ;
		RECT 0.0831 15.9063 0.098 15.9188 ;
		RECT 0.0831 1.0733 0.098 1.0859 ;
		RECT 0.0831 1.6757 0.098 1.6882 ;
		RECT 0.0831 24.791 0.098 24.8035 ;
		RECT 0.0831 25.3933 0.098 25.4059 ;
		RECT 0.0831 51.0741 0.098 51.0867 ;
		RECT 0.0831 50.4718 0.098 50.4843 ;
		RECT 0.0831 52.6553 0.098 52.6678 ;
		RECT 0.0831 52.0529 0.098 52.0655 ;
		RECT 0.0831 54.2365 0.098 54.249 ;
		RECT 0.0831 53.6341 0.098 53.6467 ;
		RECT 0.0831 55.8176 0.098 55.8302 ;
		RECT 0.0831 55.2153 0.098 55.2278 ;
		RECT 0.0831 57.3988 0.098 57.4114 ;
		RECT 0.0831 56.7965 0.098 56.809 ;
		RECT 0.0831 58.98 0.098 58.9925 ;
		RECT 0.0831 58.3776 0.098 58.3902 ;
		RECT 0.0831 60.5612 0.098 60.5737 ;
		RECT 0.0831 59.9588 0.098 59.9714 ;
		RECT 0.0831 38.4247 0.098 38.4373 ;
		RECT 0.0831 37.8224 0.098 37.8349 ;
		RECT 0.0831 40.0059 0.098 40.0184 ;
		RECT 0.0831 39.4035 0.098 39.4161 ;
		RECT 0.0831 41.5871 0.098 41.5996 ;
		RECT 0.0831 40.9847 0.098 40.9973 ;
		RECT 0.0831 43.1682 0.098 43.1808 ;
		RECT 0.0831 42.5659 0.098 42.5784 ;
		RECT 0.0831 44.7494 0.098 44.762 ;
		RECT 0.0831 44.1471 0.098 44.1596 ;
		RECT 0.0831 46.3306 0.098 46.3431 ;
		RECT 0.0831 45.7282 0.098 45.7408 ;
		RECT 0.0831 47.9118 0.098 47.9243 ;
		RECT 0.0831 47.3094 0.098 47.322 ;
		RECT 0.0831 49.4929 0.098 49.5055 ;
		RECT 0.0831 48.8906 0.098 48.9031 ;
		RECT 0.0831 36.8435 0.098 36.8561 ;
		RECT 0.0831 36.2412 0.098 36.2537 ;
		RECT 0.0831 62.1424 0.098 62.1549 ;
		RECT 0.0831 61.54 0.098 61.5525 ;
		 LAYER V2 SPACING 0 ;
		RECT 0.0481 27.3192 0.1097 27.6204 ;
		RECT 0.0215 27.2435 0.0364 27.2561 ;
		RECT 0.021 27.5447 0.0359 27.5573 ;
		RECT 0.0831 27.6647 0.098 27.6773 ;
		RECT 0.0831 27.8153 0.098 27.8278 ;
		RECT 0.0831 27.9659 0.098 27.9784 ;
		RECT 0.0831 28.1165 0.098 28.129 ;
		RECT 0.0831 28.2671 0.098 28.2796 ;
		RECT 0.0831 28.6686 0.098 28.6812 ;
		RECT 0.0831 28.9376 0.098 28.9502 ;
		RECT 0.0215 29.0004 0.0364 29.0129 ;
		RECT 0.0831 29.1204 0.098 29.1329 ;
		RECT 0.0831 29.271 0.098 29.2835 ;
		RECT 0.0215 29.3902 0.0364 29.4027 ;
		RECT 0.0831 29.5471 0.098 29.5596 ;
		RECT 0.0831 29.6976 0.098 29.7102 ;
		RECT 0.0831 29.8482 0.098 29.8608 ;
		RECT 0.0831 29.9988 0.098 30.0114 ;
		RECT 0.0831 30.1494 0.098 30.162 ;
		RECT 0.0831 30.3 0.098 30.3125 ;
		RECT 0.0831 30.4255 0.098 30.438 ;
		RECT 0.0831 30.551 0.098 30.5635 ;
		RECT 0.0831 30.7016 0.098 30.7141 ;
		RECT 0.0831 30.8271 0.098 30.8396 ;
		RECT 0.0831 30.9525 0.098 30.9651 ;
		RECT 0.0831 31.078 0.098 31.0906 ;
		RECT 0.0831 31.2286 0.098 31.2412 ;
		RECT 0.0831 31.3541 0.098 31.3667 ;
		RECT 0.0831 31.4796 0.098 31.4922 ;
		RECT 0.0831 31.6051 0.098 31.6176 ;
		RECT 0.0831 31.7557 0.098 31.7682 ;
		RECT 0.0831 31.8812 0.098 31.8937 ;
		RECT 0.0831 32.0067 0.098 32.0192 ;
		RECT 0.0831 32.1322 0.098 32.1447 ;
		RECT 0.0831 32.2827 0.098 32.2953 ;
		RECT 0.0831 32.4082 0.098 32.4208 ;
		RECT 0.0831 32.5337 0.098 32.5463 ;
		RECT 0.0831 32.6592 0.098 32.6718 ;
		RECT 0.0831 32.8098 0.098 32.8224 ;
		RECT 0.0831 32.9353 0.098 32.9478 ;
		RECT 0.0831 33.0608 0.098 33.0733 ;
		RECT 0.0831 33.1863 0.098 33.1988 ;
		RECT 0.0831 33.3369 0.098 33.3494 ;
		RECT 0.0831 33.4624 0.098 33.4749 ;
		RECT 0.0831 33.5878 0.098 33.6004 ;
		RECT 0.0831 33.7133 0.098 33.7259 ;
		RECT 0.0831 33.8639 0.098 33.8765 ;
		RECT 0.0831 33.9894 0.098 34.002 ;
		RECT 0.0831 34.1149 0.098 34.1275 ;
		RECT 0.0831 34.2655 0.098 34.278 ;
		RECT 0.0831 34.4161 0.098 34.4286 ;
		RECT 0.0831 2.6545 0.098 2.6671 ;
		RECT 0.0831 3.2569 0.098 3.2694 ;
		RECT 0.0831 16.8851 0.098 16.8976 ;
		RECT 0.0831 17.4875 0.098 17.5 ;
		RECT 0.0831 18.4663 0.098 18.4788 ;
		RECT 0.0831 19.0686 0.098 19.0812 ;
		RECT 0.0831 20.0475 0.098 20.06 ;
		RECT 0.0831 20.6498 0.098 20.6624 ;
		RECT 0.0831 21.6286 0.098 21.6412 ;
		RECT 0.0831 22.231 0.098 22.2435 ;
		RECT 0.0831 23.2098 0.098 23.2224 ;
		RECT 0.0831 23.8122 0.098 23.8247 ;
		RECT 0.0831 4.2357 0.098 4.2482 ;
		RECT 0.0831 4.838 0.098 4.8506 ;
		RECT 0.0831 5.8169 0.098 5.8294 ;
		RECT 0.0831 6.4192 0.098 6.4318 ;
		RECT 0.0831 7.398 0.098 7.4106 ;
		RECT 0.0831 8.0004 0.098 8.0129 ;
		RECT 0.0831 8.9792 0.098 8.9918 ;
		RECT 0.0831 9.5816 0.098 9.5941 ;
		RECT 0.0831 10.5604 0.098 10.5729 ;
		RECT 0.0831 11.1627 0.098 11.1753 ;
		RECT 0.0831 12.1416 0.098 12.1541 ;
		RECT 0.0831 12.7439 0.098 12.7565 ;
		RECT 0.0831 13.7227 0.098 13.7353 ;
		RECT 0.0831 14.3251 0.098 14.3376 ;
		RECT 0.0831 15.3039 0.098 15.3165 ;
		RECT 0.0831 15.9063 0.098 15.9188 ;
		RECT 0.0831 1.0733 0.098 1.0859 ;
		RECT 0.0831 1.6757 0.098 1.6882 ;
		RECT 0.0831 24.791 0.098 24.8035 ;
		RECT 0.0831 25.3933 0.098 25.4059 ;
		RECT 0.0831 51.0741 0.098 51.0867 ;
		RECT 0.0831 50.4718 0.098 50.4843 ;
		RECT 0.0831 52.6553 0.098 52.6678 ;
		RECT 0.0831 52.0529 0.098 52.0655 ;
		RECT 0.0831 54.2365 0.098 54.249 ;
		RECT 0.0831 53.6341 0.098 53.6467 ;
		RECT 0.0831 55.8176 0.098 55.8302 ;
		RECT 0.0831 55.2153 0.098 55.2278 ;
		RECT 0.0831 57.3988 0.098 57.4114 ;
		RECT 0.0831 56.7965 0.098 56.809 ;
		RECT 0.0831 58.98 0.098 58.9925 ;
		RECT 0.0831 58.3776 0.098 58.3902 ;
		RECT 0.0831 60.5612 0.098 60.5737 ;
		RECT 0.0831 59.9588 0.098 59.9714 ;
		RECT 0.0831 38.4247 0.098 38.4373 ;
		RECT 0.0831 37.8224 0.098 37.8349 ;
		RECT 0.0831 40.0059 0.098 40.0184 ;
		RECT 0.0831 39.4035 0.098 39.4161 ;
		RECT 0.0831 41.5871 0.098 41.5996 ;
		RECT 0.0831 40.9847 0.098 40.9973 ;
		RECT 0.0831 43.1682 0.098 43.1808 ;
		RECT 0.0831 42.5659 0.098 42.5784 ;
		RECT 0.0831 44.7494 0.098 44.762 ;
		RECT 0.0831 44.1471 0.098 44.1596 ;
		RECT 0.0831 46.3306 0.098 46.3431 ;
		RECT 0.0831 45.7282 0.098 45.7408 ;
		RECT 0.0831 47.9118 0.098 47.9243 ;
		RECT 0.0831 47.3094 0.098 47.322 ;
		RECT 0.0831 49.4929 0.098 49.5055 ;
		RECT 0.0831 48.8906 0.098 48.9031 ;
		RECT 0.0831 36.8435 0.098 36.8561 ;
		RECT 0.0831 36.2412 0.098 36.2537 ;
		RECT 0.0831 62.1424 0.098 62.1549 ;
		RECT 0.0831 61.54 0.098 61.5525 ;
	END

END HDDP_256X33M8B1

END LIBRARY

